VERSION 5.8 ;
BUSBITCHARS "[]" ;
DIVIDERCHAR "/" ;
UNITS
    DATABASE MICRONS 1000 ;
END UNITS

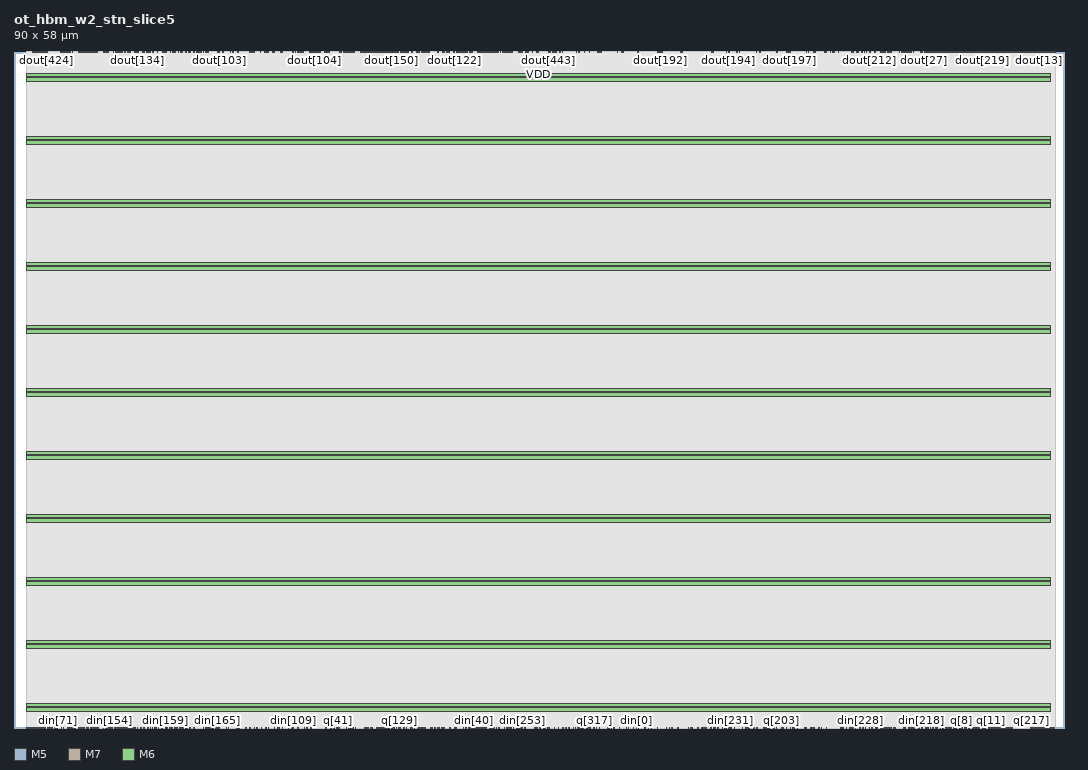
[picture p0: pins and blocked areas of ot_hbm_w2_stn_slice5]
MACRO ot_hbm_w2_stn_slice5
  FOREIGN ot_hbm_w2_stn_slice5 0 0 ;
  CLASS BLOCK ;
  SIZE 90 BY 58 ;
  PIN clk
    DIRECTION INPUT ;
    USE SIGNAL ;
    PORT
      LAYER M5 ;
        RECT  1.968 0 1.992 0.084 ;
    END
  END clk
  PIN din[0]
    DIRECTION INPUT ;
    USE SIGNAL ;
    PORT
      LAYER M5 ;
        RECT  53.328 0 53.352 0.084 ;
    END
  END din[0]
  PIN din[100]
    DIRECTION INPUT ;
    USE SIGNAL ;
    PORT
      LAYER M7 ;
        RECT  18.368 0 18.4 0.069 ;
    END
  END din[100]
  PIN din[101]
    DIRECTION INPUT ;
    USE SIGNAL ;
    PORT
      LAYER M7 ;
        RECT  18.176 0 18.208 0.069 ;
    END
  END din[101]
  PIN din[102]
    DIRECTION INPUT ;
    USE SIGNAL ;
    PORT
      LAYER M7 ;
        RECT  19.328 0 19.36 0.069 ;
    END
  END din[102]
  PIN din[103]
    DIRECTION INPUT ;
    USE SIGNAL ;
    PORT
      LAYER M5 ;
        RECT  17.04 0 17.064 0.084 ;
    END
  END din[103]
  PIN din[104]
    DIRECTION INPUT ;
    USE SIGNAL ;
    PORT
      LAYER M7 ;
        RECT  19.84 0 19.872 0.069 ;
    END
  END din[104]
  PIN din[105]
    DIRECTION INPUT ;
    USE SIGNAL ;
    PORT
      LAYER M7 ;
        RECT  17.6 0 17.632 0.069 ;
    END
  END din[105]
  PIN din[106]
    DIRECTION INPUT ;
    USE SIGNAL ;
    PORT
      LAYER M5 ;
        RECT  22.704 0 22.728 0.084 ;
    END
  END din[106]
  PIN din[107]
    DIRECTION INPUT ;
    USE SIGNAL ;
    PORT
      LAYER M7 ;
        RECT  21.568 0 21.6 0.069 ;
    END
  END din[107]
  PIN din[108]
    DIRECTION INPUT ;
    USE SIGNAL ;
    PORT
      LAYER M5 ;
        RECT  22.608 0 22.632 0.084 ;
    END
  END din[108]
  PIN din[109]
    DIRECTION INPUT ;
    USE SIGNAL ;
    PORT
      LAYER M5 ;
        RECT  23.952 0 23.976 0.084 ;
    END
  END din[109]
  PIN din[10]
    DIRECTION INPUT ;
    USE SIGNAL ;
    PORT
      LAYER M7 ;
        RECT  48.448 0 48.48 0.069 ;
    END
  END din[10]
  PIN din[110]
    DIRECTION INPUT ;
    USE SIGNAL ;
    PORT
      LAYER M5 ;
        RECT  23.76 0 23.784 0.084 ;
    END
  END din[110]
  PIN din[111]
    DIRECTION INPUT ;
    USE SIGNAL ;
    PORT
      LAYER M7 ;
        RECT  21.184 0 21.216 0.069 ;
    END
  END din[111]
  PIN din[112]
    DIRECTION INPUT ;
    USE SIGNAL ;
    PORT
      LAYER M5 ;
        RECT  27.744 0 27.768 0.084 ;
    END
  END din[112]
  PIN din[113]
    DIRECTION INPUT ;
    USE SIGNAL ;
    PORT
      LAYER M5 ;
        RECT  25.44 0 25.464 0.084 ;
    END
  END din[113]
  PIN din[114]
    DIRECTION INPUT ;
    USE SIGNAL ;
    PORT
      LAYER M5 ;
        RECT  17.328 0 17.352 0.084 ;
    END
  END din[114]
  PIN din[115]
    DIRECTION INPUT ;
    USE SIGNAL ;
    PORT
      LAYER M5 ;
        RECT  28.704 0 28.728 0.084 ;
    END
  END din[115]
  PIN din[116]
    DIRECTION INPUT ;
    USE SIGNAL ;
    PORT
      LAYER M7 ;
        RECT  20.608 0 20.64 0.069 ;
    END
  END din[116]
  PIN din[117]
    DIRECTION INPUT ;
    USE SIGNAL ;
    PORT
      LAYER M7 ;
        RECT  9.216 0 9.248 0.069 ;
    END
  END din[117]
  PIN din[118]
    DIRECTION INPUT ;
    USE SIGNAL ;
    PORT
      LAYER M5 ;
        RECT  26.736 0 26.76 0.084 ;
    END
  END din[118]
  PIN din[119]
    DIRECTION INPUT ;
    USE SIGNAL ;
    PORT
      LAYER M7 ;
        RECT  31.232 0 31.264 0.069 ;
    END
  END din[119]
  PIN din[11]
    DIRECTION INPUT ;
    USE SIGNAL ;
    PORT
      LAYER M7 ;
        RECT  58.112 0 58.144 0.069 ;
    END
  END din[11]
  PIN din[120]
    DIRECTION INPUT ;
    USE SIGNAL ;
    PORT
      LAYER M7 ;
        RECT  29.248 0 29.28 0.069 ;
    END
  END din[120]
  PIN din[121]
    DIRECTION INPUT ;
    USE SIGNAL ;
    PORT
      LAYER M7 ;
        RECT  32.576 0 32.608 0.069 ;
    END
  END din[121]
  PIN din[122]
    DIRECTION INPUT ;
    USE SIGNAL ;
    PORT
      LAYER M7 ;
        RECT  31.168 0 31.2 0.069 ;
    END
  END din[122]
  PIN din[123]
    DIRECTION INPUT ;
    USE SIGNAL ;
    PORT
      LAYER M7 ;
        RECT  33.408 0 33.44 0.069 ;
    END
  END din[123]
  PIN din[124]
    DIRECTION INPUT ;
    USE SIGNAL ;
    PORT
      LAYER M7 ;
        RECT  30.72 0 30.752 0.069 ;
    END
  END din[124]
  PIN din[125]
    DIRECTION INPUT ;
    USE SIGNAL ;
    PORT
      LAYER M7 ;
        RECT  33.6 0 33.632 0.069 ;
    END
  END din[125]
  PIN din[126]
    DIRECTION INPUT ;
    USE SIGNAL ;
    PORT
      LAYER M7 ;
        RECT  32.32 0 32.352 0.069 ;
    END
  END din[126]
  PIN din[127]
    DIRECTION INPUT ;
    USE SIGNAL ;
    PORT
      LAYER M7 ;
        RECT  31.936 0 31.968 0.069 ;
    END
  END din[127]
  PIN din[128]
    DIRECTION INPUT ;
    USE SIGNAL ;
    PORT
      LAYER M7 ;
        RECT  7.04 0 7.072 0.069 ;
    END
  END din[128]
  PIN din[129]
    DIRECTION INPUT ;
    USE SIGNAL ;
    PORT
      LAYER M5 ;
        RECT  3.504 0 3.528 0.084 ;
    END
  END din[129]
  PIN din[12]
    DIRECTION INPUT ;
    USE SIGNAL ;
    PORT
      LAYER M7 ;
        RECT  59.328 0 59.36 0.069 ;
    END
  END din[12]
  PIN din[130]
    DIRECTION INPUT ;
    USE SIGNAL ;
    PORT
      LAYER M7 ;
        RECT  6.592 0 6.624 0.069 ;
    END
  END din[130]
  PIN din[131]
    DIRECTION INPUT ;
    USE SIGNAL ;
    PORT
      LAYER M5 ;
        RECT  4.704 0 4.728 0.084 ;
    END
  END din[131]
  PIN din[132]
    DIRECTION INPUT ;
    USE SIGNAL ;
    PORT
      LAYER M5 ;
        RECT  5.616 0 5.64 0.084 ;
    END
  END din[132]
  PIN din[133]
    DIRECTION INPUT ;
    USE SIGNAL ;
    PORT
      LAYER M5 ;
        RECT  6.384 0 6.408 0.084 ;
    END
  END din[133]
  PIN din[134]
    DIRECTION INPUT ;
    USE SIGNAL ;
    PORT
      LAYER M7 ;
        RECT  6.528 0 6.56 0.069 ;
    END
  END din[134]
  PIN din[135]
    DIRECTION INPUT ;
    USE SIGNAL ;
    PORT
      LAYER M5 ;
        RECT  4.944 0 4.968 0.084 ;
    END
  END din[135]
  PIN din[136]
    DIRECTION INPUT ;
    USE SIGNAL ;
    PORT
      LAYER M5 ;
        RECT  4.032 0 4.056 0.084 ;
    END
  END din[136]
  PIN din[137]
    DIRECTION INPUT ;
    USE SIGNAL ;
    PORT
      LAYER M5 ;
        RECT  5.808 0 5.832 0.084 ;
    END
  END din[137]
  PIN din[138]
    DIRECTION INPUT ;
    USE SIGNAL ;
    PORT
      LAYER M5 ;
        RECT  3.264 0 3.288 0.084 ;
    END
  END din[138]
  PIN din[139]
    DIRECTION INPUT ;
    USE SIGNAL ;
    PORT
      LAYER M5 ;
        RECT  3.072 0 3.096 0.084 ;
    END
  END din[139]
  PIN din[13]
    DIRECTION INPUT ;
    USE SIGNAL ;
    PORT
      LAYER M7 ;
        RECT  58.56 0 58.592 0.069 ;
    END
  END din[13]
  PIN din[140]
    DIRECTION INPUT ;
    USE SIGNAL ;
    PORT
      LAYER M5 ;
        RECT  3.456 0 3.48 0.084 ;
    END
  END din[140]
  PIN din[141]
    DIRECTION INPUT ;
    USE SIGNAL ;
    PORT
      LAYER M5 ;
        RECT  2.832 0 2.856 0.084 ;
    END
  END din[141]
  PIN din[142]
    DIRECTION INPUT ;
    USE SIGNAL ;
    PORT
      LAYER M5 ;
        RECT  1.344 0 1.368 0.084 ;
    END
  END din[142]
  PIN din[143]
    DIRECTION INPUT ;
    USE SIGNAL ;
    PORT
      LAYER M5 ;
        RECT  1.104 0 1.128 0.084 ;
    END
  END din[143]
  PIN din[144]
    DIRECTION INPUT ;
    USE SIGNAL ;
    PORT
      LAYER M5 ;
        RECT  1.824 0 1.848 0.084 ;
    END
  END din[144]
  PIN din[145]
    DIRECTION INPUT ;
    USE SIGNAL ;
    PORT
      LAYER M5 ;
        RECT  2.064 0 2.088 0.084 ;
    END
  END din[145]
  PIN din[146]
    DIRECTION INPUT ;
    USE SIGNAL ;
    PORT
      LAYER M5 ;
        RECT  1.152 0 1.176 0.084 ;
    END
  END din[146]
  PIN din[147]
    DIRECTION INPUT ;
    USE SIGNAL ;
    PORT
      LAYER M5 ;
        RECT  1.584 0 1.608 0.084 ;
    END
  END din[147]
  PIN din[148]
    DIRECTION INPUT ;
    USE SIGNAL ;
    PORT
      LAYER M5 ;
        RECT  1.488 0 1.512 0.084 ;
    END
  END din[148]
  PIN din[149]
    DIRECTION INPUT ;
    USE SIGNAL ;
    PORT
      LAYER M5 ;
        RECT  1.296 0 1.32 0.084 ;
    END
  END din[149]
  PIN din[14]
    DIRECTION INPUT ;
    USE SIGNAL ;
    PORT
      LAYER M5 ;
        RECT  64.704 0 64.728 0.084 ;
    END
  END din[14]
  PIN din[150]
    DIRECTION INPUT ;
    USE SIGNAL ;
    PORT
      LAYER M5 ;
        RECT  1.44 0 1.464 0.084 ;
    END
  END din[150]
  PIN din[151]
    DIRECTION INPUT ;
    USE SIGNAL ;
    PORT
      LAYER M5 ;
        RECT  2.4 0 2.424 0.084 ;
    END
  END din[151]
  PIN din[152]
    DIRECTION INPUT ;
    USE SIGNAL ;
    PORT
      LAYER M5 ;
        RECT  2.304 0 2.328 0.084 ;
    END
  END din[152]
  PIN din[153]
    DIRECTION INPUT ;
    USE SIGNAL ;
    PORT
      LAYER M5 ;
        RECT  1.728 0 1.752 0.084 ;
    END
  END din[153]
  PIN din[154]
    DIRECTION INPUT ;
    USE SIGNAL ;
    PORT
      LAYER M7 ;
        RECT  8.128 0 8.16 0.069 ;
    END
  END din[154]
  PIN din[155]
    DIRECTION INPUT ;
    USE SIGNAL ;
    PORT
      LAYER M5 ;
        RECT  13.344 0 13.368 0.084 ;
    END
  END din[155]
  PIN din[156]
    DIRECTION INPUT ;
    USE SIGNAL ;
    PORT
      LAYER M5 ;
        RECT  13.776 0 13.8 0.084 ;
    END
  END din[156]
  PIN din[157]
    DIRECTION INPUT ;
    USE SIGNAL ;
    PORT
      LAYER M5 ;
        RECT  13.92 0 13.944 0.084 ;
    END
  END din[157]
  PIN din[158]
    DIRECTION INPUT ;
    USE SIGNAL ;
    PORT
      LAYER M7 ;
        RECT  8.32 0 8.352 0.069 ;
    END
  END din[158]
  PIN din[159]
    DIRECTION INPUT ;
    USE SIGNAL ;
    PORT
      LAYER M5 ;
        RECT  12.96 0 12.984 0.084 ;
    END
  END din[159]
  PIN din[15]
    DIRECTION INPUT ;
    USE SIGNAL ;
    PORT
      LAYER M5 ;
        RECT  64.368 0 64.392 0.084 ;
    END
  END din[15]
  PIN din[160]
    DIRECTION INPUT ;
    USE SIGNAL ;
    PORT
      LAYER M5 ;
        RECT  11.472 0 11.496 0.084 ;
    END
  END din[160]
  PIN din[161]
    DIRECTION INPUT ;
    USE SIGNAL ;
    PORT
      LAYER M7 ;
        RECT  9.088 0 9.12 0.069 ;
    END
  END din[161]
  PIN din[162]
    DIRECTION INPUT ;
    USE SIGNAL ;
    PORT
      LAYER M7 ;
        RECT  8.256 0 8.288 0.069 ;
    END
  END din[162]
  PIN din[163]
    DIRECTION INPUT ;
    USE SIGNAL ;
    PORT
      LAYER M5 ;
        RECT  12.384 0 12.408 0.084 ;
    END
  END din[163]
  PIN din[164]
    DIRECTION INPUT ;
    USE SIGNAL ;
    PORT
      LAYER M7 ;
        RECT  10.176 0 10.208 0.069 ;
    END
  END din[164]
  PIN din[165]
    DIRECTION INPUT ;
    USE SIGNAL ;
    PORT
      LAYER M5 ;
        RECT  17.472 0 17.496 0.084 ;
    END
  END din[165]
  PIN din[166]
    DIRECTION INPUT ;
    USE SIGNAL ;
    PORT
      LAYER M5 ;
        RECT  5.184 0 5.208 0.084 ;
    END
  END din[166]
  PIN din[167]
    DIRECTION INPUT ;
    USE SIGNAL ;
    PORT
      LAYER M5 ;
        RECT  17.376 0 17.4 0.084 ;
    END
  END din[167]
  PIN din[168]
    DIRECTION INPUT ;
    USE SIGNAL ;
    PORT
      LAYER M5 ;
        RECT  16.224 0 16.248 0.084 ;
    END
  END din[168]
  PIN din[169]
    DIRECTION INPUT ;
    USE SIGNAL ;
    PORT
      LAYER M5 ;
        RECT  16.944 0 16.968 0.084 ;
    END
  END din[169]
  PIN din[16]
    DIRECTION INPUT ;
    USE SIGNAL ;
    PORT
      LAYER M5 ;
        RECT  62.976 0 63 0.084 ;
    END
  END din[16]
  PIN din[170]
    DIRECTION INPUT ;
    USE SIGNAL ;
    PORT
      LAYER M5 ;
        RECT  16.848 0 16.872 0.084 ;
    END
  END din[170]
  PIN din[171]
    DIRECTION INPUT ;
    USE SIGNAL ;
    PORT
      LAYER M5 ;
        RECT  12.048 0 12.072 0.084 ;
    END
  END din[171]
  PIN din[172]
    DIRECTION INPUT ;
    USE SIGNAL ;
    PORT
      LAYER M5 ;
        RECT  16.896 0 16.92 0.084 ;
    END
  END din[172]
  PIN din[173]
    DIRECTION INPUT ;
    USE SIGNAL ;
    PORT
      LAYER M5 ;
        RECT  15.408 0 15.432 0.084 ;
    END
  END din[173]
  PIN din[174]
    DIRECTION INPUT ;
    USE SIGNAL ;
    PORT
      LAYER M5 ;
        RECT  15.024 0 15.048 0.084 ;
    END
  END din[174]
  PIN din[175]
    DIRECTION INPUT ;
    USE SIGNAL ;
    PORT
      LAYER M5 ;
        RECT  16.608 0 16.632 0.084 ;
    END
  END din[175]
  PIN din[176]
    DIRECTION INPUT ;
    USE SIGNAL ;
    PORT
      LAYER M5 ;
        RECT  16.416 0 16.44 0.084 ;
    END
  END din[176]
  PIN din[177]
    DIRECTION INPUT ;
    USE SIGNAL ;
    PORT
      LAYER M5 ;
        RECT  14.784 0 14.808 0.084 ;
    END
  END din[177]
  PIN din[178]
    DIRECTION INPUT ;
    USE SIGNAL ;
    PORT
      LAYER M5 ;
        RECT  13.536 0 13.56 0.084 ;
    END
  END din[178]
  PIN din[179]
    DIRECTION INPUT ;
    USE SIGNAL ;
    PORT
      LAYER M5 ;
        RECT  11.424 0 11.448 0.084 ;
    END
  END din[179]
  PIN din[17]
    DIRECTION INPUT ;
    USE SIGNAL ;
    PORT
      LAYER M7 ;
        RECT  57.984 0 58.016 0.069 ;
    END
  END din[17]
  PIN din[180]
    DIRECTION INPUT ;
    USE SIGNAL ;
    PORT
      LAYER M7 ;
        RECT  8.576 0 8.608 0.069 ;
    END
  END din[180]
  PIN din[181]
    DIRECTION INPUT ;
    USE SIGNAL ;
    PORT
      LAYER M5 ;
        RECT  14.16 0 14.184 0.084 ;
    END
  END din[181]
  PIN din[182]
    DIRECTION INPUT ;
    USE SIGNAL ;
    PORT
      LAYER M5 ;
        RECT  12.672 0 12.696 0.084 ;
    END
  END din[182]
  PIN din[183]
    DIRECTION INPUT ;
    USE SIGNAL ;
    PORT
      LAYER M7 ;
        RECT  11.136 0 11.168 0.069 ;
    END
  END din[183]
  PIN din[184]
    DIRECTION INPUT ;
    USE SIGNAL ;
    PORT
      LAYER M7 ;
        RECT  10.112 0 10.144 0.069 ;
    END
  END din[184]
  PIN din[185]
    DIRECTION INPUT ;
    USE SIGNAL ;
    PORT
      LAYER M7 ;
        RECT  9.92 0 9.952 0.069 ;
    END
  END din[185]
  PIN din[186]
    DIRECTION INPUT ;
    USE SIGNAL ;
    PORT
      LAYER M7 ;
        RECT  10.816 0 10.848 0.069 ;
    END
  END din[186]
  PIN din[187]
    DIRECTION INPUT ;
    USE SIGNAL ;
    PORT
      LAYER M7 ;
        RECT  8.192 0 8.224 0.069 ;
    END
  END din[187]
  PIN din[188]
    DIRECTION INPUT ;
    USE SIGNAL ;
    PORT
      LAYER M7 ;
        RECT  9.024 0 9.056 0.069 ;
    END
  END din[188]
  PIN din[189]
    DIRECTION INPUT ;
    USE SIGNAL ;
    PORT
      LAYER M7 ;
        RECT  9.536 0 9.568 0.069 ;
    END
  END din[189]
  PIN din[18]
    DIRECTION INPUT ;
    USE SIGNAL ;
    PORT
      LAYER M5 ;
        RECT  66.192 0 66.216 0.084 ;
    END
  END din[18]
  PIN din[190]
    DIRECTION INPUT ;
    USE SIGNAL ;
    PORT
      LAYER M7 ;
        RECT  6.656 0 6.688 0.069 ;
    END
  END din[190]
  PIN din[191]
    DIRECTION INPUT ;
    USE SIGNAL ;
    PORT
      LAYER M7 ;
        RECT  8.768 0 8.8 0.069 ;
    END
  END din[191]
  PIN din[192]
    DIRECTION INPUT ;
    USE SIGNAL ;
    PORT
      LAYER M5 ;
        RECT  53.52 0 53.544 0.084 ;
    END
  END din[192]
  PIN din[193]
    DIRECTION INPUT ;
    USE SIGNAL ;
    PORT
      LAYER M7 ;
        RECT  58.944 0 58.976 0.069 ;
    END
  END din[193]
  PIN din[194]
    DIRECTION INPUT ;
    USE SIGNAL ;
    PORT
      LAYER M5 ;
        RECT  60.96 0 60.984 0.084 ;
    END
  END din[194]
  PIN din[195]
    DIRECTION INPUT ;
    USE SIGNAL ;
    PORT
      LAYER M7 ;
        RECT  60.288 0 60.32 0.069 ;
    END
  END din[195]
  PIN din[196]
    DIRECTION INPUT ;
    USE SIGNAL ;
    PORT
      LAYER M7 ;
        RECT  48.32 0 48.352 0.069 ;
    END
  END din[196]
  PIN din[197]
    DIRECTION INPUT ;
    USE SIGNAL ;
    PORT
      LAYER M7 ;
        RECT  49.408 0 49.44 0.069 ;
    END
  END din[197]
  PIN din[198]
    DIRECTION INPUT ;
    USE SIGNAL ;
    PORT
      LAYER M5 ;
        RECT  51.216 0 51.24 0.084 ;
    END
  END din[198]
  PIN din[199]
    DIRECTION INPUT ;
    USE SIGNAL ;
    PORT
      LAYER M7 ;
        RECT  57.792 0 57.824 0.069 ;
    END
  END din[199]
  PIN din[19]
    DIRECTION INPUT ;
    USE SIGNAL ;
    PORT
      LAYER M5 ;
        RECT  66.768 0 66.792 0.084 ;
    END
  END din[19]
  PIN din[1]
    DIRECTION INPUT ;
    USE SIGNAL ;
    PORT
      LAYER M7 ;
        RECT  33.024 0 33.056 0.069 ;
    END
  END din[1]
  PIN din[200]
    DIRECTION INPUT ;
    USE SIGNAL ;
    PORT
      LAYER M7 ;
        RECT  48.64 0 48.672 0.069 ;
    END
  END din[200]
  PIN din[201]
    DIRECTION INPUT ;
    USE SIGNAL ;
    PORT
      LAYER M5 ;
        RECT  49.92 0 49.944 0.084 ;
    END
  END din[201]
  PIN din[202]
    DIRECTION INPUT ;
    USE SIGNAL ;
    PORT
      LAYER M5 ;
        RECT  50.832 0 50.856 0.084 ;
    END
  END din[202]
  PIN din[203]
    DIRECTION INPUT ;
    USE SIGNAL ;
    PORT
      LAYER M5 ;
        RECT  62.832 0 62.856 0.084 ;
    END
  END din[203]
  PIN din[204]
    DIRECTION INPUT ;
    USE SIGNAL ;
    PORT
      LAYER M5 ;
        RECT  61.44 0 61.464 0.084 ;
    END
  END din[204]
  PIN din[205]
    DIRECTION INPUT ;
    USE SIGNAL ;
    PORT
      LAYER M5 ;
        RECT  61.728 0 61.752 0.084 ;
    END
  END din[205]
  PIN din[206]
    DIRECTION INPUT ;
    USE SIGNAL ;
    PORT
      LAYER M7 ;
        RECT  60.352 0 60.384 0.069 ;
    END
  END din[206]
  PIN din[207]
    DIRECTION INPUT ;
    USE SIGNAL ;
    PORT
      LAYER M7 ;
        RECT  68.544 0 68.576 0.069 ;
    END
  END din[207]
  PIN din[208]
    DIRECTION INPUT ;
    USE SIGNAL ;
    PORT
      LAYER M5 ;
        RECT  65.952 0 65.976 0.084 ;
    END
  END din[208]
  PIN din[209]
    DIRECTION INPUT ;
    USE SIGNAL ;
    PORT
      LAYER M5 ;
        RECT  64.608 0 64.632 0.084 ;
    END
  END din[209]
  PIN din[20]
    DIRECTION INPUT ;
    USE SIGNAL ;
    PORT
      LAYER M7 ;
        RECT  60.736 0 60.768 0.069 ;
    END
  END din[20]
  PIN din[210]
    DIRECTION INPUT ;
    USE SIGNAL ;
    PORT
      LAYER M5 ;
        RECT  65.328 0 65.352 0.084 ;
    END
  END din[210]
  PIN din[211]
    DIRECTION INPUT ;
    USE SIGNAL ;
    PORT
      LAYER M7 ;
        RECT  71.616 0 71.648 0.069 ;
    END
  END din[211]
  PIN din[212]
    DIRECTION INPUT ;
    USE SIGNAL ;
    PORT
      LAYER M7 ;
        RECT  48.768 0 48.8 0.069 ;
    END
  END din[212]
  PIN din[213]
    DIRECTION INPUT ;
    USE SIGNAL ;
    PORT
      LAYER M7 ;
        RECT  71.68 0 71.712 0.069 ;
    END
  END din[213]
  PIN din[214]
    DIRECTION INPUT ;
    USE SIGNAL ;
    PORT
      LAYER M5 ;
        RECT  74.544 0 74.568 0.084 ;
    END
  END din[214]
  PIN din[215]
    DIRECTION INPUT ;
    USE SIGNAL ;
    PORT
      LAYER M5 ;
        RECT  74.88 0 74.904 0.084 ;
    END
  END din[215]
  PIN din[216]
    DIRECTION INPUT ;
    USE SIGNAL ;
    PORT
      LAYER M5 ;
        RECT  75.072 0 75.096 0.084 ;
    END
  END din[216]
  PIN din[217]
    DIRECTION INPUT ;
    USE SIGNAL ;
    PORT
      LAYER M7 ;
        RECT  45.888 0 45.92 0.069 ;
    END
  END din[217]
  PIN din[218]
    DIRECTION INPUT ;
    USE SIGNAL ;
    PORT
      LAYER M5 ;
        RECT  77.808 0 77.832 0.084 ;
    END
  END din[218]
  PIN din[219]
    DIRECTION INPUT ;
    USE SIGNAL ;
    PORT
      LAYER M5 ;
        RECT  76.368 0 76.392 0.084 ;
    END
  END din[219]
  PIN din[21]
    DIRECTION INPUT ;
    USE SIGNAL ;
    PORT
      LAYER M5 ;
        RECT  33.6 0 33.624 0.084 ;
    END
  END din[21]
  PIN din[220]
    DIRECTION INPUT ;
    USE SIGNAL ;
    PORT
      LAYER M5 ;
        RECT  77.76 0 77.784 0.084 ;
    END
  END din[220]
  PIN din[221]
    DIRECTION INPUT ;
    USE SIGNAL ;
    PORT
      LAYER M5 ;
        RECT  76.8 0 76.824 0.084 ;
    END
  END din[221]
  PIN din[222]
    DIRECTION INPUT ;
    USE SIGNAL ;
    PORT
      LAYER M5 ;
        RECT  76.944 0 76.968 0.084 ;
    END
  END din[222]
  PIN din[223]
    DIRECTION INPUT ;
    USE SIGNAL ;
    PORT
      LAYER M5 ;
        RECT  73.824 0 73.848 0.084 ;
    END
  END din[223]
  PIN din[224]
    DIRECTION INPUT ;
    USE SIGNAL ;
    PORT
      LAYER M5 ;
        RECT  75.12 0 75.144 0.084 ;
    END
  END din[224]
  PIN din[225]
    DIRECTION INPUT ;
    USE SIGNAL ;
    PORT
      LAYER M5 ;
        RECT  74.592 0 74.616 0.084 ;
    END
  END din[225]
  PIN din[226]
    DIRECTION INPUT ;
    USE SIGNAL ;
    PORT
      LAYER M5 ;
        RECT  73.872 0 73.896 0.084 ;
    END
  END din[226]
  PIN din[227]
    DIRECTION INPUT ;
    USE SIGNAL ;
    PORT
      LAYER M5 ;
        RECT  73.92 0 73.944 0.084 ;
    END
  END din[227]
  PIN din[228]
    DIRECTION INPUT ;
    USE SIGNAL ;
    PORT
      LAYER M5 ;
        RECT  72.576 0 72.6 0.084 ;
    END
  END din[228]
  PIN din[229]
    DIRECTION INPUT ;
    USE SIGNAL ;
    PORT
      LAYER M7 ;
        RECT  59.968 0 60 0.069 ;
    END
  END din[229]
  PIN din[22]
    DIRECTION INPUT ;
    USE SIGNAL ;
    PORT
      LAYER M5 ;
        RECT  51.888 0 51.912 0.084 ;
    END
  END din[22]
  PIN din[230]
    DIRECTION INPUT ;
    USE SIGNAL ;
    PORT
      LAYER M7 ;
        RECT  71.872 0 71.904 0.069 ;
    END
  END din[230]
  PIN din[231]
    DIRECTION INPUT ;
    USE SIGNAL ;
    PORT
      LAYER M5 ;
        RECT  61.392 0 61.416 0.084 ;
    END
  END din[231]
  PIN din[232]
    DIRECTION INPUT ;
    USE SIGNAL ;
    PORT
      LAYER M7 ;
        RECT  68.288 0 68.32 0.069 ;
    END
  END din[232]
  PIN din[233]
    DIRECTION INPUT ;
    USE SIGNAL ;
    PORT
      LAYER M7 ;
        RECT  70.976 0 71.008 0.069 ;
    END
  END din[233]
  PIN din[234]
    DIRECTION INPUT ;
    USE SIGNAL ;
    PORT
      LAYER M7 ;
        RECT  68.352 0 68.384 0.069 ;
    END
  END din[234]
  PIN din[235]
    DIRECTION INPUT ;
    USE SIGNAL ;
    PORT
      LAYER M7 ;
        RECT  70.848 0 70.88 0.069 ;
    END
  END din[235]
  PIN din[236]
    DIRECTION INPUT ;
    USE SIGNAL ;
    PORT
      LAYER M7 ;
        RECT  67.776 0 67.808 0.069 ;
    END
  END din[236]
  PIN din[237]
    DIRECTION INPUT ;
    USE SIGNAL ;
    PORT
      LAYER M5 ;
        RECT  61.248 0 61.272 0.084 ;
    END
  END din[237]
  PIN din[238]
    DIRECTION INPUT ;
    USE SIGNAL ;
    PORT
      LAYER M5 ;
        RECT  64.224 0 64.248 0.084 ;
    END
  END din[238]
  PIN din[239]
    DIRECTION INPUT ;
    USE SIGNAL ;
    PORT
      LAYER M5 ;
        RECT  61.344 0 61.368 0.084 ;
    END
  END din[239]
  PIN din[23]
    DIRECTION INPUT ;
    USE SIGNAL ;
    PORT
      LAYER M5 ;
        RECT  61.056 0 61.08 0.084 ;
    END
  END din[23]
  PIN din[240]
    DIRECTION INPUT ;
    USE SIGNAL ;
    PORT
      LAYER M5 ;
        RECT  63.696 0 63.72 0.084 ;
    END
  END din[240]
  PIN din[241]
    DIRECTION INPUT ;
    USE SIGNAL ;
    PORT
      LAYER M5 ;
        RECT  55.92 0 55.944 0.084 ;
    END
  END din[241]
  PIN din[242]
    DIRECTION INPUT ;
    USE SIGNAL ;
    PORT
      LAYER M7 ;
        RECT  56.384 0 56.416 0.069 ;
    END
  END din[242]
  PIN din[243]
    DIRECTION INPUT ;
    USE SIGNAL ;
    PORT
      LAYER M5 ;
        RECT  55.152 0 55.176 0.084 ;
    END
  END din[243]
  PIN din[244]
    DIRECTION INPUT ;
    USE SIGNAL ;
    PORT
      LAYER M5 ;
        RECT  53.088 0 53.112 0.084 ;
    END
  END din[244]
  PIN din[245]
    DIRECTION INPUT ;
    USE SIGNAL ;
    PORT
      LAYER M7 ;
        RECT  47.552 0 47.584 0.069 ;
    END
  END din[245]
  PIN din[246]
    DIRECTION INPUT ;
    USE SIGNAL ;
    PORT
      LAYER M7 ;
        RECT  48.384 0 48.416 0.069 ;
    END
  END din[246]
  PIN din[247]
    DIRECTION INPUT ;
    USE SIGNAL ;
    PORT
      LAYER M7 ;
        RECT  48.512 0 48.544 0.069 ;
    END
  END din[247]
  PIN din[248]
    DIRECTION INPUT ;
    USE SIGNAL ;
    PORT
      LAYER M7 ;
        RECT  47.04 0 47.072 0.069 ;
    END
  END din[248]
  PIN din[249]
    DIRECTION INPUT ;
    USE SIGNAL ;
    PORT
      LAYER M7 ;
        RECT  45.376 0 45.408 0.069 ;
    END
  END din[249]
  PIN din[24]
    DIRECTION INPUT ;
    USE SIGNAL ;
    PORT
      LAYER M5 ;
        RECT  61.776 0 61.8 0.084 ;
    END
  END din[24]
  PIN din[250]
    DIRECTION INPUT ;
    USE SIGNAL ;
    PORT
      LAYER M7 ;
        RECT  44.8 0 44.832 0.069 ;
    END
  END din[250]
  PIN din[251]
    DIRECTION INPUT ;
    USE SIGNAL ;
    PORT
      LAYER M5 ;
        RECT  42.576 0 42.6 0.084 ;
    END
  END din[251]
  PIN din[252]
    DIRECTION INPUT ;
    USE SIGNAL ;
    PORT
      LAYER M5 ;
        RECT  42.624 0 42.648 0.084 ;
    END
  END din[252]
  PIN din[253]
    DIRECTION INPUT ;
    USE SIGNAL ;
    PORT
      LAYER M5 ;
        RECT  43.584 0 43.608 0.084 ;
    END
  END din[253]
  PIN din[254]
    DIRECTION INPUT ;
    USE SIGNAL ;
    PORT
      LAYER M7 ;
        RECT  45.12 0 45.152 0.069 ;
    END
  END din[254]
  PIN din[255]
    DIRECTION INPUT ;
    USE SIGNAL ;
    PORT
      LAYER M5 ;
        RECT  43.44 0 43.464 0.084 ;
    END
  END din[255]
  PIN din[256]
    DIRECTION INPUT ;
    USE SIGNAL ;
    PORT
      LAYER M5 ;
        RECT  51.408 0 51.432 0.084 ;
    END
  END din[256]
  PIN din[257]
    DIRECTION INPUT ;
    USE SIGNAL ;
    PORT
      LAYER M5 ;
        RECT  54.624 0 54.648 0.084 ;
    END
  END din[257]
  PIN din[258]
    DIRECTION INPUT ;
    USE SIGNAL ;
    PORT
      LAYER M7 ;
        RECT  56.896 0 56.928 0.069 ;
    END
  END din[258]
  PIN din[259]
    DIRECTION INPUT ;
    USE SIGNAL ;
    PORT
      LAYER M5 ;
        RECT  54.048 0 54.072 0.084 ;
    END
  END din[259]
  PIN din[25]
    DIRECTION INPUT ;
    USE SIGNAL ;
    PORT
      LAYER M5 ;
        RECT  41.184 0 41.208 0.084 ;
    END
  END din[25]
  PIN din[260]
    DIRECTION INPUT ;
    USE SIGNAL ;
    PORT
      LAYER M7 ;
        RECT  69.632 0 69.664 0.069 ;
    END
  END din[260]
  PIN din[261]
    DIRECTION INPUT ;
    USE SIGNAL ;
    PORT
      LAYER M5 ;
        RECT  60.864 0 60.888 0.084 ;
    END
  END din[261]
  PIN din[262]
    DIRECTION INPUT ;
    USE SIGNAL ;
    PORT
      LAYER M7 ;
        RECT  59.264 0 59.296 0.069 ;
    END
  END din[262]
  PIN din[263]
    DIRECTION INPUT ;
    USE SIGNAL ;
    PORT
      LAYER M7 ;
        RECT  59.136 0 59.168 0.069 ;
    END
  END din[263]
  PIN din[264]
    DIRECTION INPUT ;
    USE SIGNAL ;
    PORT
      LAYER M7 ;
        RECT  67.84 0 67.872 0.069 ;
    END
  END din[264]
  PIN din[265]
    DIRECTION INPUT ;
    USE SIGNAL ;
    PORT
      LAYER M5 ;
        RECT  62.448 0 62.472 0.084 ;
    END
  END din[265]
  PIN din[266]
    DIRECTION INPUT ;
    USE SIGNAL ;
    PORT
      LAYER M7 ;
        RECT  59.712 0 59.744 0.069 ;
    END
  END din[266]
  PIN din[267]
    DIRECTION INPUT ;
    USE SIGNAL ;
    PORT
      LAYER M5 ;
        RECT  66.576 0 66.6 0.084 ;
    END
  END din[267]
  PIN din[268]
    DIRECTION INPUT ;
    USE SIGNAL ;
    PORT
      LAYER M5 ;
        RECT  63.408 0 63.432 0.084 ;
    END
  END din[268]
  PIN din[269]
    DIRECTION INPUT ;
    USE SIGNAL ;
    PORT
      LAYER M5 ;
        RECT  66.912 0 66.936 0.084 ;
    END
  END din[269]
  PIN din[26]
    DIRECTION INPUT ;
    USE SIGNAL ;
    PORT
      LAYER M5 ;
        RECT  38.928 0 38.952 0.084 ;
    END
  END din[26]
  PIN din[270]
    DIRECTION INPUT ;
    USE SIGNAL ;
    PORT
      LAYER M7 ;
        RECT  67.904 0 67.936 0.069 ;
    END
  END din[270]
  PIN din[271]
    DIRECTION INPUT ;
    USE SIGNAL ;
    PORT
      LAYER M7 ;
        RECT  68.608 0 68.64 0.069 ;
    END
  END din[271]
  PIN din[272]
    DIRECTION INPUT ;
    USE SIGNAL ;
    PORT
      LAYER M7 ;
        RECT  71.744 0 71.776 0.069 ;
    END
  END din[272]
  PIN din[273]
    DIRECTION INPUT ;
    USE SIGNAL ;
    PORT
      LAYER M7 ;
        RECT  71.04 0 71.072 0.069 ;
    END
  END din[273]
  PIN din[274]
    DIRECTION INPUT ;
    USE SIGNAL ;
    PORT
      LAYER M5 ;
        RECT  73.344 0 73.368 0.084 ;
    END
  END din[274]
  PIN din[275]
    DIRECTION INPUT ;
    USE SIGNAL ;
    PORT
      LAYER M5 ;
        RECT  74.64 0 74.664 0.084 ;
    END
  END din[275]
  PIN din[276]
    DIRECTION INPUT ;
    USE SIGNAL ;
    PORT
      LAYER M5 ;
        RECT  75.504 0 75.528 0.084 ;
    END
  END din[276]
  PIN din[277]
    DIRECTION INPUT ;
    USE SIGNAL ;
    PORT
      LAYER M5 ;
        RECT  72.432 0 72.456 0.084 ;
    END
  END din[277]
  PIN din[278]
    DIRECTION INPUT ;
    USE SIGNAL ;
    PORT
      LAYER M5 ;
        RECT  74.736 0 74.76 0.084 ;
    END
  END din[278]
  PIN din[279]
    DIRECTION INPUT ;
    USE SIGNAL ;
    PORT
      LAYER M5 ;
        RECT  72.96 0 72.984 0.084 ;
    END
  END din[279]
  PIN din[27]
    DIRECTION INPUT ;
    USE SIGNAL ;
    PORT
      LAYER M5 ;
        RECT  35.28 0 35.304 0.084 ;
    END
  END din[27]
  PIN din[28]
    DIRECTION INPUT ;
    USE SIGNAL ;
    PORT
      LAYER M5 ;
        RECT  38.976 0 39 0.084 ;
    END
  END din[28]
  PIN din[29]
    DIRECTION INPUT ;
    USE SIGNAL ;
    PORT
      LAYER M5 ;
        RECT  43.776 0 43.8 0.084 ;
    END
  END din[29]
  PIN din[2]
    DIRECTION INPUT ;
    USE SIGNAL ;
    PORT
      LAYER M5 ;
        RECT  52.464 0 52.488 0.084 ;
    END
  END din[2]
  PIN din[30]
    DIRECTION INPUT ;
    USE SIGNAL ;
    PORT
      LAYER M5 ;
        RECT  41.04 0 41.064 0.084 ;
    END
  END din[30]
  PIN din[31]
    DIRECTION INPUT ;
    USE SIGNAL ;
    PORT
      LAYER M5 ;
        RECT  35.232 0 35.256 0.084 ;
    END
  END din[31]
  PIN din[32]
    DIRECTION INPUT ;
    USE SIGNAL ;
    PORT
      LAYER M5 ;
        RECT  43.104 0 43.128 0.084 ;
    END
  END din[32]
  PIN din[33]
    DIRECTION INPUT ;
    USE SIGNAL ;
    PORT
      LAYER M5 ;
        RECT  42.336 0 42.36 0.084 ;
    END
  END din[33]
  PIN din[34]
    DIRECTION INPUT ;
    USE SIGNAL ;
    PORT
      LAYER M5 ;
        RECT  42.816 0 42.84 0.084 ;
    END
  END din[34]
  PIN din[35]
    DIRECTION INPUT ;
    USE SIGNAL ;
    PORT
      LAYER M5 ;
        RECT  35.04 0 35.064 0.084 ;
    END
  END din[35]
  PIN din[36]
    DIRECTION INPUT ;
    USE SIGNAL ;
    PORT
      LAYER M5 ;
        RECT  42.288 0 42.312 0.084 ;
    END
  END din[36]
  PIN din[37]
    DIRECTION INPUT ;
    USE SIGNAL ;
    PORT
      LAYER M5 ;
        RECT  40.176 0 40.2 0.084 ;
    END
  END din[37]
  PIN din[38]
    DIRECTION INPUT ;
    USE SIGNAL ;
    PORT
      LAYER M5 ;
        RECT  40.08 0 40.104 0.084 ;
    END
  END din[38]
  PIN din[39]
    DIRECTION INPUT ;
    USE SIGNAL ;
    PORT
      LAYER M5 ;
        RECT  40.416 0 40.44 0.084 ;
    END
  END din[39]
  PIN din[3]
    DIRECTION INPUT ;
    USE SIGNAL ;
    PORT
      LAYER M7 ;
        RECT  49.088 0 49.12 0.069 ;
    END
  END din[3]
  PIN din[40]
    DIRECTION INPUT ;
    USE SIGNAL ;
    PORT
      LAYER M5 ;
        RECT  39.456 0 39.48 0.084 ;
    END
  END din[40]
  PIN din[41]
    DIRECTION INPUT ;
    USE SIGNAL ;
    PORT
      LAYER M5 ;
        RECT  38.736 0 38.76 0.084 ;
    END
  END din[41]
  PIN din[42]
    DIRECTION INPUT ;
    USE SIGNAL ;
    PORT
      LAYER M5 ;
        RECT  38.688 0 38.712 0.084 ;
    END
  END din[42]
  PIN din[43]
    DIRECTION INPUT ;
    USE SIGNAL ;
    PORT
      LAYER M5 ;
        RECT  37.776 0 37.8 0.084 ;
    END
  END din[43]
  PIN din[44]
    DIRECTION INPUT ;
    USE SIGNAL ;
    PORT
      LAYER M5 ;
        RECT  37.92 0 37.944 0.084 ;
    END
  END din[44]
  PIN din[45]
    DIRECTION INPUT ;
    USE SIGNAL ;
    PORT
      LAYER M5 ;
        RECT  36.384 0 36.408 0.084 ;
    END
  END din[45]
  PIN din[46]
    DIRECTION INPUT ;
    USE SIGNAL ;
    PORT
      LAYER M5 ;
        RECT  36.672 0 36.696 0.084 ;
    END
  END din[46]
  PIN din[47]
    DIRECTION INPUT ;
    USE SIGNAL ;
    PORT
      LAYER M5 ;
        RECT  35.184 0 35.208 0.084 ;
    END
  END din[47]
  PIN din[48]
    DIRECTION INPUT ;
    USE SIGNAL ;
    PORT
      LAYER M5 ;
        RECT  36.864 0 36.888 0.084 ;
    END
  END din[48]
  PIN din[49]
    DIRECTION INPUT ;
    USE SIGNAL ;
    PORT
      LAYER M7 ;
        RECT  32.448 0 32.48 0.069 ;
    END
  END din[49]
  PIN din[4]
    DIRECTION INPUT ;
    USE SIGNAL ;
    PORT
      LAYER M5 ;
        RECT  51.36 0 51.384 0.084 ;
    END
  END din[4]
  PIN din[50]
    DIRECTION INPUT ;
    USE SIGNAL ;
    PORT
      LAYER M7 ;
        RECT  32.768 0 32.8 0.069 ;
    END
  END din[50]
  PIN din[51]
    DIRECTION INPUT ;
    USE SIGNAL ;
    PORT
      LAYER M7 ;
        RECT  31.872 0 31.904 0.069 ;
    END
  END din[51]
  PIN din[52]
    DIRECTION INPUT ;
    USE SIGNAL ;
    PORT
      LAYER M5 ;
        RECT  34.608 0 34.632 0.084 ;
    END
  END din[52]
  PIN din[53]
    DIRECTION INPUT ;
    USE SIGNAL ;
    PORT
      LAYER M5 ;
        RECT  35.664 0 35.688 0.084 ;
    END
  END din[53]
  PIN din[54]
    DIRECTION INPUT ;
    USE SIGNAL ;
    PORT
      LAYER M5 ;
        RECT  34.56 0 34.584 0.084 ;
    END
  END din[54]
  PIN din[55]
    DIRECTION INPUT ;
    USE SIGNAL ;
    PORT
      LAYER M5 ;
        RECT  34.8 0 34.824 0.084 ;
    END
  END din[55]
  PIN din[56]
    DIRECTION INPUT ;
    USE SIGNAL ;
    PORT
      LAYER M5 ;
        RECT  36 0 36.024 0.084 ;
    END
  END din[56]
  PIN din[57]
    DIRECTION INPUT ;
    USE SIGNAL ;
    PORT
      LAYER M7 ;
        RECT  32.128 0 32.16 0.069 ;
    END
  END din[57]
  PIN din[58]
    DIRECTION INPUT ;
    USE SIGNAL ;
    PORT
      LAYER M7 ;
        RECT  31.488 0 31.52 0.069 ;
    END
  END din[58]
  PIN din[59]
    DIRECTION INPUT ;
    USE SIGNAL ;
    PORT
      LAYER M7 ;
        RECT  32.192 0 32.224 0.069 ;
    END
  END din[59]
  PIN din[5]
    DIRECTION INPUT ;
    USE SIGNAL ;
    PORT
      LAYER M5 ;
        RECT  50.16 0 50.184 0.084 ;
    END
  END din[5]
  PIN din[60]
    DIRECTION INPUT ;
    USE SIGNAL ;
    PORT
      LAYER M7 ;
        RECT  31.552 0 31.584 0.069 ;
    END
  END din[60]
  PIN din[61]
    DIRECTION INPUT ;
    USE SIGNAL ;
    PORT
      LAYER M7 ;
        RECT  31.68 0 31.712 0.069 ;
    END
  END din[61]
  PIN din[62]
    DIRECTION INPUT ;
    USE SIGNAL ;
    PORT
      LAYER M7 ;
        RECT  32.96 0 32.992 0.069 ;
    END
  END din[62]
  PIN din[63]
    DIRECTION INPUT ;
    USE SIGNAL ;
    PORT
      LAYER M7 ;
        RECT  31.744 0 31.776 0.069 ;
    END
  END din[63]
  PIN din[64]
    DIRECTION INPUT ;
    USE SIGNAL ;
    PORT
      LAYER M5 ;
        RECT  16.992 0 17.016 0.084 ;
    END
  END din[64]
  PIN din[65]
    DIRECTION INPUT ;
    USE SIGNAL ;
    PORT
      LAYER M7 ;
        RECT  7.936 0 7.968 0.069 ;
    END
  END din[65]
  PIN din[66]
    DIRECTION INPUT ;
    USE SIGNAL ;
    PORT
      LAYER M7 ;
        RECT  8.64 0 8.672 0.069 ;
    END
  END din[66]
  PIN din[67]
    DIRECTION INPUT ;
    USE SIGNAL ;
    PORT
      LAYER M7 ;
        RECT  9.792 0 9.824 0.069 ;
    END
  END din[67]
  PIN din[68]
    DIRECTION INPUT ;
    USE SIGNAL ;
    PORT
      LAYER M7 ;
        RECT  6.72 0 6.752 0.069 ;
    END
  END din[68]
  PIN din[69]
    DIRECTION INPUT ;
    USE SIGNAL ;
    PORT
      LAYER M5 ;
        RECT  5.952 0 5.976 0.084 ;
    END
  END din[69]
  PIN din[6]
    DIRECTION INPUT ;
    USE SIGNAL ;
    PORT
      LAYER M5 ;
        RECT  40.32 0 40.344 0.084 ;
    END
  END din[6]
  PIN din[70]
    DIRECTION INPUT ;
    USE SIGNAL ;
    PORT
      LAYER M5 ;
        RECT  6.192 0 6.216 0.084 ;
    END
  END din[70]
  PIN din[71]
    DIRECTION INPUT ;
    USE SIGNAL ;
    PORT
      LAYER M5 ;
        RECT  3.744 0 3.768 0.084 ;
    END
  END din[71]
  PIN din[72]
    DIRECTION INPUT ;
    USE SIGNAL ;
    PORT
      LAYER M5 ;
        RECT  2.544 0 2.568 0.084 ;
    END
  END din[72]
  PIN din[73]
    DIRECTION INPUT ;
    USE SIGNAL ;
    PORT
      LAYER M5 ;
        RECT  1.248 0 1.272 0.084 ;
    END
  END din[73]
  PIN din[74]
    DIRECTION INPUT ;
    USE SIGNAL ;
    PORT
      LAYER M5 ;
        RECT  3.168 0 3.192 0.084 ;
    END
  END din[74]
  PIN din[75]
    DIRECTION INPUT ;
    USE SIGNAL ;
    PORT
      LAYER M5 ;
        RECT  1.2 0 1.224 0.084 ;
    END
  END din[75]
  PIN din[76]
    DIRECTION INPUT ;
    USE SIGNAL ;
    PORT
      LAYER M5 ;
        RECT  1.392 0 1.416 0.084 ;
    END
  END din[76]
  PIN din[77]
    DIRECTION INPUT ;
    USE SIGNAL ;
    PORT
      LAYER M5 ;
        RECT  4.56 0 4.584 0.084 ;
    END
  END din[77]
  PIN din[78]
    DIRECTION INPUT ;
    USE SIGNAL ;
    PORT
      LAYER M5 ;
        RECT  1.536 0 1.56 0.084 ;
    END
  END din[78]
  PIN din[79]
    DIRECTION INPUT ;
    USE SIGNAL ;
    PORT
      LAYER M5 ;
        RECT  2.016 0 2.04 0.084 ;
    END
  END din[79]
  PIN din[7]
    DIRECTION INPUT ;
    USE SIGNAL ;
    PORT
      LAYER M5 ;
        RECT  52.656 0 52.68 0.084 ;
    END
  END din[7]
  PIN din[80]
    DIRECTION INPUT ;
    USE SIGNAL ;
    PORT
      LAYER M5 ;
        RECT  2.256 0 2.28 0.084 ;
    END
  END din[80]
  PIN din[81]
    DIRECTION INPUT ;
    USE SIGNAL ;
    PORT
      LAYER M5 ;
        RECT  6.24 0 6.264 0.084 ;
    END
  END din[81]
  PIN din[82]
    DIRECTION INPUT ;
    USE SIGNAL ;
    PORT
      LAYER M5 ;
        RECT  1.776 0 1.8 0.084 ;
    END
  END din[82]
  PIN din[83]
    DIRECTION INPUT ;
    USE SIGNAL ;
    PORT
      LAYER M5 ;
        RECT  4.224 0 4.248 0.084 ;
    END
  END din[83]
  PIN din[84]
    DIRECTION INPUT ;
    USE SIGNAL ;
    PORT
      LAYER M5 ;
        RECT  2.496 0 2.52 0.084 ;
    END
  END din[84]
  PIN din[85]
    DIRECTION INPUT ;
    USE SIGNAL ;
    PORT
      LAYER M5 ;
        RECT  5.664 0 5.688 0.084 ;
    END
  END din[85]
  PIN din[86]
    DIRECTION INPUT ;
    USE SIGNAL ;
    PORT
      LAYER M7 ;
        RECT  8.448 0 8.48 0.069 ;
    END
  END din[86]
  PIN din[87]
    DIRECTION INPUT ;
    USE SIGNAL ;
    PORT
      LAYER M5 ;
        RECT  3.12 0 3.144 0.084 ;
    END
  END din[87]
  PIN din[88]
    DIRECTION INPUT ;
    USE SIGNAL ;
    PORT
      LAYER M7 ;
        RECT  8.384 0 8.416 0.069 ;
    END
  END din[88]
  PIN din[89]
    DIRECTION INPUT ;
    USE SIGNAL ;
    PORT
      LAYER M7 ;
        RECT  6.784 0 6.816 0.069 ;
    END
  END din[89]
  PIN din[8]
    DIRECTION INPUT ;
    USE SIGNAL ;
    PORT
      LAYER M5 ;
        RECT  42.048 0 42.072 0.084 ;
    END
  END din[8]
  PIN din[90]
    DIRECTION INPUT ;
    USE SIGNAL ;
    PORT
      LAYER M7 ;
        RECT  8.704 0 8.736 0.069 ;
    END
  END din[90]
  PIN din[91]
    DIRECTION INPUT ;
    USE SIGNAL ;
    PORT
      LAYER M5 ;
        RECT  4.8 0 4.824 0.084 ;
    END
  END din[91]
  PIN din[92]
    DIRECTION INPUT ;
    USE SIGNAL ;
    PORT
      LAYER M7 ;
        RECT  6.976 0 7.008 0.069 ;
    END
  END din[92]
  PIN din[93]
    DIRECTION INPUT ;
    USE SIGNAL ;
    PORT
      LAYER M7 ;
        RECT  9.28 0 9.312 0.069 ;
    END
  END din[93]
  PIN din[94]
    DIRECTION INPUT ;
    USE SIGNAL ;
    PORT
      LAYER M5 ;
        RECT  11.712 0 11.736 0.084 ;
    END
  END din[94]
  PIN din[95]
    DIRECTION INPUT ;
    USE SIGNAL ;
    PORT
      LAYER M5 ;
        RECT  12.72 0 12.744 0.084 ;
    END
  END din[95]
  PIN din[96]
    DIRECTION INPUT ;
    USE SIGNAL ;
    PORT
      LAYER M7 ;
        RECT  10.368 0 10.4 0.069 ;
    END
  END din[96]
  PIN din[97]
    DIRECTION INPUT ;
    USE SIGNAL ;
    PORT
      LAYER M5 ;
        RECT  16.512 0 16.536 0.084 ;
    END
  END din[97]
  PIN din[98]
    DIRECTION INPUT ;
    USE SIGNAL ;
    PORT
      LAYER M5 ;
        RECT  14.88 0 14.904 0.084 ;
    END
  END din[98]
  PIN din[99]
    DIRECTION INPUT ;
    USE SIGNAL ;
    PORT
      LAYER M5 ;
        RECT  13.968 0 13.992 0.084 ;
    END
  END din[99]
  PIN din[9]
    DIRECTION INPUT ;
    USE SIGNAL ;
    PORT
      LAYER M5 ;
        RECT  37.392 0 37.416 0.084 ;
    END
  END din[9]
  PIN dout[0]
    DIRECTION OUTPUT ;
    USE SIGNAL ;
    PORT
      LAYER M7 ;
        RECT  84.608 57.931 84.64 58 ;
    END
  END dout[0]
  PIN dout[100]
    DIRECTION OUTPUT ;
    USE SIGNAL ;
    PORT
      LAYER M7 ;
        RECT  6.784 57.931 6.816 58 ;
    END
  END dout[100]
  PIN dout[101]
    DIRECTION OUTPUT ;
    USE SIGNAL ;
    PORT
      LAYER M7 ;
        RECT  20.416 57.931 20.448 58 ;
    END
  END dout[101]
  PIN dout[102]
    DIRECTION OUTPUT ;
    USE SIGNAL ;
    PORT
      LAYER M7 ;
        RECT  21.12 57.931 21.152 58 ;
    END
  END dout[102]
  PIN dout[103]
    DIRECTION OUTPUT ;
    USE SIGNAL ;
    PORT
      LAYER M5 ;
        RECT  17.568 57.916 17.592 58 ;
    END
  END dout[103]
  PIN dout[104]
    DIRECTION OUTPUT ;
    USE SIGNAL ;
    PORT
      LAYER M5 ;
        RECT  25.728 57.916 25.752 58 ;
    END
  END dout[104]
  PIN dout[105]
    DIRECTION OUTPUT ;
    USE SIGNAL ;
    PORT
      LAYER M5 ;
        RECT  26.784 57.916 26.808 58 ;
    END
  END dout[105]
  PIN dout[106]
    DIRECTION OUTPUT ;
    USE SIGNAL ;
    PORT
      LAYER M7 ;
        RECT  41.152 57.931 41.184 58 ;
    END
  END dout[106]
  PIN dout[107]
    DIRECTION OUTPUT ;
    USE SIGNAL ;
    PORT
      LAYER M7 ;
        RECT  30.016 57.931 30.048 58 ;
    END
  END dout[107]
  PIN dout[108]
    DIRECTION OUTPUT ;
    USE SIGNAL ;
    PORT
      LAYER M7 ;
        RECT  22.144 57.931 22.176 58 ;
    END
  END dout[108]
  PIN dout[109]
    DIRECTION OUTPUT ;
    USE SIGNAL ;
    PORT
      LAYER M5 ;
        RECT  26.208 57.916 26.232 58 ;
    END
  END dout[109]
  PIN dout[10]
    DIRECTION OUTPUT ;
    USE SIGNAL ;
    PORT
      LAYER M7 ;
        RECT  78.272 57.931 78.304 58 ;
    END
  END dout[10]
  PIN dout[110]
    DIRECTION OUTPUT ;
    USE SIGNAL ;
    PORT
      LAYER M7 ;
        RECT  41.408 57.931 41.44 58 ;
    END
  END dout[110]
  PIN dout[111]
    DIRECTION OUTPUT ;
    USE SIGNAL ;
    PORT
      LAYER M5 ;
        RECT  26.832 57.916 26.856 58 ;
    END
  END dout[111]
  PIN dout[112]
    DIRECTION OUTPUT ;
    USE SIGNAL ;
    PORT
      LAYER M7 ;
        RECT  43.392 57.931 43.424 58 ;
    END
  END dout[112]
  PIN dout[113]
    DIRECTION OUTPUT ;
    USE SIGNAL ;
    PORT
      LAYER M7 ;
        RECT  21.504 57.931 21.536 58 ;
    END
  END dout[113]
  PIN dout[114]
    DIRECTION OUTPUT ;
    USE SIGNAL ;
    PORT
      LAYER M5 ;
        RECT  25.44 57.916 25.464 58 ;
    END
  END dout[114]
  PIN dout[115]
    DIRECTION OUTPUT ;
    USE SIGNAL ;
    PORT
      LAYER M7 ;
        RECT  31.232 57.931 31.264 58 ;
    END
  END dout[115]
  PIN dout[116]
    DIRECTION OUTPUT ;
    USE SIGNAL ;
    PORT
      LAYER M5 ;
        RECT  12.912 57.916 12.936 58 ;
    END
  END dout[116]
  PIN dout[117]
    DIRECTION OUTPUT ;
    USE SIGNAL ;
    PORT
      LAYER M7 ;
        RECT  41.664 57.931 41.696 58 ;
    END
  END dout[117]
  PIN dout[118]
    DIRECTION OUTPUT ;
    USE SIGNAL ;
    PORT
      LAYER M5 ;
        RECT  28.464 57.916 28.488 58 ;
    END
  END dout[118]
  PIN dout[119]
    DIRECTION OUTPUT ;
    USE SIGNAL ;
    PORT
      LAYER M7 ;
        RECT  44.928 57.931 44.96 58 ;
    END
  END dout[119]
  PIN dout[11]
    DIRECTION OUTPUT ;
    USE SIGNAL ;
    PORT
      LAYER M5 ;
        RECT  80.496 57.916 80.52 58 ;
    END
  END dout[11]
  PIN dout[120]
    DIRECTION OUTPUT ;
    USE SIGNAL ;
    PORT
      LAYER M5 ;
        RECT  34.944 57.916 34.968 58 ;
    END
  END dout[120]
  PIN dout[121]
    DIRECTION OUTPUT ;
    USE SIGNAL ;
    PORT
      LAYER M7 ;
        RECT  40 57.931 40.032 58 ;
    END
  END dout[121]
  PIN dout[122]
    DIRECTION OUTPUT ;
    USE SIGNAL ;
    PORT
      LAYER M5 ;
        RECT  37.776 57.916 37.8 58 ;
    END
  END dout[122]
  PIN dout[123]
    DIRECTION OUTPUT ;
    USE SIGNAL ;
    PORT
      LAYER M7 ;
        RECT  43.84 57.931 43.872 58 ;
    END
  END dout[123]
  PIN dout[124]
    DIRECTION OUTPUT ;
    USE SIGNAL ;
    PORT
      LAYER M5 ;
        RECT  46.992 57.916 47.016 58 ;
    END
  END dout[124]
  PIN dout[125]
    DIRECTION OUTPUT ;
    USE SIGNAL ;
    PORT
      LAYER M7 ;
        RECT  41.28 57.931 41.312 58 ;
    END
  END dout[125]
  PIN dout[126]
    DIRECTION OUTPUT ;
    USE SIGNAL ;
    PORT
      LAYER M7 ;
        RECT  41.856 57.931 41.888 58 ;
    END
  END dout[126]
  PIN dout[127]
    DIRECTION OUTPUT ;
    USE SIGNAL ;
    PORT
      LAYER M7 ;
        RECT  33.728 57.931 33.76 58 ;
    END
  END dout[127]
  PIN dout[128]
    DIRECTION OUTPUT ;
    USE SIGNAL ;
    PORT
      LAYER M5 ;
        RECT  37.248 57.916 37.272 58 ;
    END
  END dout[128]
  PIN dout[129]
    DIRECTION OUTPUT ;
    USE SIGNAL ;
    PORT
      LAYER M5 ;
        RECT  35.568 57.916 35.592 58 ;
    END
  END dout[129]
  PIN dout[12]
    DIRECTION OUTPUT ;
    USE SIGNAL ;
    PORT
      LAYER M7 ;
        RECT  78.656 57.931 78.688 58 ;
    END
  END dout[12]
  PIN dout[130]
    DIRECTION OUTPUT ;
    USE SIGNAL ;
    PORT
      LAYER M5 ;
        RECT  11.856 57.916 11.88 58 ;
    END
  END dout[130]
  PIN dout[131]
    DIRECTION OUTPUT ;
    USE SIGNAL ;
    PORT
      LAYER M7 ;
        RECT  40.064 57.931 40.096 58 ;
    END
  END dout[131]
  PIN dout[132]
    DIRECTION OUTPUT ;
    USE SIGNAL ;
    PORT
      LAYER M5 ;
        RECT  9.168 57.916 9.192 58 ;
    END
  END dout[132]
  PIN dout[133]
    DIRECTION OUTPUT ;
    USE SIGNAL ;
    PORT
      LAYER M7 ;
        RECT  32.896 57.931 32.928 58 ;
    END
  END dout[133]
  PIN dout[134]
    DIRECTION OUTPUT ;
    USE SIGNAL ;
    PORT
      LAYER M5 ;
        RECT  10.56 57.916 10.584 58 ;
    END
  END dout[134]
  PIN dout[135]
    DIRECTION OUTPUT ;
    USE SIGNAL ;
    PORT
      LAYER M5 ;
        RECT  13.824 57.916 13.848 58 ;
    END
  END dout[135]
  PIN dout[136]
    DIRECTION OUTPUT ;
    USE SIGNAL ;
    PORT
      LAYER M5 ;
        RECT  8.832 57.916 8.856 58 ;
    END
  END dout[136]
  PIN dout[137]
    DIRECTION OUTPUT ;
    USE SIGNAL ;
    PORT
      LAYER M5 ;
        RECT  27.984 57.916 28.008 58 ;
    END
  END dout[137]
  PIN dout[138]
    DIRECTION OUTPUT ;
    USE SIGNAL ;
    PORT
      LAYER M7 ;
        RECT  5.568 57.931 5.6 58 ;
    END
  END dout[138]
  PIN dout[139]
    DIRECTION OUTPUT ;
    USE SIGNAL ;
    PORT
      LAYER M5 ;
        RECT  11.088 57.916 11.112 58 ;
    END
  END dout[139]
  PIN dout[13]
    DIRECTION OUTPUT ;
    USE SIGNAL ;
    PORT
      LAYER M5 ;
        RECT  89.184 57.916 89.208 58 ;
    END
  END dout[13]
  PIN dout[140]
    DIRECTION OUTPUT ;
    USE SIGNAL ;
    PORT
      LAYER M5 ;
        RECT  1.584 57.916 1.608 58 ;
    END
  END dout[140]
  PIN dout[141]
    DIRECTION OUTPUT ;
    USE SIGNAL ;
    PORT
      LAYER M7 ;
        RECT  40.192 57.931 40.224 58 ;
    END
  END dout[141]
  PIN dout[142]
    DIRECTION OUTPUT ;
    USE SIGNAL ;
    PORT
      LAYER M7 ;
        RECT  4.224 57.931 4.256 58 ;
    END
  END dout[142]
  PIN dout[143]
    DIRECTION OUTPUT ;
    USE SIGNAL ;
    PORT
      LAYER M7 ;
        RECT  6.272 57.931 6.304 58 ;
    END
  END dout[143]
  PIN dout[144]
    DIRECTION OUTPUT ;
    USE SIGNAL ;
    PORT
      LAYER M5 ;
        RECT  2.256 57.916 2.28 58 ;
    END
  END dout[144]
  PIN dout[145]
    DIRECTION OUTPUT ;
    USE SIGNAL ;
    PORT
      LAYER M5 ;
        RECT  34.512 57.916 34.536 58 ;
    END
  END dout[145]
  PIN dout[146]
    DIRECTION OUTPUT ;
    USE SIGNAL ;
    PORT
      LAYER M7 ;
        RECT  6.656 57.931 6.688 58 ;
    END
  END dout[146]
  PIN dout[147]
    DIRECTION OUTPUT ;
    USE SIGNAL ;
    PORT
      LAYER M7 ;
        RECT  5.632 57.931 5.664 58 ;
    END
  END dout[147]
  PIN dout[148]
    DIRECTION OUTPUT ;
    USE SIGNAL ;
    PORT
      LAYER M5 ;
        RECT  7.632 57.916 7.656 58 ;
    END
  END dout[148]
  PIN dout[149]
    DIRECTION OUTPUT ;
    USE SIGNAL ;
    PORT
      LAYER M7 ;
        RECT  4.736 57.931 4.768 58 ;
    END
  END dout[149]
  PIN dout[14]
    DIRECTION OUTPUT ;
    USE SIGNAL ;
    PORT
      LAYER M7 ;
        RECT  81.152 57.931 81.184 58 ;
    END
  END dout[14]
  PIN dout[150]
    DIRECTION OUTPUT ;
    USE SIGNAL ;
    PORT
      LAYER M7 ;
        RECT  32.32 57.931 32.352 58 ;
    END
  END dout[150]
  PIN dout[151]
    DIRECTION OUTPUT ;
    USE SIGNAL ;
    PORT
      LAYER M5 ;
        RECT  40.08 57.916 40.104 58 ;
    END
  END dout[151]
  PIN dout[152]
    DIRECTION OUTPUT ;
    USE SIGNAL ;
    PORT
      LAYER M7 ;
        RECT  29.76 57.931 29.792 58 ;
    END
  END dout[152]
  PIN dout[153]
    DIRECTION OUTPUT ;
    USE SIGNAL ;
    PORT
      LAYER M7 ;
        RECT  30.208 57.931 30.24 58 ;
    END
  END dout[153]
  PIN dout[154]
    DIRECTION OUTPUT ;
    USE SIGNAL ;
    PORT
      LAYER M5 ;
        RECT  28.8 57.916 28.824 58 ;
    END
  END dout[154]
  PIN dout[155]
    DIRECTION OUTPUT ;
    USE SIGNAL ;
    PORT
      LAYER M7 ;
        RECT  30.592 57.931 30.624 58 ;
    END
  END dout[155]
  PIN dout[156]
    DIRECTION OUTPUT ;
    USE SIGNAL ;
    PORT
      LAYER M7 ;
        RECT  32.128 57.931 32.16 58 ;
    END
  END dout[156]
  PIN dout[157]
    DIRECTION OUTPUT ;
    USE SIGNAL ;
    PORT
      LAYER M5 ;
        RECT  35.088 57.916 35.112 58 ;
    END
  END dout[157]
  PIN dout[158]
    DIRECTION OUTPUT ;
    USE SIGNAL ;
    PORT
      LAYER M5 ;
        RECT  24.672 57.916 24.696 58 ;
    END
  END dout[158]
  PIN dout[159]
    DIRECTION OUTPUT ;
    USE SIGNAL ;
    PORT
      LAYER M5 ;
        RECT  25.872 57.916 25.896 58 ;
    END
  END dout[159]
  PIN dout[15]
    DIRECTION OUTPUT ;
    USE SIGNAL ;
    PORT
      LAYER M5 ;
        RECT  84.624 57.916 84.648 58 ;
    END
  END dout[15]
  PIN dout[160]
    DIRECTION OUTPUT ;
    USE SIGNAL ;
    PORT
      LAYER M7 ;
        RECT  41.024 57.931 41.056 58 ;
    END
  END dout[160]
  PIN dout[161]
    DIRECTION OUTPUT ;
    USE SIGNAL ;
    PORT
      LAYER M5 ;
        RECT  35.28 57.916 35.304 58 ;
    END
  END dout[161]
  PIN dout[162]
    DIRECTION OUTPUT ;
    USE SIGNAL ;
    PORT
      LAYER M7 ;
        RECT  31.36 57.931 31.392 58 ;
    END
  END dout[162]
  PIN dout[163]
    DIRECTION OUTPUT ;
    USE SIGNAL ;
    PORT
      LAYER M5 ;
        RECT  45.888 57.916 45.912 58 ;
    END
  END dout[163]
  PIN dout[164]
    DIRECTION OUTPUT ;
    USE SIGNAL ;
    PORT
      LAYER M7 ;
        RECT  32.704 57.931 32.736 58 ;
    END
  END dout[164]
  PIN dout[165]
    DIRECTION OUTPUT ;
    USE SIGNAL ;
    PORT
      LAYER M5 ;
        RECT  28.368 57.916 28.392 58 ;
    END
  END dout[165]
  PIN dout[166]
    DIRECTION OUTPUT ;
    USE SIGNAL ;
    PORT
      LAYER M5 ;
        RECT  26.976 57.916 27 58 ;
    END
  END dout[166]
  PIN dout[167]
    DIRECTION OUTPUT ;
    USE SIGNAL ;
    PORT
      LAYER M5 ;
        RECT  37.104 57.916 37.128 58 ;
    END
  END dout[167]
  PIN dout[168]
    DIRECTION OUTPUT ;
    USE SIGNAL ;
    PORT
      LAYER M5 ;
        RECT  36.288 57.916 36.312 58 ;
    END
  END dout[168]
  PIN dout[169]
    DIRECTION OUTPUT ;
    USE SIGNAL ;
    PORT
      LAYER M5 ;
        RECT  2.496 57.916 2.52 58 ;
    END
  END dout[169]
  PIN dout[16]
    DIRECTION OUTPUT ;
    USE SIGNAL ;
    PORT
      LAYER M7 ;
        RECT  81.728 57.931 81.76 58 ;
    END
  END dout[16]
  PIN dout[170]
    DIRECTION OUTPUT ;
    USE SIGNAL ;
    PORT
      LAYER M5 ;
        RECT  14.784 57.916 14.808 58 ;
    END
  END dout[170]
  PIN dout[171]
    DIRECTION OUTPUT ;
    USE SIGNAL ;
    PORT
      LAYER M7 ;
        RECT  42.688 57.931 42.72 58 ;
    END
  END dout[171]
  PIN dout[172]
    DIRECTION OUTPUT ;
    USE SIGNAL ;
    PORT
      LAYER M5 ;
        RECT  39.072 57.916 39.096 58 ;
    END
  END dout[172]
  PIN dout[173]
    DIRECTION OUTPUT ;
    USE SIGNAL ;
    PORT
      LAYER M5 ;
        RECT  1.824 57.916 1.848 58 ;
    END
  END dout[173]
  PIN dout[174]
    DIRECTION OUTPUT ;
    USE SIGNAL ;
    PORT
      LAYER M5 ;
        RECT  40.128 57.916 40.152 58 ;
    END
  END dout[174]
  PIN dout[175]
    DIRECTION OUTPUT ;
    USE SIGNAL ;
    PORT
      LAYER M5 ;
        RECT  38.832 57.916 38.856 58 ;
    END
  END dout[175]
  PIN dout[176]
    DIRECTION OUTPUT ;
    USE SIGNAL ;
    PORT
      LAYER M5 ;
        RECT  38.4 57.916 38.424 58 ;
    END
  END dout[176]
  PIN dout[177]
    DIRECTION OUTPUT ;
    USE SIGNAL ;
    PORT
      LAYER M7 ;
        RECT  33.664 57.931 33.696 58 ;
    END
  END dout[177]
  PIN dout[178]
    DIRECTION OUTPUT ;
    USE SIGNAL ;
    PORT
      LAYER M7 ;
        RECT  40.384 57.931 40.416 58 ;
    END
  END dout[178]
  PIN dout[179]
    DIRECTION OUTPUT ;
    USE SIGNAL ;
    PORT
      LAYER M5 ;
        RECT  2.208 57.916 2.232 58 ;
    END
  END dout[179]
  PIN dout[17]
    DIRECTION OUTPUT ;
    USE SIGNAL ;
    PORT
      LAYER M5 ;
        RECT  82.224 57.916 82.248 58 ;
    END
  END dout[17]
  PIN dout[180]
    DIRECTION OUTPUT ;
    USE SIGNAL ;
    PORT
      LAYER M5 ;
        RECT  38.064 57.916 38.088 58 ;
    END
  END dout[180]
  PIN dout[181]
    DIRECTION OUTPUT ;
    USE SIGNAL ;
    PORT
      LAYER M5 ;
        RECT  38.688 57.916 38.712 58 ;
    END
  END dout[181]
  PIN dout[182]
    DIRECTION OUTPUT ;
    USE SIGNAL ;
    PORT
      LAYER M5 ;
        RECT  37.92 57.916 37.944 58 ;
    END
  END dout[182]
  PIN dout[183]
    DIRECTION OUTPUT ;
    USE SIGNAL ;
    PORT
      LAYER M5 ;
        RECT  39.84 57.916 39.864 58 ;
    END
  END dout[183]
  PIN dout[184]
    DIRECTION OUTPUT ;
    USE SIGNAL ;
    PORT
      LAYER M5 ;
        RECT  40.416 57.916 40.44 58 ;
    END
  END dout[184]
  PIN dout[185]
    DIRECTION OUTPUT ;
    USE SIGNAL ;
    PORT
      LAYER M7 ;
        RECT  30.336 57.931 30.368 58 ;
    END
  END dout[185]
  PIN dout[186]
    DIRECTION OUTPUT ;
    USE SIGNAL ;
    PORT
      LAYER M5 ;
        RECT  14.4 57.916 14.424 58 ;
    END
  END dout[186]
  PIN dout[187]
    DIRECTION OUTPUT ;
    USE SIGNAL ;
    PORT
      LAYER M5 ;
        RECT  36.768 57.916 36.792 58 ;
    END
  END dout[187]
  PIN dout[188]
    DIRECTION OUTPUT ;
    USE SIGNAL ;
    PORT
      LAYER M7 ;
        RECT  18.56 57.931 18.592 58 ;
    END
  END dout[188]
  PIN dout[189]
    DIRECTION OUTPUT ;
    USE SIGNAL ;
    PORT
      LAYER M5 ;
        RECT  24.144 57.916 24.168 58 ;
    END
  END dout[189]
  PIN dout[18]
    DIRECTION OUTPUT ;
    USE SIGNAL ;
    PORT
      LAYER M7 ;
        RECT  79.104 57.931 79.136 58 ;
    END
  END dout[18]
  PIN dout[190]
    DIRECTION OUTPUT ;
    USE SIGNAL ;
    PORT
      LAYER M7 ;
        RECT  33.088 57.931 33.12 58 ;
    END
  END dout[190]
  PIN dout[191]
    DIRECTION OUTPUT ;
    USE SIGNAL ;
    PORT
      LAYER M7 ;
        RECT  33.472 57.931 33.504 58 ;
    END
  END dout[191]
  PIN dout[192]
    DIRECTION OUTPUT ;
    USE SIGNAL ;
    PORT
      LAYER M5 ;
        RECT  55.392 57.916 55.416 58 ;
    END
  END dout[192]
  PIN dout[193]
    DIRECTION OUTPUT ;
    USE SIGNAL ;
    PORT
      LAYER M5 ;
        RECT  78.192 57.916 78.216 58 ;
    END
  END dout[193]
  PIN dout[194]
    DIRECTION OUTPUT ;
    USE SIGNAL ;
    PORT
      LAYER M5 ;
        RECT  61.2 57.916 61.224 58 ;
    END
  END dout[194]
  PIN dout[195]
    DIRECTION OUTPUT ;
    USE SIGNAL ;
    PORT
      LAYER M5 ;
        RECT  82.272 57.916 82.296 58 ;
    END
  END dout[195]
  PIN dout[196]
    DIRECTION OUTPUT ;
    USE SIGNAL ;
    PORT
      LAYER M5 ;
        RECT  48.192 57.916 48.216 58 ;
    END
  END dout[196]
  PIN dout[197]
    DIRECTION OUTPUT ;
    USE SIGNAL ;
    PORT
      LAYER M5 ;
        RECT  66.432 57.916 66.456 58 ;
    END
  END dout[197]
  PIN dout[198]
    DIRECTION OUTPUT ;
    USE SIGNAL ;
    PORT
      LAYER M5 ;
        RECT  55.152 57.916 55.176 58 ;
    END
  END dout[198]
  PIN dout[199]
    DIRECTION OUTPUT ;
    USE SIGNAL ;
    PORT
      LAYER M5 ;
        RECT  63.648 57.916 63.672 58 ;
    END
  END dout[199]
  PIN dout[19]
    DIRECTION OUTPUT ;
    USE SIGNAL ;
    PORT
      LAYER M5 ;
        RECT  83.616 57.916 83.64 58 ;
    END
  END dout[19]
  PIN dout[1]
    DIRECTION OUTPUT ;
    USE SIGNAL ;
    PORT
      LAYER M5 ;
        RECT  86.688 57.916 86.712 58 ;
    END
  END dout[1]
  PIN dout[200]
    DIRECTION OUTPUT ;
    USE SIGNAL ;
    PORT
      LAYER M7 ;
        RECT  59.904 57.931 59.936 58 ;
    END
  END dout[200]
  PIN dout[201]
    DIRECTION OUTPUT ;
    USE SIGNAL ;
    PORT
      LAYER M7 ;
        RECT  57.216 57.931 57.248 58 ;
    END
  END dout[201]
  PIN dout[202]
    DIRECTION OUTPUT ;
    USE SIGNAL ;
    PORT
      LAYER M5 ;
        RECT  53.424 57.916 53.448 58 ;
    END
  END dout[202]
  PIN dout[203]
    DIRECTION OUTPUT ;
    USE SIGNAL ;
    PORT
      LAYER M7 ;
        RECT  68.096 57.931 68.128 58 ;
    END
  END dout[203]
  PIN dout[204]
    DIRECTION OUTPUT ;
    USE SIGNAL ;
    PORT
      LAYER M5 ;
        RECT  51.744 57.916 51.768 58 ;
    END
  END dout[204]
  PIN dout[205]
    DIRECTION OUTPUT ;
    USE SIGNAL ;
    PORT
      LAYER M7 ;
        RECT  70.656 57.931 70.688 58 ;
    END
  END dout[205]
  PIN dout[206]
    DIRECTION OUTPUT ;
    USE SIGNAL ;
    PORT
      LAYER M7 ;
        RECT  69.504 57.931 69.536 58 ;
    END
  END dout[206]
  PIN dout[207]
    DIRECTION OUTPUT ;
    USE SIGNAL ;
    PORT
      LAYER M5 ;
        RECT  76.944 57.916 76.968 58 ;
    END
  END dout[207]
  PIN dout[208]
    DIRECTION OUTPUT ;
    USE SIGNAL ;
    PORT
      LAYER M5 ;
        RECT  72.864 57.916 72.888 58 ;
    END
  END dout[208]
  PIN dout[209]
    DIRECTION OUTPUT ;
    USE SIGNAL ;
    PORT
      LAYER M5 ;
        RECT  75.12 57.916 75.144 58 ;
    END
  END dout[209]
  PIN dout[20]
    DIRECTION OUTPUT ;
    USE SIGNAL ;
    PORT
      LAYER M5 ;
        RECT  84.528 57.916 84.552 58 ;
    END
  END dout[20]
  PIN dout[210]
    DIRECTION OUTPUT ;
    USE SIGNAL ;
    PORT
      LAYER M5 ;
        RECT  76.608 57.916 76.632 58 ;
    END
  END dout[210]
  PIN dout[211]
    DIRECTION OUTPUT ;
    USE SIGNAL ;
    PORT
      LAYER M5 ;
        RECT  76.08 57.916 76.104 58 ;
    END
  END dout[211]
  PIN dout[212]
    DIRECTION OUTPUT ;
    USE SIGNAL ;
    PORT
      LAYER M5 ;
        RECT  73.296 57.916 73.32 58 ;
    END
  END dout[212]
  PIN dout[213]
    DIRECTION OUTPUT ;
    USE SIGNAL ;
    PORT
      LAYER M5 ;
        RECT  80.544 57.916 80.568 58 ;
    END
  END dout[213]
  PIN dout[214]
    DIRECTION OUTPUT ;
    USE SIGNAL ;
    PORT
      LAYER M7 ;
        RECT  81.792 57.931 81.824 58 ;
    END
  END dout[214]
  PIN dout[215]
    DIRECTION OUTPUT ;
    USE SIGNAL ;
    PORT
      LAYER M5 ;
        RECT  86.976 57.916 87 58 ;
    END
  END dout[215]
  PIN dout[216]
    DIRECTION OUTPUT ;
    USE SIGNAL ;
    PORT
      LAYER M7 ;
        RECT  83.392 57.931 83.424 58 ;
    END
  END dout[216]
  PIN dout[217]
    DIRECTION OUTPUT ;
    USE SIGNAL ;
    PORT
      LAYER M5 ;
        RECT  87.312 57.916 87.336 58 ;
    END
  END dout[217]
  PIN dout[218]
    DIRECTION OUTPUT ;
    USE SIGNAL ;
    PORT
      LAYER M5 ;
        RECT  87.744 57.916 87.768 58 ;
    END
  END dout[218]
  PIN dout[219]
    DIRECTION OUTPUT ;
    USE SIGNAL ;
    PORT
      LAYER M5 ;
        RECT  83.04 57.916 83.064 58 ;
    END
  END dout[219]
  PIN dout[21]
    DIRECTION OUTPUT ;
    USE SIGNAL ;
    PORT
      LAYER M5 ;
        RECT  82.992 57.916 83.016 58 ;
    END
  END dout[21]
  PIN dout[220]
    DIRECTION OUTPUT ;
    USE SIGNAL ;
    PORT
      LAYER M5 ;
        RECT  85.728 57.916 85.752 58 ;
    END
  END dout[220]
  PIN dout[221]
    DIRECTION OUTPUT ;
    USE SIGNAL ;
    PORT
      LAYER M5 ;
        RECT  86.448 57.916 86.472 58 ;
    END
  END dout[221]
  PIN dout[222]
    DIRECTION OUTPUT ;
    USE SIGNAL ;
    PORT
      LAYER M5 ;
        RECT  81.168 57.916 81.192 58 ;
    END
  END dout[222]
  PIN dout[223]
    DIRECTION OUTPUT ;
    USE SIGNAL ;
    PORT
      LAYER M5 ;
        RECT  82.608 57.916 82.632 58 ;
    END
  END dout[223]
  PIN dout[224]
    DIRECTION OUTPUT ;
    USE SIGNAL ;
    PORT
      LAYER M5 ;
        RECT  86.16 57.916 86.184 58 ;
    END
  END dout[224]
  PIN dout[225]
    DIRECTION OUTPUT ;
    USE SIGNAL ;
    PORT
      LAYER M5 ;
        RECT  84.432 57.916 84.456 58 ;
    END
  END dout[225]
  PIN dout[226]
    DIRECTION OUTPUT ;
    USE SIGNAL ;
    PORT
      LAYER M5 ;
        RECT  84.72 57.916 84.744 58 ;
    END
  END dout[226]
  PIN dout[227]
    DIRECTION OUTPUT ;
    USE SIGNAL ;
    PORT
      LAYER M5 ;
        RECT  88.512 57.916 88.536 58 ;
    END
  END dout[227]
  PIN dout[228]
    DIRECTION OUTPUT ;
    USE SIGNAL ;
    PORT
      LAYER M5 ;
        RECT  84.96 57.916 84.984 58 ;
    END
  END dout[228]
  PIN dout[229]
    DIRECTION OUTPUT ;
    USE SIGNAL ;
    PORT
      LAYER M5 ;
        RECT  83.472 57.916 83.496 58 ;
    END
  END dout[229]
  PIN dout[22]
    DIRECTION OUTPUT ;
    USE SIGNAL ;
    PORT
      LAYER M5 ;
        RECT  78.672 57.916 78.696 58 ;
    END
  END dout[22]
  PIN dout[230]
    DIRECTION OUTPUT ;
    USE SIGNAL ;
    PORT
      LAYER M5 ;
        RECT  83.712 57.916 83.736 58 ;
    END
  END dout[230]
  PIN dout[231]
    DIRECTION OUTPUT ;
    USE SIGNAL ;
    PORT
      LAYER M5 ;
        RECT  88.224 57.916 88.248 58 ;
    END
  END dout[231]
  PIN dout[232]
    DIRECTION OUTPUT ;
    USE SIGNAL ;
    PORT
      LAYER M5 ;
        RECT  81.12 57.916 81.144 58 ;
    END
  END dout[232]
  PIN dout[233]
    DIRECTION OUTPUT ;
    USE SIGNAL ;
    PORT
      LAYER M5 ;
        RECT  82.704 57.916 82.728 58 ;
    END
  END dout[233]
  PIN dout[234]
    DIRECTION OUTPUT ;
    USE SIGNAL ;
    PORT
      LAYER M7 ;
        RECT  83.968 57.931 84 58 ;
    END
  END dout[234]
  PIN dout[235]
    DIRECTION OUTPUT ;
    USE SIGNAL ;
    PORT
      LAYER M5 ;
        RECT  88.608 57.916 88.632 58 ;
    END
  END dout[235]
  PIN dout[236]
    DIRECTION OUTPUT ;
    USE SIGNAL ;
    PORT
      LAYER M5 ;
        RECT  81.888 57.916 81.912 58 ;
    END
  END dout[236]
  PIN dout[237]
    DIRECTION OUTPUT ;
    USE SIGNAL ;
    PORT
      LAYER M5 ;
        RECT  83.28 57.916 83.304 58 ;
    END
  END dout[237]
  PIN dout[238]
    DIRECTION OUTPUT ;
    USE SIGNAL ;
    PORT
      LAYER M5 ;
        RECT  85.968 57.916 85.992 58 ;
    END
  END dout[238]
  PIN dout[239]
    DIRECTION OUTPUT ;
    USE SIGNAL ;
    PORT
      LAYER M5 ;
        RECT  83.424 57.916 83.448 58 ;
    END
  END dout[239]
  PIN dout[23]
    DIRECTION OUTPUT ;
    USE SIGNAL ;
    PORT
      LAYER M7 ;
        RECT  80.96 57.931 80.992 58 ;
    END
  END dout[23]
  PIN dout[240]
    DIRECTION OUTPUT ;
    USE SIGNAL ;
    PORT
      LAYER M7 ;
        RECT  84.096 57.931 84.128 58 ;
    END
  END dout[240]
  PIN dout[241]
    DIRECTION OUTPUT ;
    USE SIGNAL ;
    PORT
      LAYER M7 ;
        RECT  83.84 57.931 83.872 58 ;
    END
  END dout[241]
  PIN dout[242]
    DIRECTION OUTPUT ;
    USE SIGNAL ;
    PORT
      LAYER M5 ;
        RECT  86.304 57.916 86.328 58 ;
    END
  END dout[242]
  PIN dout[243]
    DIRECTION OUTPUT ;
    USE SIGNAL ;
    PORT
      LAYER M5 ;
        RECT  66.336 57.916 66.36 58 ;
    END
  END dout[243]
  PIN dout[244]
    DIRECTION OUTPUT ;
    USE SIGNAL ;
    PORT
      LAYER M7 ;
        RECT  81.856 57.931 81.888 58 ;
    END
  END dout[244]
  PIN dout[245]
    DIRECTION OUTPUT ;
    USE SIGNAL ;
    PORT
      LAYER M5 ;
        RECT  50.304 57.916 50.328 58 ;
    END
  END dout[245]
  PIN dout[246]
    DIRECTION OUTPUT ;
    USE SIGNAL ;
    PORT
      LAYER M5 ;
        RECT  62.16 57.916 62.184 58 ;
    END
  END dout[246]
  PIN dout[247]
    DIRECTION OUTPUT ;
    USE SIGNAL ;
    PORT
      LAYER M5 ;
        RECT  50.112 57.916 50.136 58 ;
    END
  END dout[247]
  PIN dout[248]
    DIRECTION OUTPUT ;
    USE SIGNAL ;
    PORT
      LAYER M7 ;
        RECT  68.672 57.931 68.704 58 ;
    END
  END dout[248]
  PIN dout[249]
    DIRECTION OUTPUT ;
    USE SIGNAL ;
    PORT
      LAYER M7 ;
        RECT  42.368 57.931 42.4 58 ;
    END
  END dout[249]
  PIN dout[24]
    DIRECTION OUTPUT ;
    USE SIGNAL ;
    PORT
      LAYER M7 ;
        RECT  83.712 57.931 83.744 58 ;
    END
  END dout[24]
  PIN dout[250]
    DIRECTION OUTPUT ;
    USE SIGNAL ;
    PORT
      LAYER M5 ;
        RECT  46.464 57.916 46.488 58 ;
    END
  END dout[250]
  PIN dout[251]
    DIRECTION OUTPUT ;
    USE SIGNAL ;
    PORT
      LAYER M7 ;
        RECT  42.24 57.931 42.272 58 ;
    END
  END dout[251]
  PIN dout[252]
    DIRECTION OUTPUT ;
    USE SIGNAL ;
    PORT
      LAYER M7 ;
        RECT  43.968 57.931 44 58 ;
    END
  END dout[252]
  PIN dout[253]
    DIRECTION OUTPUT ;
    USE SIGNAL ;
    PORT
      LAYER M5 ;
        RECT  86.496 57.916 86.52 58 ;
    END
  END dout[253]
  PIN dout[254]
    DIRECTION OUTPUT ;
    USE SIGNAL ;
    PORT
      LAYER M5 ;
        RECT  48.864 57.916 48.888 58 ;
    END
  END dout[254]
  PIN dout[255]
    DIRECTION OUTPUT ;
    USE SIGNAL ;
    PORT
      LAYER M5 ;
        RECT  45.984 57.916 46.008 58 ;
    END
  END dout[255]
  PIN dout[256]
    DIRECTION OUTPUT ;
    USE SIGNAL ;
    PORT
      LAYER M5 ;
        RECT  87.888 57.916 87.912 58 ;
    END
  END dout[256]
  PIN dout[257]
    DIRECTION OUTPUT ;
    USE SIGNAL ;
    PORT
      LAYER M7 ;
        RECT  83.904 57.931 83.936 58 ;
    END
  END dout[257]
  PIN dout[258]
    DIRECTION OUTPUT ;
    USE SIGNAL ;
    PORT
      LAYER M5 ;
        RECT  87.12 57.916 87.144 58 ;
    END
  END dout[258]
  PIN dout[259]
    DIRECTION OUTPUT ;
    USE SIGNAL ;
    PORT
      LAYER M7 ;
        RECT  82.496 57.931 82.528 58 ;
    END
  END dout[259]
  PIN dout[25]
    DIRECTION OUTPUT ;
    USE SIGNAL ;
    PORT
      LAYER M5 ;
        RECT  82.512 57.916 82.536 58 ;
    END
  END dout[25]
  PIN dout[260]
    DIRECTION OUTPUT ;
    USE SIGNAL ;
    PORT
      LAYER M5 ;
        RECT  84.768 57.916 84.792 58 ;
    END
  END dout[260]
  PIN dout[261]
    DIRECTION OUTPUT ;
    USE SIGNAL ;
    PORT
      LAYER M5 ;
        RECT  88.08 57.916 88.104 58 ;
    END
  END dout[261]
  PIN dout[262]
    DIRECTION OUTPUT ;
    USE SIGNAL ;
    PORT
      LAYER M5 ;
        RECT  82.752 57.916 82.776 58 ;
    END
  END dout[262]
  PIN dout[263]
    DIRECTION OUTPUT ;
    USE SIGNAL ;
    PORT
      LAYER M7 ;
        RECT  81.216 57.931 81.248 58 ;
    END
  END dout[263]
  PIN dout[264]
    DIRECTION OUTPUT ;
    USE SIGNAL ;
    PORT
      LAYER M5 ;
        RECT  86.88 57.916 86.904 58 ;
    END
  END dout[264]
  PIN dout[265]
    DIRECTION OUTPUT ;
    USE SIGNAL ;
    PORT
      LAYER M7 ;
        RECT  78.4 57.931 78.432 58 ;
    END
  END dout[265]
  PIN dout[266]
    DIRECTION OUTPUT ;
    USE SIGNAL ;
    PORT
      LAYER M7 ;
        RECT  84.288 57.931 84.32 58 ;
    END
  END dout[266]
  PIN dout[267]
    DIRECTION OUTPUT ;
    USE SIGNAL ;
    PORT
      LAYER M5 ;
        RECT  88.176 57.916 88.2 58 ;
    END
  END dout[267]
  PIN dout[268]
    DIRECTION OUTPUT ;
    USE SIGNAL ;
    PORT
      LAYER M5 ;
        RECT  82.32 57.916 82.344 58 ;
    END
  END dout[268]
  PIN dout[269]
    DIRECTION OUTPUT ;
    USE SIGNAL ;
    PORT
      LAYER M5 ;
        RECT  86.544 57.916 86.568 58 ;
    END
  END dout[269]
  PIN dout[26]
    DIRECTION OUTPUT ;
    USE SIGNAL ;
    PORT
      LAYER M5 ;
        RECT  78.48 57.916 78.504 58 ;
    END
  END dout[26]
  PIN dout[270]
    DIRECTION OUTPUT ;
    USE SIGNAL ;
    PORT
      LAYER M5 ;
        RECT  88.416 57.916 88.44 58 ;
    END
  END dout[270]
  PIN dout[271]
    DIRECTION OUTPUT ;
    USE SIGNAL ;
    PORT
      LAYER M5 ;
        RECT  85.392 57.916 85.416 58 ;
    END
  END dout[271]
  PIN dout[272]
    DIRECTION OUTPUT ;
    USE SIGNAL ;
    PORT
      LAYER M5 ;
        RECT  81.072 57.916 81.096 58 ;
    END
  END dout[272]
  PIN dout[273]
    DIRECTION OUTPUT ;
    USE SIGNAL ;
    PORT
      LAYER M5 ;
        RECT  87.504 57.916 87.528 58 ;
    END
  END dout[273]
  PIN dout[274]
    DIRECTION OUTPUT ;
    USE SIGNAL ;
    PORT
      LAYER M5 ;
        RECT  83.856 57.916 83.88 58 ;
    END
  END dout[274]
  PIN dout[275]
    DIRECTION OUTPUT ;
    USE SIGNAL ;
    PORT
      LAYER M5 ;
        RECT  88.656 57.916 88.68 58 ;
    END
  END dout[275]
  PIN dout[276]
    DIRECTION OUTPUT ;
    USE SIGNAL ;
    PORT
      LAYER M5 ;
        RECT  80.688 57.916 80.712 58 ;
    END
  END dout[276]
  PIN dout[277]
    DIRECTION OUTPUT ;
    USE SIGNAL ;
    PORT
      LAYER M5 ;
        RECT  85.008 57.916 85.032 58 ;
    END
  END dout[277]
  PIN dout[278]
    DIRECTION OUTPUT ;
    USE SIGNAL ;
    PORT
      LAYER M5 ;
        RECT  87.936 57.916 87.96 58 ;
    END
  END dout[278]
  PIN dout[279]
    DIRECTION OUTPUT ;
    USE SIGNAL ;
    PORT
      LAYER M5 ;
        RECT  85.056 57.916 85.08 58 ;
    END
  END dout[279]
  PIN dout[27]
    DIRECTION OUTPUT ;
    USE SIGNAL ;
    PORT
      LAYER M5 ;
        RECT  78 57.916 78.024 58 ;
    END
  END dout[27]
  PIN dout[280]
    DIRECTION OUTPUT ;
    USE SIGNAL ;
    PORT
      LAYER M7 ;
        RECT  83.52 57.931 83.552 58 ;
    END
  END dout[280]
  PIN dout[281]
    DIRECTION OUTPUT ;
    USE SIGNAL ;
    PORT
      LAYER M5 ;
        RECT  81.024 57.916 81.048 58 ;
    END
  END dout[281]
  PIN dout[282]
    DIRECTION OUTPUT ;
    USE SIGNAL ;
    PORT
      LAYER M7 ;
        RECT  84.48 57.931 84.512 58 ;
    END
  END dout[282]
  PIN dout[283]
    DIRECTION OUTPUT ;
    USE SIGNAL ;
    PORT
      LAYER M5 ;
        RECT  81.648 57.916 81.672 58 ;
    END
  END dout[283]
  PIN dout[284]
    DIRECTION OUTPUT ;
    USE SIGNAL ;
    PORT
      LAYER M7 ;
        RECT  80.128 57.931 80.16 58 ;
    END
  END dout[284]
  PIN dout[285]
    DIRECTION OUTPUT ;
    USE SIGNAL ;
    PORT
      LAYER M5 ;
        RECT  85.296 57.916 85.32 58 ;
    END
  END dout[285]
  PIN dout[286]
    DIRECTION OUTPUT ;
    USE SIGNAL ;
    PORT
      LAYER M5 ;
        RECT  84.48 57.916 84.504 58 ;
    END
  END dout[286]
  PIN dout[287]
    DIRECTION OUTPUT ;
    USE SIGNAL ;
    PORT
      LAYER M7 ;
        RECT  79.552 57.931 79.584 58 ;
    END
  END dout[287]
  PIN dout[288]
    DIRECTION OUTPUT ;
    USE SIGNAL ;
    PORT
      LAYER M7 ;
        RECT  84.352 57.931 84.384 58 ;
    END
  END dout[288]
  PIN dout[289]
    DIRECTION OUTPUT ;
    USE SIGNAL ;
    PORT
      LAYER M7 ;
        RECT  79.488 57.931 79.52 58 ;
    END
  END dout[289]
  PIN dout[28]
    DIRECTION OUTPUT ;
    USE SIGNAL ;
    PORT
      LAYER M5 ;
        RECT  76.272 57.916 76.296 58 ;
    END
  END dout[28]
  PIN dout[290]
    DIRECTION OUTPUT ;
    USE SIGNAL ;
    PORT
      LAYER M7 ;
        RECT  81.536 57.931 81.568 58 ;
    END
  END dout[290]
  PIN dout[291]
    DIRECTION OUTPUT ;
    USE SIGNAL ;
    PORT
      LAYER M5 ;
        RECT  82.944 57.916 82.968 58 ;
    END
  END dout[291]
  PIN dout[292]
    DIRECTION OUTPUT ;
    USE SIGNAL ;
    PORT
      LAYER M7 ;
        RECT  79.808 57.931 79.84 58 ;
    END
  END dout[292]
  PIN dout[293]
    DIRECTION OUTPUT ;
    USE SIGNAL ;
    PORT
      LAYER M5 ;
        RECT  88.128 57.916 88.152 58 ;
    END
  END dout[293]
  PIN dout[294]
    DIRECTION OUTPUT ;
    USE SIGNAL ;
    PORT
      LAYER M7 ;
        RECT  81.088 57.931 81.12 58 ;
    END
  END dout[294]
  PIN dout[295]
    DIRECTION OUTPUT ;
    USE SIGNAL ;
    PORT
      LAYER M5 ;
        RECT  86.016 57.916 86.04 58 ;
    END
  END dout[295]
  PIN dout[296]
    DIRECTION OUTPUT ;
    USE SIGNAL ;
    PORT
      LAYER M7 ;
        RECT  81.6 57.931 81.632 58 ;
    END
  END dout[296]
  PIN dout[297]
    DIRECTION OUTPUT ;
    USE SIGNAL ;
    PORT
      LAYER M5 ;
        RECT  83.904 57.916 83.928 58 ;
    END
  END dout[297]
  PIN dout[298]
    DIRECTION OUTPUT ;
    USE SIGNAL ;
    PORT
      LAYER M7 ;
        RECT  78.72 57.931 78.752 58 ;
    END
  END dout[298]
  PIN dout[299]
    DIRECTION OUTPUT ;
    USE SIGNAL ;
    PORT
      LAYER M5 ;
        RECT  82.848 57.916 82.872 58 ;
    END
  END dout[299]
  PIN dout[29]
    DIRECTION OUTPUT ;
    USE SIGNAL ;
    PORT
      LAYER M5 ;
        RECT  78.336 57.916 78.36 58 ;
    END
  END dout[29]
  PIN dout[2]
    DIRECTION OUTPUT ;
    USE SIGNAL ;
    PORT
      LAYER M7 ;
        RECT  84.544 57.931 84.576 58 ;
    END
  END dout[2]
  PIN dout[300]
    DIRECTION OUTPUT ;
    USE SIGNAL ;
    PORT
      LAYER M5 ;
        RECT  84.576 57.916 84.6 58 ;
    END
  END dout[300]
  PIN dout[301]
    DIRECTION OUTPUT ;
    USE SIGNAL ;
    PORT
      LAYER M5 ;
        RECT  82.416 57.916 82.44 58 ;
    END
  END dout[301]
  PIN dout[302]
    DIRECTION OUTPUT ;
    USE SIGNAL ;
    PORT
      LAYER M5 ;
        RECT  78.384 57.916 78.408 58 ;
    END
  END dout[302]
  PIN dout[303]
    DIRECTION OUTPUT ;
    USE SIGNAL ;
    PORT
      LAYER M7 ;
        RECT  80.512 57.931 80.544 58 ;
    END
  END dout[303]
  PIN dout[304]
    DIRECTION OUTPUT ;
    USE SIGNAL ;
    PORT
      LAYER M7 ;
        RECT  83.456 57.931 83.488 58 ;
    END
  END dout[304]
  PIN dout[305]
    DIRECTION OUTPUT ;
    USE SIGNAL ;
    PORT
      LAYER M5 ;
        RECT  80.976 57.916 81 58 ;
    END
  END dout[305]
  PIN dout[306]
    DIRECTION OUTPUT ;
    USE SIGNAL ;
    PORT
      LAYER M5 ;
        RECT  78.624 57.916 78.648 58 ;
    END
  END dout[306]
  PIN dout[307]
    DIRECTION OUTPUT ;
    USE SIGNAL ;
    PORT
      LAYER M5 ;
        RECT  78.096 57.916 78.12 58 ;
    END
  END dout[307]
  PIN dout[308]
    DIRECTION OUTPUT ;
    USE SIGNAL ;
    PORT
      LAYER M5 ;
        RECT  76.128 57.916 76.152 58 ;
    END
  END dout[308]
  PIN dout[309]
    DIRECTION OUTPUT ;
    USE SIGNAL ;
    PORT
      LAYER M5 ;
        RECT  78.144 57.916 78.168 58 ;
    END
  END dout[309]
  PIN dout[30]
    DIRECTION OUTPUT ;
    USE SIGNAL ;
    PORT
      LAYER M7 ;
        RECT  79.616 57.931 79.648 58 ;
    END
  END dout[30]
  PIN dout[310]
    DIRECTION OUTPUT ;
    USE SIGNAL ;
    PORT
      LAYER M7 ;
        RECT  79.872 57.931 79.904 58 ;
    END
  END dout[310]
  PIN dout[311]
    DIRECTION OUTPUT ;
    USE SIGNAL ;
    PORT
      LAYER M5 ;
        RECT  77.76 57.916 77.784 58 ;
    END
  END dout[311]
  PIN dout[312]
    DIRECTION OUTPUT ;
    USE SIGNAL ;
    PORT
      LAYER M5 ;
        RECT  74.304 57.916 74.328 58 ;
    END
  END dout[312]
  PIN dout[313]
    DIRECTION OUTPUT ;
    USE SIGNAL ;
    PORT
      LAYER M5 ;
        RECT  81.6 57.916 81.624 58 ;
    END
  END dout[313]
  PIN dout[314]
    DIRECTION OUTPUT ;
    USE SIGNAL ;
    PORT
      LAYER M7 ;
        RECT  80.064 57.931 80.096 58 ;
    END
  END dout[314]
  PIN dout[315]
    DIRECTION OUTPUT ;
    USE SIGNAL ;
    PORT
      LAYER M5 ;
        RECT  29.04 57.916 29.064 58 ;
    END
  END dout[315]
  PIN dout[316]
    DIRECTION OUTPUT ;
    USE SIGNAL ;
    PORT
      LAYER M7 ;
        RECT  70.208 57.931 70.24 58 ;
    END
  END dout[316]
  PIN dout[317]
    DIRECTION OUTPUT ;
    USE SIGNAL ;
    PORT
      LAYER M7 ;
        RECT  72.32 57.931 72.352 58 ;
    END
  END dout[317]
  PIN dout[318]
    DIRECTION OUTPUT ;
    USE SIGNAL ;
    PORT
      LAYER M7 ;
        RECT  83.136 57.931 83.168 58 ;
    END
  END dout[318]
  PIN dout[319]
    DIRECTION OUTPUT ;
    USE SIGNAL ;
    PORT
      LAYER M5 ;
        RECT  76.56 57.916 76.584 58 ;
    END
  END dout[319]
  PIN dout[31]
    DIRECTION OUTPUT ;
    USE SIGNAL ;
    PORT
      LAYER M5 ;
        RECT  77.808 57.916 77.832 58 ;
    END
  END dout[31]
  PIN dout[320]
    DIRECTION OUTPUT ;
    USE SIGNAL ;
    PORT
      LAYER M5 ;
        RECT  76.032 57.916 76.056 58 ;
    END
  END dout[320]
  PIN dout[321]
    DIRECTION OUTPUT ;
    USE SIGNAL ;
    PORT
      LAYER M5 ;
        RECT  28.656 57.916 28.68 58 ;
    END
  END dout[321]
  PIN dout[322]
    DIRECTION OUTPUT ;
    USE SIGNAL ;
    PORT
      LAYER M7 ;
        RECT  31.04 57.931 31.072 58 ;
    END
  END dout[322]
  PIN dout[323]
    DIRECTION OUTPUT ;
    USE SIGNAL ;
    PORT
      LAYER M5 ;
        RECT  73.776 57.916 73.8 58 ;
    END
  END dout[323]
  PIN dout[324]
    DIRECTION OUTPUT ;
    USE SIGNAL ;
    PORT
      LAYER M7 ;
        RECT  71.872 57.931 71.904 58 ;
    END
  END dout[324]
  PIN dout[325]
    DIRECTION OUTPUT ;
    USE SIGNAL ;
    PORT
      LAYER M7 ;
        RECT  30.72 57.931 30.752 58 ;
    END
  END dout[325]
  PIN dout[326]
    DIRECTION OUTPUT ;
    USE SIGNAL ;
    PORT
      LAYER M5 ;
        RECT  74.64 57.916 74.664 58 ;
    END
  END dout[326]
  PIN dout[327]
    DIRECTION OUTPUT ;
    USE SIGNAL ;
    PORT
      LAYER M5 ;
        RECT  27.936 57.916 27.96 58 ;
    END
  END dout[327]
  PIN dout[328]
    DIRECTION OUTPUT ;
    USE SIGNAL ;
    PORT
      LAYER M5 ;
        RECT  72.384 57.916 72.408 58 ;
    END
  END dout[328]
  PIN dout[329]
    DIRECTION OUTPUT ;
    USE SIGNAL ;
    PORT
      LAYER M5 ;
        RECT  81.792 57.916 81.816 58 ;
    END
  END dout[329]
  PIN dout[32]
    DIRECTION OUTPUT ;
    USE SIGNAL ;
    PORT
      LAYER M5 ;
        RECT  74.352 57.916 74.376 58 ;
    END
  END dout[32]
  PIN dout[330]
    DIRECTION OUTPUT ;
    USE SIGNAL ;
    PORT
      LAYER M7 ;
        RECT  81.344 57.931 81.376 58 ;
    END
  END dout[330]
  PIN dout[331]
    DIRECTION OUTPUT ;
    USE SIGNAL ;
    PORT
      LAYER M7 ;
        RECT  31.488 57.931 31.52 58 ;
    END
  END dout[331]
  PIN dout[332]
    DIRECTION OUTPUT ;
    USE SIGNAL ;
    PORT
      LAYER M5 ;
        RECT  83.808 57.916 83.832 58 ;
    END
  END dout[332]
  PIN dout[333]
    DIRECTION OUTPUT ;
    USE SIGNAL ;
    PORT
      LAYER M7 ;
        RECT  84.032 57.931 84.064 58 ;
    END
  END dout[333]
  PIN dout[334]
    DIRECTION OUTPUT ;
    USE SIGNAL ;
    PORT
      LAYER M5 ;
        RECT  25.344 57.916 25.368 58 ;
    END
  END dout[334]
  PIN dout[335]
    DIRECTION OUTPUT ;
    USE SIGNAL ;
    PORT
      LAYER M7 ;
        RECT  79.04 57.931 79.072 58 ;
    END
  END dout[335]
  PIN dout[336]
    DIRECTION OUTPUT ;
    USE SIGNAL ;
    PORT
      LAYER M7 ;
        RECT  80.32 57.931 80.352 58 ;
    END
  END dout[336]
  PIN dout[337]
    DIRECTION OUTPUT ;
    USE SIGNAL ;
    PORT
      LAYER M7 ;
        RECT  32.64 57.931 32.672 58 ;
    END
  END dout[337]
  PIN dout[338]
    DIRECTION OUTPUT ;
    USE SIGNAL ;
    PORT
      LAYER M7 ;
        RECT  82.24 57.931 82.272 58 ;
    END
  END dout[338]
  PIN dout[339]
    DIRECTION OUTPUT ;
    USE SIGNAL ;
    PORT
      LAYER M5 ;
        RECT  74.496 57.916 74.52 58 ;
    END
  END dout[339]
  PIN dout[33]
    DIRECTION OUTPUT ;
    USE SIGNAL ;
    PORT
      LAYER M5 ;
        RECT  82.176 57.916 82.2 58 ;
    END
  END dout[33]
  PIN dout[340]
    DIRECTION OUTPUT ;
    USE SIGNAL ;
    PORT
      LAYER M7 ;
        RECT  80.384 57.931 80.416 58 ;
    END
  END dout[340]
  PIN dout[341]
    DIRECTION OUTPUT ;
    USE SIGNAL ;
    PORT
      LAYER M7 ;
        RECT  78.912 57.931 78.944 58 ;
    END
  END dout[341]
  PIN dout[342]
    DIRECTION OUTPUT ;
    USE SIGNAL ;
    PORT
      LAYER M5 ;
        RECT  77.088 57.916 77.112 58 ;
    END
  END dout[342]
  PIN dout[343]
    DIRECTION OUTPUT ;
    USE SIGNAL ;
    PORT
      LAYER M5 ;
        RECT  76.512 57.916 76.536 58 ;
    END
  END dout[343]
  PIN dout[344]
    DIRECTION OUTPUT ;
    USE SIGNAL ;
    PORT
      LAYER M5 ;
        RECT  16.416 57.916 16.44 58 ;
    END
  END dout[344]
  PIN dout[345]
    DIRECTION OUTPUT ;
    USE SIGNAL ;
    PORT
      LAYER M5 ;
        RECT  15.936 57.916 15.96 58 ;
    END
  END dout[345]
  PIN dout[346]
    DIRECTION OUTPUT ;
    USE SIGNAL ;
    PORT
      LAYER M5 ;
        RECT  35.04 57.916 35.064 58 ;
    END
  END dout[346]
  PIN dout[347]
    DIRECTION OUTPUT ;
    USE SIGNAL ;
    PORT
      LAYER M5 ;
        RECT  35.52 57.916 35.544 58 ;
    END
  END dout[347]
  PIN dout[348]
    DIRECTION OUTPUT ;
    USE SIGNAL ;
    PORT
      LAYER M5 ;
        RECT  13.392 57.916 13.416 58 ;
    END
  END dout[348]
  PIN dout[349]
    DIRECTION OUTPUT ;
    USE SIGNAL ;
    PORT
      LAYER M5 ;
        RECT  12.288 57.916 12.312 58 ;
    END
  END dout[349]
  PIN dout[34]
    DIRECTION OUTPUT ;
    USE SIGNAL ;
    PORT
      LAYER M7 ;
        RECT  79.296 57.931 79.328 58 ;
    END
  END dout[34]
  PIN dout[350]
    DIRECTION OUTPUT ;
    USE SIGNAL ;
    PORT
      LAYER M5 ;
        RECT  16.656 57.916 16.68 58 ;
    END
  END dout[350]
  PIN dout[351]
    DIRECTION OUTPUT ;
    USE SIGNAL ;
    PORT
      LAYER M5 ;
        RECT  9.744 57.916 9.768 58 ;
    END
  END dout[351]
  PIN dout[352]
    DIRECTION OUTPUT ;
    USE SIGNAL ;
    PORT
      LAYER M5 ;
        RECT  7.776 57.916 7.8 58 ;
    END
  END dout[352]
  PIN dout[353]
    DIRECTION OUTPUT ;
    USE SIGNAL ;
    PORT
      LAYER M7 ;
        RECT  7.104 57.931 7.136 58 ;
    END
  END dout[353]
  PIN dout[354]
    DIRECTION OUTPUT ;
    USE SIGNAL ;
    PORT
      LAYER M5 ;
        RECT  12.72 57.916 12.744 58 ;
    END
  END dout[354]
  PIN dout[355]
    DIRECTION OUTPUT ;
    USE SIGNAL ;
    PORT
      LAYER M7 ;
        RECT  3.968 57.931 4 58 ;
    END
  END dout[355]
  PIN dout[356]
    DIRECTION OUTPUT ;
    USE SIGNAL ;
    PORT
      LAYER M7 ;
        RECT  6.016 57.931 6.048 58 ;
    END
  END dout[356]
  PIN dout[357]
    DIRECTION OUTPUT ;
    USE SIGNAL ;
    PORT
      LAYER M5 ;
        RECT  9.504 57.916 9.528 58 ;
    END
  END dout[357]
  PIN dout[358]
    DIRECTION OUTPUT ;
    USE SIGNAL ;
    PORT
      LAYER M5 ;
        RECT  2.016 57.916 2.04 58 ;
    END
  END dout[358]
  PIN dout[359]
    DIRECTION OUTPUT ;
    USE SIGNAL ;
    PORT
      LAYER M5 ;
        RECT  2.784 57.916 2.808 58 ;
    END
  END dout[359]
  PIN dout[35]
    DIRECTION OUTPUT ;
    USE SIGNAL ;
    PORT
      LAYER M5 ;
        RECT  28.512 57.916 28.536 58 ;
    END
  END dout[35]
  PIN dout[360]
    DIRECTION OUTPUT ;
    USE SIGNAL ;
    PORT
      LAYER M7 ;
        RECT  4.8 57.931 4.832 58 ;
    END
  END dout[360]
  PIN dout[361]
    DIRECTION OUTPUT ;
    USE SIGNAL ;
    PORT
      LAYER M5 ;
        RECT  1.776 57.916 1.8 58 ;
    END
  END dout[361]
  PIN dout[362]
    DIRECTION OUTPUT ;
    USE SIGNAL ;
    PORT
      LAYER M7 ;
        RECT  5.952 57.931 5.984 58 ;
    END
  END dout[362]
  PIN dout[363]
    DIRECTION OUTPUT ;
    USE SIGNAL ;
    PORT
      LAYER M7 ;
        RECT  4.672 57.931 4.704 58 ;
    END
  END dout[363]
  PIN dout[364]
    DIRECTION OUTPUT ;
    USE SIGNAL ;
    PORT
      LAYER M5 ;
        RECT  8.544 57.916 8.568 58 ;
    END
  END dout[364]
  PIN dout[365]
    DIRECTION OUTPUT ;
    USE SIGNAL ;
    PORT
      LAYER M5 ;
        RECT  10.368 57.916 10.392 58 ;
    END
  END dout[365]
  PIN dout[366]
    DIRECTION OUTPUT ;
    USE SIGNAL ;
    PORT
      LAYER M5 ;
        RECT  7.68 57.916 7.704 58 ;
    END
  END dout[366]
  PIN dout[367]
    DIRECTION OUTPUT ;
    USE SIGNAL ;
    PORT
      LAYER M5 ;
        RECT  2.352 57.916 2.376 58 ;
    END
  END dout[367]
  PIN dout[368]
    DIRECTION OUTPUT ;
    USE SIGNAL ;
    PORT
      LAYER M5 ;
        RECT  8.976 57.916 9 58 ;
    END
  END dout[368]
  PIN dout[369]
    DIRECTION OUTPUT ;
    USE SIGNAL ;
    PORT
      LAYER M5 ;
        RECT  11.136 57.916 11.16 58 ;
    END
  END dout[369]
  PIN dout[36]
    DIRECTION OUTPUT ;
    USE SIGNAL ;
    PORT
      LAYER M7 ;
        RECT  70.272 57.931 70.304 58 ;
    END
  END dout[36]
  PIN dout[370]
    DIRECTION OUTPUT ;
    USE SIGNAL ;
    PORT
      LAYER M5 ;
        RECT  16.224 57.916 16.248 58 ;
    END
  END dout[370]
  PIN dout[371]
    DIRECTION OUTPUT ;
    USE SIGNAL ;
    PORT
      LAYER M7 ;
        RECT  30.784 57.931 30.816 58 ;
    END
  END dout[371]
  PIN dout[372]
    DIRECTION OUTPUT ;
    USE SIGNAL ;
    PORT
      LAYER M5 ;
        RECT  14.304 57.916 14.328 58 ;
    END
  END dout[372]
  PIN dout[373]
    DIRECTION OUTPUT ;
    USE SIGNAL ;
    PORT
      LAYER M5 ;
        RECT  16.032 57.916 16.056 58 ;
    END
  END dout[373]
  PIN dout[374]
    DIRECTION OUTPUT ;
    USE SIGNAL ;
    PORT
      LAYER M5 ;
        RECT  17.616 57.916 17.64 58 ;
    END
  END dout[374]
  PIN dout[375]
    DIRECTION OUTPUT ;
    USE SIGNAL ;
    PORT
      LAYER M5 ;
        RECT  22.992 57.916 23.016 58 ;
    END
  END dout[375]
  PIN dout[376]
    DIRECTION OUTPUT ;
    USE SIGNAL ;
    PORT
      LAYER M5 ;
        RECT  39.744 57.916 39.768 58 ;
    END
  END dout[376]
  PIN dout[377]
    DIRECTION OUTPUT ;
    USE SIGNAL ;
    PORT
      LAYER M5 ;
        RECT  24.336 57.916 24.36 58 ;
    END
  END dout[377]
  PIN dout[378]
    DIRECTION OUTPUT ;
    USE SIGNAL ;
    PORT
      LAYER M7 ;
        RECT  20.16 57.931 20.192 58 ;
    END
  END dout[378]
  PIN dout[379]
    DIRECTION OUTPUT ;
    USE SIGNAL ;
    PORT
      LAYER M7 ;
        RECT  31.744 57.931 31.776 58 ;
    END
  END dout[379]
  PIN dout[37]
    DIRECTION OUTPUT ;
    USE SIGNAL ;
    PORT
      LAYER M5 ;
        RECT  72.336 57.916 72.36 58 ;
    END
  END dout[37]
  PIN dout[380]
    DIRECTION OUTPUT ;
    USE SIGNAL ;
    PORT
      LAYER M7 ;
        RECT  7.04 57.931 7.072 58 ;
    END
  END dout[380]
  PIN dout[381]
    DIRECTION OUTPUT ;
    USE SIGNAL ;
    PORT
      LAYER M7 ;
        RECT  20.48 57.931 20.512 58 ;
    END
  END dout[381]
  PIN dout[382]
    DIRECTION OUTPUT ;
    USE SIGNAL ;
    PORT
      LAYER M7 ;
        RECT  21.76 57.931 21.792 58 ;
    END
  END dout[382]
  PIN dout[383]
    DIRECTION OUTPUT ;
    USE SIGNAL ;
    PORT
      LAYER M7 ;
        RECT  19.2 57.931 19.232 58 ;
    END
  END dout[383]
  PIN dout[384]
    DIRECTION OUTPUT ;
    USE SIGNAL ;
    PORT
      LAYER M5 ;
        RECT  25.68 57.916 25.704 58 ;
    END
  END dout[384]
  PIN dout[385]
    DIRECTION OUTPUT ;
    USE SIGNAL ;
    PORT
      LAYER M5 ;
        RECT  25.92 57.916 25.944 58 ;
    END
  END dout[385]
  PIN dout[386]
    DIRECTION OUTPUT ;
    USE SIGNAL ;
    PORT
      LAYER M7 ;
        RECT  40.704 57.931 40.736 58 ;
    END
  END dout[386]
  PIN dout[387]
    DIRECTION OUTPUT ;
    USE SIGNAL ;
    PORT
      LAYER M7 ;
        RECT  29.952 57.931 29.984 58 ;
    END
  END dout[387]
  PIN dout[388]
    DIRECTION OUTPUT ;
    USE SIGNAL ;
    PORT
      LAYER M7 ;
        RECT  22.208 57.931 22.24 58 ;
    END
  END dout[388]
  PIN dout[389]
    DIRECTION OUTPUT ;
    USE SIGNAL ;
    PORT
      LAYER M5 ;
        RECT  26.112 57.916 26.136 58 ;
    END
  END dout[389]
  PIN dout[38]
    DIRECTION OUTPUT ;
    USE SIGNAL ;
    PORT
      LAYER M7 ;
        RECT  83.648 57.931 83.68 58 ;
    END
  END dout[38]
  PIN dout[390]
    DIRECTION OUTPUT ;
    USE SIGNAL ;
    PORT
      LAYER M7 ;
        RECT  40.896 57.931 40.928 58 ;
    END
  END dout[390]
  PIN dout[391]
    DIRECTION OUTPUT ;
    USE SIGNAL ;
    PORT
      LAYER M5 ;
        RECT  26.88 57.916 26.904 58 ;
    END
  END dout[391]
  PIN dout[392]
    DIRECTION OUTPUT ;
    USE SIGNAL ;
    PORT
      LAYER M7 ;
        RECT  43.264 57.931 43.296 58 ;
    END
  END dout[392]
  PIN dout[393]
    DIRECTION OUTPUT ;
    USE SIGNAL ;
    PORT
      LAYER M7 ;
        RECT  21.632 57.931 21.664 58 ;
    END
  END dout[393]
  PIN dout[394]
    DIRECTION OUTPUT ;
    USE SIGNAL ;
    PORT
      LAYER M5 ;
        RECT  25.488 57.916 25.512 58 ;
    END
  END dout[394]
  PIN dout[395]
    DIRECTION OUTPUT ;
    USE SIGNAL ;
    PORT
      LAYER M7 ;
        RECT  31.616 57.931 31.648 58 ;
    END
  END dout[395]
  PIN dout[396]
    DIRECTION OUTPUT ;
    USE SIGNAL ;
    PORT
      LAYER M5 ;
        RECT  12.864 57.916 12.888 58 ;
    END
  END dout[396]
  PIN dout[397]
    DIRECTION OUTPUT ;
    USE SIGNAL ;
    PORT
      LAYER M7 ;
        RECT  42.048 57.931 42.08 58 ;
    END
  END dout[397]
  PIN dout[398]
    DIRECTION OUTPUT ;
    USE SIGNAL ;
    PORT
      LAYER M5 ;
        RECT  28.272 57.916 28.296 58 ;
    END
  END dout[398]
  PIN dout[399]
    DIRECTION OUTPUT ;
    USE SIGNAL ;
    PORT
      LAYER M7 ;
        RECT  44.096 57.931 44.128 58 ;
    END
  END dout[399]
  PIN dout[39]
    DIRECTION OUTPUT ;
    USE SIGNAL ;
    PORT
      LAYER M5 ;
        RECT  76.704 57.916 76.728 58 ;
    END
  END dout[39]
  PIN dout[3]
    DIRECTION OUTPUT ;
    USE SIGNAL ;
    PORT
      LAYER M5 ;
        RECT  87.792 57.916 87.816 58 ;
    END
  END dout[3]
  PIN dout[400]
    DIRECTION OUTPUT ;
    USE SIGNAL ;
    PORT
      LAYER M5 ;
        RECT  35.376 57.916 35.4 58 ;
    END
  END dout[400]
  PIN dout[401]
    DIRECTION OUTPUT ;
    USE SIGNAL ;
    PORT
      LAYER M7 ;
        RECT  40.128 57.931 40.16 58 ;
    END
  END dout[401]
  PIN dout[402]
    DIRECTION OUTPUT ;
    USE SIGNAL ;
    PORT
      LAYER M5 ;
        RECT  37.728 57.916 37.752 58 ;
    END
  END dout[402]
  PIN dout[403]
    DIRECTION OUTPUT ;
    USE SIGNAL ;
    PORT
      LAYER M7 ;
        RECT  43.328 57.931 43.36 58 ;
    END
  END dout[403]
  PIN dout[404]
    DIRECTION OUTPUT ;
    USE SIGNAL ;
    PORT
      LAYER M5 ;
        RECT  46.848 57.916 46.872 58 ;
    END
  END dout[404]
  PIN dout[405]
    DIRECTION OUTPUT ;
    USE SIGNAL ;
    PORT
      LAYER M7 ;
        RECT  41.344 57.931 41.376 58 ;
    END
  END dout[405]
  PIN dout[406]
    DIRECTION OUTPUT ;
    USE SIGNAL ;
    PORT
      LAYER M7 ;
        RECT  41.92 57.931 41.952 58 ;
    END
  END dout[406]
  PIN dout[407]
    DIRECTION OUTPUT ;
    USE SIGNAL ;
    PORT
      LAYER M7 ;
        RECT  33.6 57.931 33.632 58 ;
    END
  END dout[407]
  PIN dout[408]
    DIRECTION OUTPUT ;
    USE SIGNAL ;
    PORT
      LAYER M5 ;
        RECT  37.344 57.916 37.368 58 ;
    END
  END dout[408]
  PIN dout[409]
    DIRECTION OUTPUT ;
    USE SIGNAL ;
    PORT
      LAYER M5 ;
        RECT  34.128 57.916 34.152 58 ;
    END
  END dout[409]
  PIN dout[40]
    DIRECTION OUTPUT ;
    USE SIGNAL ;
    PORT
      LAYER M5 ;
        RECT  75.888 57.916 75.912 58 ;
    END
  END dout[40]
  PIN dout[410]
    DIRECTION OUTPUT ;
    USE SIGNAL ;
    PORT
      LAYER M5 ;
        RECT  11.952 57.916 11.976 58 ;
    END
  END dout[410]
  PIN dout[411]
    DIRECTION OUTPUT ;
    USE SIGNAL ;
    PORT
      LAYER M5 ;
        RECT  39.888 57.916 39.912 58 ;
    END
  END dout[411]
  PIN dout[412]
    DIRECTION OUTPUT ;
    USE SIGNAL ;
    PORT
      LAYER M5 ;
        RECT  9.216 57.916 9.24 58 ;
    END
  END dout[412]
  PIN dout[413]
    DIRECTION OUTPUT ;
    USE SIGNAL ;
    PORT
      LAYER M7 ;
        RECT  32.384 57.931 32.416 58 ;
    END
  END dout[413]
  PIN dout[414]
    DIRECTION OUTPUT ;
    USE SIGNAL ;
    PORT
      LAYER M5 ;
        RECT  10.32 57.916 10.344 58 ;
    END
  END dout[414]
  PIN dout[415]
    DIRECTION OUTPUT ;
    USE SIGNAL ;
    PORT
      LAYER M5 ;
        RECT  13.632 57.916 13.656 58 ;
    END
  END dout[415]
  PIN dout[416]
    DIRECTION OUTPUT ;
    USE SIGNAL ;
    PORT
      LAYER M5 ;
        RECT  8.784 57.916 8.808 58 ;
    END
  END dout[416]
  PIN dout[417]
    DIRECTION OUTPUT ;
    USE SIGNAL ;
    PORT
      LAYER M5 ;
        RECT  28.032 57.916 28.056 58 ;
    END
  END dout[417]
  PIN dout[418]
    DIRECTION OUTPUT ;
    USE SIGNAL ;
    PORT
      LAYER M7 ;
        RECT  6.592 57.931 6.624 58 ;
    END
  END dout[418]
  PIN dout[419]
    DIRECTION OUTPUT ;
    USE SIGNAL ;
    PORT
      LAYER M5 ;
        RECT  11.04 57.916 11.064 58 ;
    END
  END dout[419]
  PIN dout[41]
    DIRECTION OUTPUT ;
    USE SIGNAL ;
    PORT
      LAYER M5 ;
        RECT  29.136 57.916 29.16 58 ;
    END
  END dout[41]
  PIN dout[420]
    DIRECTION OUTPUT ;
    USE SIGNAL ;
    PORT
      LAYER M5 ;
        RECT  2.064 57.916 2.088 58 ;
    END
  END dout[420]
  PIN dout[421]
    DIRECTION OUTPUT ;
    USE SIGNAL ;
    PORT
      LAYER M7 ;
        RECT  40.512 57.931 40.544 58 ;
    END
  END dout[421]
  PIN dout[422]
    DIRECTION OUTPUT ;
    USE SIGNAL ;
    PORT
      LAYER M7 ;
        RECT  4.288 57.931 4.32 58 ;
    END
  END dout[422]
  PIN dout[423]
    DIRECTION OUTPUT ;
    USE SIGNAL ;
    PORT
      LAYER M7 ;
        RECT  6.464 57.931 6.496 58 ;
    END
  END dout[423]
  PIN dout[424]
    DIRECTION OUTPUT ;
    USE SIGNAL ;
    PORT
      LAYER M5 ;
        RECT  2.736 57.916 2.76 58 ;
    END
  END dout[424]
  PIN dout[425]
    DIRECTION OUTPUT ;
    USE SIGNAL ;
    PORT
      LAYER M5 ;
        RECT  34.656 57.916 34.68 58 ;
    END
  END dout[425]
  PIN dout[426]
    DIRECTION OUTPUT ;
    USE SIGNAL ;
    PORT
      LAYER M7 ;
        RECT  6.336 57.931 6.368 58 ;
    END
  END dout[426]
  PIN dout[427]
    DIRECTION OUTPUT ;
    USE SIGNAL ;
    PORT
      LAYER M7 ;
        RECT  5.696 57.931 5.728 58 ;
    END
  END dout[427]
  PIN dout[428]
    DIRECTION OUTPUT ;
    USE SIGNAL ;
    PORT
      LAYER M5 ;
        RECT  7.968 57.916 7.992 58 ;
    END
  END dout[428]
  PIN dout[429]
    DIRECTION OUTPUT ;
    USE SIGNAL ;
    PORT
      LAYER M7 ;
        RECT  4.352 57.931 4.384 58 ;
    END
  END dout[429]
  PIN dout[42]
    DIRECTION OUTPUT ;
    USE SIGNAL ;
    PORT
      LAYER M7 ;
        RECT  30.848 57.931 30.88 58 ;
    END
  END dout[42]
  PIN dout[430]
    DIRECTION OUTPUT ;
    USE SIGNAL ;
    PORT
      LAYER M7 ;
        RECT  32.512 57.931 32.544 58 ;
    END
  END dout[430]
  PIN dout[431]
    DIRECTION OUTPUT ;
    USE SIGNAL ;
    PORT
      LAYER M5 ;
        RECT  40.224 57.916 40.248 58 ;
    END
  END dout[431]
  PIN dout[432]
    DIRECTION OUTPUT ;
    USE SIGNAL ;
    PORT
      LAYER M7 ;
        RECT  30.4 57.931 30.432 58 ;
    END
  END dout[432]
  PIN dout[433]
    DIRECTION OUTPUT ;
    USE SIGNAL ;
    PORT
      LAYER M7 ;
        RECT  30.272 57.931 30.304 58 ;
    END
  END dout[433]
  PIN dout[434]
    DIRECTION OUTPUT ;
    USE SIGNAL ;
    PORT
      LAYER M5 ;
        RECT  28.752 57.916 28.776 58 ;
    END
  END dout[434]
  PIN dout[435]
    DIRECTION OUTPUT ;
    USE SIGNAL ;
    PORT
      LAYER M7 ;
        RECT  29.696 57.931 29.728 58 ;
    END
  END dout[435]
  PIN dout[436]
    DIRECTION OUTPUT ;
    USE SIGNAL ;
    PORT
      LAYER M7 ;
        RECT  31.296 57.931 31.328 58 ;
    END
  END dout[436]
  PIN dout[437]
    DIRECTION OUTPUT ;
    USE SIGNAL ;
    PORT
      LAYER M5 ;
        RECT  35.136 57.916 35.16 58 ;
    END
  END dout[437]
  PIN dout[438]
    DIRECTION OUTPUT ;
    USE SIGNAL ;
    PORT
      LAYER M5 ;
        RECT  24.432 57.916 24.456 58 ;
    END
  END dout[438]
  PIN dout[439]
    DIRECTION OUTPUT ;
    USE SIGNAL ;
    PORT
      LAYER M5 ;
        RECT  25.968 57.916 25.992 58 ;
    END
  END dout[439]
  PIN dout[43]
    DIRECTION OUTPUT ;
    USE SIGNAL ;
    PORT
      LAYER M5 ;
        RECT  73.728 57.916 73.752 58 ;
    END
  END dout[43]
  PIN dout[440]
    DIRECTION OUTPUT ;
    USE SIGNAL ;
    PORT
      LAYER M5 ;
        RECT  40.32 57.916 40.344 58 ;
    END
  END dout[440]
  PIN dout[441]
    DIRECTION OUTPUT ;
    USE SIGNAL ;
    PORT
      LAYER M5 ;
        RECT  35.424 57.916 35.448 58 ;
    END
  END dout[441]
  PIN dout[442]
    DIRECTION OUTPUT ;
    USE SIGNAL ;
    PORT
      LAYER M7 ;
        RECT  31.808 57.931 31.84 58 ;
    END
  END dout[442]
  PIN dout[443]
    DIRECTION OUTPUT ;
    USE SIGNAL ;
    PORT
      LAYER M5 ;
        RECT  45.84 57.916 45.864 58 ;
    END
  END dout[443]
  PIN dout[444]
    DIRECTION OUTPUT ;
    USE SIGNAL ;
    PORT
      LAYER M7 ;
        RECT  32.832 57.931 32.864 58 ;
    END
  END dout[444]
  PIN dout[445]
    DIRECTION OUTPUT ;
    USE SIGNAL ;
    PORT
      LAYER M5 ;
        RECT  28.896 57.916 28.92 58 ;
    END
  END dout[445]
  PIN dout[446]
    DIRECTION OUTPUT ;
    USE SIGNAL ;
    PORT
      LAYER M5 ;
        RECT  26.688 57.916 26.712 58 ;
    END
  END dout[446]
  PIN dout[447]
    DIRECTION OUTPUT ;
    USE SIGNAL ;
    PORT
      LAYER M5 ;
        RECT  37.056 57.916 37.08 58 ;
    END
  END dout[447]
  PIN dout[448]
    DIRECTION OUTPUT ;
    USE SIGNAL ;
    PORT
      LAYER M5 ;
        RECT  36.384 57.916 36.408 58 ;
    END
  END dout[448]
  PIN dout[449]
    DIRECTION OUTPUT ;
    USE SIGNAL ;
    PORT
      LAYER M5 ;
        RECT  2.112 57.916 2.136 58 ;
    END
  END dout[449]
  PIN dout[44]
    DIRECTION OUTPUT ;
    USE SIGNAL ;
    PORT
      LAYER M7 ;
        RECT  71.808 57.931 71.84 58 ;
    END
  END dout[44]
  PIN dout[450]
    DIRECTION OUTPUT ;
    USE SIGNAL ;
    PORT
      LAYER M5 ;
        RECT  15.12 57.916 15.144 58 ;
    END
  END dout[450]
  PIN dout[451]
    DIRECTION OUTPUT ;
    USE SIGNAL ;
    PORT
      LAYER M7 ;
        RECT  42.56 57.931 42.592 58 ;
    END
  END dout[451]
  PIN dout[452]
    DIRECTION OUTPUT ;
    USE SIGNAL ;
    PORT
      LAYER M5 ;
        RECT  39.216 57.916 39.24 58 ;
    END
  END dout[452]
  PIN dout[453]
    DIRECTION OUTPUT ;
    USE SIGNAL ;
    PORT
      LAYER M5 ;
        RECT  1.728 57.916 1.752 58 ;
    END
  END dout[453]
  PIN dout[454]
    DIRECTION OUTPUT ;
    USE SIGNAL ;
    PORT
      LAYER M7 ;
        RECT  40.32 57.931 40.352 58 ;
    END
  END dout[454]
  PIN dout[455]
    DIRECTION OUTPUT ;
    USE SIGNAL ;
    PORT
      LAYER M5 ;
        RECT  38.88 57.916 38.904 58 ;
    END
  END dout[455]
  PIN dout[456]
    DIRECTION OUTPUT ;
    USE SIGNAL ;
    PORT
      LAYER M5 ;
        RECT  38.304 57.916 38.328 58 ;
    END
  END dout[456]
  PIN dout[457]
    DIRECTION OUTPUT ;
    USE SIGNAL ;
    PORT
      LAYER M7 ;
        RECT  33.28 57.931 33.312 58 ;
    END
  END dout[457]
  PIN dout[458]
    DIRECTION OUTPUT ;
    USE SIGNAL ;
    PORT
      LAYER M7 ;
        RECT  40.448 57.931 40.48 58 ;
    END
  END dout[458]
  PIN dout[459]
    DIRECTION OUTPUT ;
    USE SIGNAL ;
    PORT
      LAYER M5 ;
        RECT  2.544 57.916 2.568 58 ;
    END
  END dout[459]
  PIN dout[45]
    DIRECTION OUTPUT ;
    USE SIGNAL ;
    PORT
      LAYER M7 ;
        RECT  30.976 57.931 31.008 58 ;
    END
  END dout[45]
  PIN dout[460]
    DIRECTION OUTPUT ;
    USE SIGNAL ;
    PORT
      LAYER M5 ;
        RECT  38.496 57.916 38.52 58 ;
    END
  END dout[460]
  PIN dout[461]
    DIRECTION OUTPUT ;
    USE SIGNAL ;
    PORT
      LAYER M5 ;
        RECT  38.448 57.916 38.472 58 ;
    END
  END dout[461]
  PIN dout[462]
    DIRECTION OUTPUT ;
    USE SIGNAL ;
    PORT
      LAYER M5 ;
        RECT  38.016 57.916 38.04 58 ;
    END
  END dout[462]
  PIN dout[463]
    DIRECTION OUTPUT ;
    USE SIGNAL ;
    PORT
      LAYER M5 ;
        RECT  39.696 57.916 39.72 58 ;
    END
  END dout[463]
  PIN dout[464]
    DIRECTION OUTPUT ;
    USE SIGNAL ;
    PORT
      LAYER M5 ;
        RECT  39.984 57.916 40.008 58 ;
    END
  END dout[464]
  PIN dout[465]
    DIRECTION OUTPUT ;
    USE SIGNAL ;
    PORT
      LAYER M7 ;
        RECT  30.464 57.931 30.496 58 ;
    END
  END dout[465]
  PIN dout[466]
    DIRECTION OUTPUT ;
    USE SIGNAL ;
    PORT
      LAYER M5 ;
        RECT  14.976 57.916 15 58 ;
    END
  END dout[466]
  PIN dout[467]
    DIRECTION OUTPUT ;
    USE SIGNAL ;
    PORT
      LAYER M5 ;
        RECT  36.816 57.916 36.84 58 ;
    END
  END dout[467]
  PIN dout[468]
    DIRECTION OUTPUT ;
    USE SIGNAL ;
    PORT
      LAYER M7 ;
        RECT  18.688 57.931 18.72 58 ;
    END
  END dout[468]
  PIN dout[469]
    DIRECTION OUTPUT ;
    USE SIGNAL ;
    PORT
      LAYER M5 ;
        RECT  23.904 57.916 23.928 58 ;
    END
  END dout[469]
  PIN dout[46]
    DIRECTION OUTPUT ;
    USE SIGNAL ;
    PORT
      LAYER M5 ;
        RECT  74.688 57.916 74.712 58 ;
    END
  END dout[46]
  PIN dout[470]
    DIRECTION OUTPUT ;
    USE SIGNAL ;
    PORT
      LAYER M7 ;
        RECT  33.216 57.931 33.248 58 ;
    END
  END dout[470]
  PIN dout[471]
    DIRECTION OUTPUT ;
    USE SIGNAL ;
    PORT
      LAYER M7 ;
        RECT  33.792 57.931 33.824 58 ;
    END
  END dout[471]
  PIN dout[472]
    DIRECTION OUTPUT ;
    USE SIGNAL ;
    PORT
      LAYER M5 ;
        RECT  55.344 57.916 55.368 58 ;
    END
  END dout[472]
  PIN dout[473]
    DIRECTION OUTPUT ;
    USE SIGNAL ;
    PORT
      LAYER M5 ;
        RECT  78.72 57.916 78.744 58 ;
    END
  END dout[473]
  PIN dout[474]
    DIRECTION OUTPUT ;
    USE SIGNAL ;
    PORT
      LAYER M7 ;
        RECT  61.056 57.931 61.088 58 ;
    END
  END dout[474]
  PIN dout[475]
    DIRECTION OUTPUT ;
    USE SIGNAL ;
    PORT
      LAYER M5 ;
        RECT  84.288 57.916 84.312 58 ;
    END
  END dout[475]
  PIN dout[476]
    DIRECTION OUTPUT ;
    USE SIGNAL ;
    PORT
      LAYER M5 ;
        RECT  48.432 57.916 48.456 58 ;
    END
  END dout[476]
  PIN dout[477]
    DIRECTION OUTPUT ;
    USE SIGNAL ;
    PORT
      LAYER M5 ;
        RECT  66.528 57.916 66.552 58 ;
    END
  END dout[477]
  PIN dout[478]
    DIRECTION OUTPUT ;
    USE SIGNAL ;
    PORT
      LAYER M5 ;
        RECT  55.2 57.916 55.224 58 ;
    END
  END dout[478]
  PIN dout[479]
    DIRECTION OUTPUT ;
    USE SIGNAL ;
    PORT
      LAYER M5 ;
        RECT  63.936 57.916 63.96 58 ;
    END
  END dout[479]
  PIN dout[47]
    DIRECTION OUTPUT ;
    USE SIGNAL ;
    PORT
      LAYER M5 ;
        RECT  28.416 57.916 28.44 58 ;
    END
  END dout[47]
  PIN dout[480]
    DIRECTION OUTPUT ;
    USE SIGNAL ;
    PORT
      LAYER M7 ;
        RECT  59.776 57.931 59.808 58 ;
    END
  END dout[480]
  PIN dout[481]
    DIRECTION OUTPUT ;
    USE SIGNAL ;
    PORT
      LAYER M7 ;
        RECT  57.152 57.931 57.184 58 ;
    END
  END dout[481]
  PIN dout[482]
    DIRECTION OUTPUT ;
    USE SIGNAL ;
    PORT
      LAYER M5 ;
        RECT  53.472 57.916 53.496 58 ;
    END
  END dout[482]
  PIN dout[483]
    DIRECTION OUTPUT ;
    USE SIGNAL ;
    PORT
      LAYER M5 ;
        RECT  66.576 57.916 66.6 58 ;
    END
  END dout[483]
  PIN dout[484]
    DIRECTION OUTPUT ;
    USE SIGNAL ;
    PORT
      LAYER M5 ;
        RECT  52.176 57.916 52.2 58 ;
    END
  END dout[484]
  PIN dout[485]
    DIRECTION OUTPUT ;
    USE SIGNAL ;
    PORT
      LAYER M7 ;
        RECT  69.952 57.931 69.984 58 ;
    END
  END dout[485]
  PIN dout[486]
    DIRECTION OUTPUT ;
    USE SIGNAL ;
    PORT
      LAYER M7 ;
        RECT  69.568 57.931 69.6 58 ;
    END
  END dout[486]
  PIN dout[487]
    DIRECTION OUTPUT ;
    USE SIGNAL ;
    PORT
      LAYER M5 ;
        RECT  76.848 57.916 76.872 58 ;
    END
  END dout[487]
  PIN dout[488]
    DIRECTION OUTPUT ;
    USE SIGNAL ;
    PORT
      LAYER M5 ;
        RECT  73.056 57.916 73.08 58 ;
    END
  END dout[488]
  PIN dout[489]
    DIRECTION OUTPUT ;
    USE SIGNAL ;
    PORT
      LAYER M5 ;
        RECT  75.072 57.916 75.096 58 ;
    END
  END dout[489]
  PIN dout[48]
    DIRECTION OUTPUT ;
    USE SIGNAL ;
    PORT
      LAYER M7 ;
        RECT  72.256 57.931 72.288 58 ;
    END
  END dout[48]
  PIN dout[490]
    DIRECTION OUTPUT ;
    USE SIGNAL ;
    PORT
      LAYER M5 ;
        RECT  75.168 57.916 75.192 58 ;
    END
  END dout[490]
  PIN dout[491]
    DIRECTION OUTPUT ;
    USE SIGNAL ;
    PORT
      LAYER M5 ;
        RECT  76.224 57.916 76.248 58 ;
    END
  END dout[491]
  PIN dout[492]
    DIRECTION OUTPUT ;
    USE SIGNAL ;
    PORT
      LAYER M5 ;
        RECT  73.392 57.916 73.416 58 ;
    END
  END dout[492]
  PIN dout[493]
    DIRECTION OUTPUT ;
    USE SIGNAL ;
    PORT
      LAYER M5 ;
        RECT  85.2 57.916 85.224 58 ;
    END
  END dout[493]
  PIN dout[494]
    DIRECTION OUTPUT ;
    USE SIGNAL ;
    PORT
      LAYER M7 ;
        RECT  81.408 57.931 81.44 58 ;
    END
  END dout[494]
  PIN dout[495]
    DIRECTION OUTPUT ;
    USE SIGNAL ;
    PORT
      LAYER M5 ;
        RECT  85.872 57.916 85.896 58 ;
    END
  END dout[495]
  PIN dout[496]
    DIRECTION OUTPUT ;
    USE SIGNAL ;
    PORT
      LAYER M7 ;
        RECT  83.776 57.931 83.808 58 ;
    END
  END dout[496]
  PIN dout[497]
    DIRECTION OUTPUT ;
    USE SIGNAL ;
    PORT
      LAYER M5 ;
        RECT  84 57.916 84.024 58 ;
    END
  END dout[497]
  PIN dout[498]
    DIRECTION OUTPUT ;
    USE SIGNAL ;
    PORT
      LAYER M5 ;
        RECT  86.832 57.916 86.856 58 ;
    END
  END dout[498]
  PIN dout[499]
    DIRECTION OUTPUT ;
    USE SIGNAL ;
    PORT
      LAYER M5 ;
        RECT  84.336 57.916 84.36 58 ;
    END
  END dout[499]
  PIN dout[49]
    DIRECTION OUTPUT ;
    USE SIGNAL ;
    PORT
      LAYER M5 ;
        RECT  86.784 57.916 86.808 58 ;
    END
  END dout[49]
  PIN dout[4]
    DIRECTION OUTPUT ;
    USE SIGNAL ;
    PORT
      LAYER M7 ;
        RECT  80.192 57.931 80.224 58 ;
    END
  END dout[4]
  PIN dout[500]
    DIRECTION OUTPUT ;
    USE SIGNAL ;
    PORT
      LAYER M5 ;
        RECT  88.896 57.916 88.92 58 ;
    END
  END dout[500]
  PIN dout[501]
    DIRECTION OUTPUT ;
    USE SIGNAL ;
    PORT
      LAYER M5 ;
        RECT  87.696 57.916 87.72 58 ;
    END
  END dout[501]
  PIN dout[502]
    DIRECTION OUTPUT ;
    USE SIGNAL ;
    PORT
      LAYER M5 ;
        RECT  87.84 57.916 87.864 58 ;
    END
  END dout[502]
  PIN dout[503]
    DIRECTION OUTPUT ;
    USE SIGNAL ;
    PORT
      LAYER M5 ;
        RECT  82.368 57.916 82.392 58 ;
    END
  END dout[503]
  PIN dout[504]
    DIRECTION OUTPUT ;
    USE SIGNAL ;
    PORT
      LAYER M5 ;
        RECT  87.408 57.916 87.432 58 ;
    END
  END dout[504]
  PIN dout[505]
    DIRECTION OUTPUT ;
    USE SIGNAL ;
    PORT
      LAYER M5 ;
        RECT  81.84 57.916 81.864 58 ;
    END
  END dout[505]
  PIN dout[506]
    DIRECTION OUTPUT ;
    USE SIGNAL ;
    PORT
      LAYER M5 ;
        RECT  80.928 57.916 80.952 58 ;
    END
  END dout[506]
  PIN dout[507]
    DIRECTION OUTPUT ;
    USE SIGNAL ;
    PORT
      LAYER M5 ;
        RECT  88.992 57.916 89.016 58 ;
    END
  END dout[507]
  PIN dout[508]
    DIRECTION OUTPUT ;
    USE SIGNAL ;
    PORT
      LAYER M5 ;
        RECT  82.8 57.916 82.824 58 ;
    END
  END dout[508]
  PIN dout[509]
    DIRECTION OUTPUT ;
    USE SIGNAL ;
    PORT
      LAYER M5 ;
        RECT  81.552 57.916 81.576 58 ;
    END
  END dout[509]
  PIN dout[50]
    DIRECTION OUTPUT ;
    USE SIGNAL ;
    PORT
      LAYER M7 ;
        RECT  79.68 57.931 79.712 58 ;
    END
  END dout[50]
  PIN dout[510]
    DIRECTION OUTPUT ;
    USE SIGNAL ;
    PORT
      LAYER M5 ;
        RECT  82.128 57.916 82.152 58 ;
    END
  END dout[510]
  PIN dout[511]
    DIRECTION OUTPUT ;
    USE SIGNAL ;
    PORT
      LAYER M5 ;
        RECT  87.552 57.916 87.576 58 ;
    END
  END dout[511]
  PIN dout[512]
    DIRECTION OUTPUT ;
    USE SIGNAL ;
    PORT
      LAYER M5 ;
        RECT  81.696 57.916 81.72 58 ;
    END
  END dout[512]
  PIN dout[513]
    DIRECTION OUTPUT ;
    USE SIGNAL ;
    PORT
      LAYER M5 ;
        RECT  81.504 57.916 81.528 58 ;
    END
  END dout[513]
  PIN dout[514]
    DIRECTION OUTPUT ;
    USE SIGNAL ;
    PORT
      LAYER M7 ;
        RECT  82.624 57.931 82.656 58 ;
    END
  END dout[514]
  PIN dout[515]
    DIRECTION OUTPUT ;
    USE SIGNAL ;
    PORT
      LAYER M5 ;
        RECT  86.4 57.916 86.424 58 ;
    END
  END dout[515]
  PIN dout[516]
    DIRECTION OUTPUT ;
    USE SIGNAL ;
    PORT
      LAYER M5 ;
        RECT  87.648 57.916 87.672 58 ;
    END
  END dout[516]
  PIN dout[517]
    DIRECTION OUTPUT ;
    USE SIGNAL ;
    PORT
      LAYER M5 ;
        RECT  82.464 57.916 82.488 58 ;
    END
  END dout[517]
  PIN dout[518]
    DIRECTION OUTPUT ;
    USE SIGNAL ;
    PORT
      LAYER M5 ;
        RECT  86.208 57.916 86.232 58 ;
    END
  END dout[518]
  PIN dout[519]
    DIRECTION OUTPUT ;
    USE SIGNAL ;
    PORT
      LAYER M5 ;
        RECT  83.232 57.916 83.256 58 ;
    END
  END dout[519]
  PIN dout[51]
    DIRECTION OUTPUT ;
    USE SIGNAL ;
    PORT
      LAYER M7 ;
        RECT  31.872 57.931 31.904 58 ;
    END
  END dout[51]
  PIN dout[520]
    DIRECTION OUTPUT ;
    USE SIGNAL ;
    PORT
      LAYER M7 ;
        RECT  84.224 57.931 84.256 58 ;
    END
  END dout[520]
  PIN dout[521]
    DIRECTION OUTPUT ;
    USE SIGNAL ;
    PORT
      LAYER M7 ;
        RECT  82.944 57.931 82.976 58 ;
    END
  END dout[521]
  PIN dout[522]
    DIRECTION OUTPUT ;
    USE SIGNAL ;
    PORT
      LAYER M5 ;
        RECT  80.88 57.916 80.904 58 ;
    END
  END dout[522]
  PIN dout[523]
    DIRECTION OUTPUT ;
    USE SIGNAL ;
    PORT
      LAYER M5 ;
        RECT  66.192 57.916 66.216 58 ;
    END
  END dout[523]
  PIN dout[524]
    DIRECTION OUTPUT ;
    USE SIGNAL ;
    PORT
      LAYER M7 ;
        RECT  82.048 57.931 82.08 58 ;
    END
  END dout[524]
  PIN dout[525]
    DIRECTION OUTPUT ;
    USE SIGNAL ;
    PORT
      LAYER M5 ;
        RECT  50.208 57.916 50.232 58 ;
    END
  END dout[525]
  PIN dout[526]
    DIRECTION OUTPUT ;
    USE SIGNAL ;
    PORT
      LAYER M5 ;
        RECT  62.016 57.916 62.04 58 ;
    END
  END dout[526]
  PIN dout[527]
    DIRECTION OUTPUT ;
    USE SIGNAL ;
    PORT
      LAYER M5 ;
        RECT  50.016 57.916 50.04 58 ;
    END
  END dout[527]
  PIN dout[528]
    DIRECTION OUTPUT ;
    USE SIGNAL ;
    PORT
      LAYER M7 ;
        RECT  68.544 57.931 68.576 58 ;
    END
  END dout[528]
  PIN dout[529]
    DIRECTION OUTPUT ;
    USE SIGNAL ;
    PORT
      LAYER M7 ;
        RECT  42.432 57.931 42.464 58 ;
    END
  END dout[529]
  PIN dout[52]
    DIRECTION OUTPUT ;
    USE SIGNAL ;
    PORT
      LAYER M5 ;
        RECT  83.328 57.916 83.352 58 ;
    END
  END dout[52]
  PIN dout[530]
    DIRECTION OUTPUT ;
    USE SIGNAL ;
    PORT
      LAYER M5 ;
        RECT  46.416 57.916 46.44 58 ;
    END
  END dout[530]
  PIN dout[531]
    DIRECTION OUTPUT ;
    USE SIGNAL ;
    PORT
      LAYER M7 ;
        RECT  42.176 57.931 42.208 58 ;
    END
  END dout[531]
  PIN dout[532]
    DIRECTION OUTPUT ;
    USE SIGNAL ;
    PORT
      LAYER M7 ;
        RECT  44.416 57.931 44.448 58 ;
    END
  END dout[532]
  PIN dout[533]
    DIRECTION OUTPUT ;
    USE SIGNAL ;
    PORT
      LAYER M5 ;
        RECT  87.6 57.916 87.624 58 ;
    END
  END dout[533]
  PIN dout[534]
    DIRECTION OUTPUT ;
    USE SIGNAL ;
    PORT
      LAYER M5 ;
        RECT  48.912 57.916 48.936 58 ;
    END
  END dout[534]
  PIN dout[535]
    DIRECTION OUTPUT ;
    USE SIGNAL ;
    PORT
      LAYER M5 ;
        RECT  46.176 57.916 46.2 58 ;
    END
  END dout[535]
  PIN dout[536]
    DIRECTION OUTPUT ;
    USE SIGNAL ;
    PORT
      LAYER M5 ;
        RECT  87.024 57.916 87.048 58 ;
    END
  END dout[536]
  PIN dout[537]
    DIRECTION OUTPUT ;
    USE SIGNAL ;
    PORT
      LAYER M7 ;
        RECT  83.264 57.931 83.296 58 ;
    END
  END dout[537]
  PIN dout[538]
    DIRECTION OUTPUT ;
    USE SIGNAL ;
    PORT
      LAYER M5 ;
        RECT  87.264 57.916 87.288 58 ;
    END
  END dout[538]
  PIN dout[539]
    DIRECTION OUTPUT ;
    USE SIGNAL ;
    PORT
      LAYER M7 ;
        RECT  82.56 57.931 82.592 58 ;
    END
  END dout[539]
  PIN dout[53]
    DIRECTION OUTPUT ;
    USE SIGNAL ;
    PORT
      LAYER M7 ;
        RECT  82.688 57.931 82.72 58 ;
    END
  END dout[53]
  PIN dout[540]
    DIRECTION OUTPUT ;
    USE SIGNAL ;
    PORT
      LAYER M5 ;
        RECT  89.088 57.916 89.112 58 ;
    END
  END dout[540]
  PIN dout[541]
    DIRECTION OUTPUT ;
    USE SIGNAL ;
    PORT
      LAYER M5 ;
        RECT  88.032 57.916 88.056 58 ;
    END
  END dout[541]
  PIN dout[542]
    DIRECTION OUTPUT ;
    USE SIGNAL ;
    PORT
      LAYER M5 ;
        RECT  85.104 57.916 85.128 58 ;
    END
  END dout[542]
  PIN dout[543]
    DIRECTION OUTPUT ;
    USE SIGNAL ;
    PORT
      LAYER M7 ;
        RECT  81.024 57.931 81.056 58 ;
    END
  END dout[543]
  PIN dout[544]
    DIRECTION OUTPUT ;
    USE SIGNAL ;
    PORT
      LAYER M5 ;
        RECT  80.832 57.916 80.856 58 ;
    END
  END dout[544]
  PIN dout[545]
    DIRECTION OUTPUT ;
    USE SIGNAL ;
    PORT
      LAYER M7 ;
        RECT  80.704 57.931 80.736 58 ;
    END
  END dout[545]
  PIN dout[546]
    DIRECTION OUTPUT ;
    USE SIGNAL ;
    PORT
      LAYER M7 ;
        RECT  83.328 57.931 83.36 58 ;
    END
  END dout[546]
  PIN dout[547]
    DIRECTION OUTPUT ;
    USE SIGNAL ;
    PORT
      LAYER M5 ;
        RECT  81.456 57.916 81.48 58 ;
    END
  END dout[547]
  PIN dout[548]
    DIRECTION OUTPUT ;
    USE SIGNAL ;
    PORT
      LAYER M5 ;
        RECT  85.248 57.916 85.272 58 ;
    END
  END dout[548]
  PIN dout[549]
    DIRECTION OUTPUT ;
    USE SIGNAL ;
    PORT
      LAYER M5 ;
        RECT  85.776 57.916 85.8 58 ;
    END
  END dout[549]
  PIN dout[54]
    DIRECTION OUTPUT ;
    USE SIGNAL ;
    PORT
      LAYER M5 ;
        RECT  25.584 57.916 25.608 58 ;
    END
  END dout[54]
  PIN dout[550]
    DIRECTION OUTPUT ;
    USE SIGNAL ;
    PORT
      LAYER M5 ;
        RECT  80.64 57.916 80.664 58 ;
    END
  END dout[550]
  PIN dout[551]
    DIRECTION OUTPUT ;
    USE SIGNAL ;
    PORT
      LAYER M5 ;
        RECT  86.928 57.916 86.952 58 ;
    END
  END dout[551]
  PIN dout[552]
    DIRECTION OUTPUT ;
    USE SIGNAL ;
    PORT
      LAYER M5 ;
        RECT  89.136 57.916 89.16 58 ;
    END
  END dout[552]
  PIN dout[553]
    DIRECTION OUTPUT ;
    USE SIGNAL ;
    PORT
      LAYER M5 ;
        RECT  88.848 57.916 88.872 58 ;
    END
  END dout[553]
  PIN dout[554]
    DIRECTION OUTPUT ;
    USE SIGNAL ;
    PORT
      LAYER M5 ;
        RECT  83.136 57.916 83.16 58 ;
    END
  END dout[554]
  PIN dout[555]
    DIRECTION OUTPUT ;
    USE SIGNAL ;
    PORT
      LAYER M5 ;
        RECT  88.752 57.916 88.776 58 ;
    END
  END dout[555]
  PIN dout[556]
    DIRECTION OUTPUT ;
    USE SIGNAL ;
    PORT
      LAYER M5 ;
        RECT  82.656 57.916 82.68 58 ;
    END
  END dout[556]
  PIN dout[557]
    DIRECTION OUTPUT ;
    USE SIGNAL ;
    PORT
      LAYER M5 ;
        RECT  83.088 57.916 83.112 58 ;
    END
  END dout[557]
  PIN dout[558]
    DIRECTION OUTPUT ;
    USE SIGNAL ;
    PORT
      LAYER M5 ;
        RECT  81.744 57.916 81.768 58 ;
    END
  END dout[558]
  PIN dout[559]
    DIRECTION OUTPUT ;
    USE SIGNAL ;
    PORT
      LAYER M5 ;
        RECT  84.864 57.916 84.888 58 ;
    END
  END dout[559]
  PIN dout[55]
    DIRECTION OUTPUT ;
    USE SIGNAL ;
    PORT
      LAYER M7 ;
        RECT  79.232 57.931 79.264 58 ;
    END
  END dout[55]
  PIN dout[560]
    DIRECTION OUTPUT ;
    USE SIGNAL ;
    PORT
      LAYER M7 ;
        RECT  83.072 57.931 83.104 58 ;
    END
  END dout[560]
  PIN dout[561]
    DIRECTION OUTPUT ;
    USE SIGNAL ;
    PORT
      LAYER M5 ;
        RECT  85.344 57.916 85.368 58 ;
    END
  END dout[561]
  PIN dout[562]
    DIRECTION OUTPUT ;
    USE SIGNAL ;
    PORT
      LAYER M7 ;
        RECT  82.304 57.931 82.336 58 ;
    END
  END dout[562]
  PIN dout[563]
    DIRECTION OUTPUT ;
    USE SIGNAL ;
    PORT
      LAYER M5 ;
        RECT  84.816 57.916 84.84 58 ;
    END
  END dout[563]
  PIN dout[564]
    DIRECTION OUTPUT ;
    USE SIGNAL ;
    PORT
      LAYER M7 ;
        RECT  80.256 57.931 80.288 58 ;
    END
  END dout[564]
  PIN dout[565]
    DIRECTION OUTPUT ;
    USE SIGNAL ;
    PORT
      LAYER M5 ;
        RECT  85.92 57.916 85.944 58 ;
    END
  END dout[565]
  PIN dout[566]
    DIRECTION OUTPUT ;
    USE SIGNAL ;
    PORT
      LAYER M5 ;
        RECT  84.24 57.916 84.264 58 ;
    END
  END dout[566]
  PIN dout[567]
    DIRECTION OUTPUT ;
    USE SIGNAL ;
    PORT
      LAYER M7 ;
        RECT  78.464 57.931 78.496 58 ;
    END
  END dout[567]
  PIN dout[568]
    DIRECTION OUTPUT ;
    USE SIGNAL ;
    PORT
      LAYER M7 ;
        RECT  84.416 57.931 84.448 58 ;
    END
  END dout[568]
  PIN dout[569]
    DIRECTION OUTPUT ;
    USE SIGNAL ;
    PORT
      LAYER M7 ;
        RECT  79.168 57.931 79.2 58 ;
    END
  END dout[569]
  PIN dout[56]
    DIRECTION OUTPUT ;
    USE SIGNAL ;
    PORT
      LAYER M7 ;
        RECT  78.528 57.931 78.56 58 ;
    END
  END dout[56]
  PIN dout[570]
    DIRECTION OUTPUT ;
    USE SIGNAL ;
    PORT
      LAYER M7 ;
        RECT  81.28 57.931 81.312 58 ;
    END
  END dout[570]
  PIN dout[571]
    DIRECTION OUTPUT ;
    USE SIGNAL ;
    PORT
      LAYER M5 ;
        RECT  84.096 57.916 84.12 58 ;
    END
  END dout[571]
  PIN dout[572]
    DIRECTION OUTPUT ;
    USE SIGNAL ;
    PORT
      LAYER M7 ;
        RECT  79.36 57.931 79.392 58 ;
    END
  END dout[572]
  PIN dout[573]
    DIRECTION OUTPUT ;
    USE SIGNAL ;
    PORT
      LAYER M5 ;
        RECT  88.944 57.916 88.968 58 ;
    END
  END dout[573]
  PIN dout[574]
    DIRECTION OUTPUT ;
    USE SIGNAL ;
    PORT
      LAYER M7 ;
        RECT  80.896 57.931 80.928 58 ;
    END
  END dout[574]
  PIN dout[575]
    DIRECTION OUTPUT ;
    USE SIGNAL ;
    PORT
      LAYER M5 ;
        RECT  84.384 57.916 84.408 58 ;
    END
  END dout[575]
  PIN dout[576]
    DIRECTION OUTPUT ;
    USE SIGNAL ;
    PORT
      LAYER M7 ;
        RECT  81.664 57.931 81.696 58 ;
    END
  END dout[576]
  PIN dout[577]
    DIRECTION OUTPUT ;
    USE SIGNAL ;
    PORT
      LAYER M5 ;
        RECT  86.112 57.916 86.136 58 ;
    END
  END dout[577]
  PIN dout[578]
    DIRECTION OUTPUT ;
    USE SIGNAL ;
    PORT
      LAYER M5 ;
        RECT  78.432 57.916 78.456 58 ;
    END
  END dout[578]
  PIN dout[579]
    DIRECTION OUTPUT ;
    USE SIGNAL ;
    PORT
      LAYER M5 ;
        RECT  83.184 57.916 83.208 58 ;
    END
  END dout[579]
  PIN dout[57]
    DIRECTION OUTPUT ;
    USE SIGNAL ;
    PORT
      LAYER M7 ;
        RECT  32.192 57.931 32.224 58 ;
    END
  END dout[57]
  PIN dout[580]
    DIRECTION OUTPUT ;
    USE SIGNAL ;
    PORT
      LAYER M5 ;
        RECT  85.488 57.916 85.512 58 ;
    END
  END dout[580]
  PIN dout[581]
    DIRECTION OUTPUT ;
    USE SIGNAL ;
    PORT
      LAYER M5 ;
        RECT  84.048 57.916 84.072 58 ;
    END
  END dout[581]
  PIN dout[582]
    DIRECTION OUTPUT ;
    USE SIGNAL ;
    PORT
      LAYER M5 ;
        RECT  78.288 57.916 78.312 58 ;
    END
  END dout[582]
  PIN dout[583]
    DIRECTION OUTPUT ;
    USE SIGNAL ;
    PORT
      LAYER M7 ;
        RECT  80.768 57.931 80.8 58 ;
    END
  END dout[583]
  PIN dout[584]
    DIRECTION OUTPUT ;
    USE SIGNAL ;
    PORT
      LAYER M7 ;
        RECT  82.88 57.931 82.912 58 ;
    END
  END dout[584]
  PIN dout[585]
    DIRECTION OUTPUT ;
    USE SIGNAL ;
    PORT
      LAYER M5 ;
        RECT  81.408 57.916 81.432 58 ;
    END
  END dout[585]
  PIN dout[586]
    DIRECTION OUTPUT ;
    USE SIGNAL ;
    PORT
      LAYER M5 ;
        RECT  78.576 57.916 78.6 58 ;
    END
  END dout[586]
  PIN dout[587]
    DIRECTION OUTPUT ;
    USE SIGNAL ;
    PORT
      LAYER M5 ;
        RECT  78.048 57.916 78.072 58 ;
    END
  END dout[587]
  PIN dout[588]
    DIRECTION OUTPUT ;
    USE SIGNAL ;
    PORT
      LAYER M5 ;
        RECT  76.368 57.916 76.392 58 ;
    END
  END dout[588]
  PIN dout[589]
    DIRECTION OUTPUT ;
    USE SIGNAL ;
    PORT
      LAYER M5 ;
        RECT  78.24 57.916 78.264 58 ;
    END
  END dout[589]
  PIN dout[58]
    DIRECTION OUTPUT ;
    USE SIGNAL ;
    PORT
      LAYER M7 ;
        RECT  82.176 57.931 82.208 58 ;
    END
  END dout[58]
  PIN dout[590]
    DIRECTION OUTPUT ;
    USE SIGNAL ;
    PORT
      LAYER M7 ;
        RECT  79.744 57.931 79.776 58 ;
    END
  END dout[590]
  PIN dout[591]
    DIRECTION OUTPUT ;
    USE SIGNAL ;
    PORT
      LAYER M5 ;
        RECT  77.712 57.916 77.736 58 ;
    END
  END dout[591]
  PIN dout[592]
    DIRECTION OUTPUT ;
    USE SIGNAL ;
    PORT
      LAYER M5 ;
        RECT  74.4 57.916 74.424 58 ;
    END
  END dout[592]
  PIN dout[593]
    DIRECTION OUTPUT ;
    USE SIGNAL ;
    PORT
      LAYER M5 ;
        RECT  83.568 57.916 83.592 58 ;
    END
  END dout[593]
  PIN dout[594]
    DIRECTION OUTPUT ;
    USE SIGNAL ;
    PORT
      LAYER M7 ;
        RECT  79.936 57.931 79.968 58 ;
    END
  END dout[594]
  PIN dout[595]
    DIRECTION OUTPUT ;
    USE SIGNAL ;
    PORT
      LAYER M5 ;
        RECT  28.992 57.916 29.016 58 ;
    END
  END dout[595]
  PIN dout[596]
    DIRECTION OUTPUT ;
    USE SIGNAL ;
    PORT
      LAYER M7 ;
        RECT  70.336 57.931 70.368 58 ;
    END
  END dout[596]
  PIN dout[597]
    DIRECTION OUTPUT ;
    USE SIGNAL ;
    PORT
      LAYER M7 ;
        RECT  72.384 57.931 72.416 58 ;
    END
  END dout[597]
  PIN dout[598]
    DIRECTION OUTPUT ;
    USE SIGNAL ;
    PORT
      LAYER M7 ;
        RECT  81.92 57.931 81.952 58 ;
    END
  END dout[598]
  PIN dout[599]
    DIRECTION OUTPUT ;
    USE SIGNAL ;
    PORT
      LAYER M5 ;
        RECT  76.656 57.916 76.68 58 ;
    END
  END dout[599]
  PIN dout[59]
    DIRECTION OUTPUT ;
    USE SIGNAL ;
    PORT
      LAYER M5 ;
        RECT  74.832 57.916 74.856 58 ;
    END
  END dout[59]
  PIN dout[5]
    DIRECTION OUTPUT ;
    USE SIGNAL ;
    PORT
      LAYER M5 ;
        RECT  81.984 57.916 82.008 58 ;
    END
  END dout[5]
  PIN dout[600]
    DIRECTION OUTPUT ;
    USE SIGNAL ;
    PORT
      LAYER M5 ;
        RECT  76.176 57.916 76.2 58 ;
    END
  END dout[600]
  PIN dout[601]
    DIRECTION OUTPUT ;
    USE SIGNAL ;
    PORT
      LAYER M5 ;
        RECT  29.088 57.916 29.112 58 ;
    END
  END dout[601]
  PIN dout[602]
    DIRECTION OUTPUT ;
    USE SIGNAL ;
    PORT
      LAYER M7 ;
        RECT  31.104 57.931 31.136 58 ;
    END
  END dout[602]
  PIN dout[603]
    DIRECTION OUTPUT ;
    USE SIGNAL ;
    PORT
      LAYER M5 ;
        RECT  73.824 57.916 73.848 58 ;
    END
  END dout[603]
  PIN dout[604]
    DIRECTION OUTPUT ;
    USE SIGNAL ;
    PORT
      LAYER M7 ;
        RECT  71.936 57.931 71.968 58 ;
    END
  END dout[604]
  PIN dout[605]
    DIRECTION OUTPUT ;
    USE SIGNAL ;
    PORT
      LAYER M7 ;
        RECT  30.912 57.931 30.944 58 ;
    END
  END dout[605]
  PIN dout[606]
    DIRECTION OUTPUT ;
    USE SIGNAL ;
    PORT
      LAYER M5 ;
        RECT  74.88 57.916 74.904 58 ;
    END
  END dout[606]
  PIN dout[607]
    DIRECTION OUTPUT ;
    USE SIGNAL ;
    PORT
      LAYER M5 ;
        RECT  28.32 57.916 28.344 58 ;
    END
  END dout[607]
  PIN dout[608]
    DIRECTION OUTPUT ;
    USE SIGNAL ;
    PORT
      LAYER M7 ;
        RECT  72.192 57.931 72.224 58 ;
    END
  END dout[608]
  PIN dout[609]
    DIRECTION OUTPUT ;
    USE SIGNAL ;
    PORT
      LAYER M5 ;
        RECT  86.64 57.916 86.664 58 ;
    END
  END dout[609]
  PIN dout[60]
    DIRECTION OUTPUT ;
    USE SIGNAL ;
    PORT
      LAYER M7 ;
        RECT  80 57.931 80.032 58 ;
    END
  END dout[60]
  PIN dout[610]
    DIRECTION OUTPUT ;
    USE SIGNAL ;
    PORT
      LAYER M7 ;
        RECT  81.472 57.931 81.504 58 ;
    END
  END dout[610]
  PIN dout[611]
    DIRECTION OUTPUT ;
    USE SIGNAL ;
    PORT
      LAYER M7 ;
        RECT  32 57.931 32.032 58 ;
    END
  END dout[611]
  PIN dout[612]
    DIRECTION OUTPUT ;
    USE SIGNAL ;
    PORT
      LAYER M5 ;
        RECT  83.664 57.916 83.688 58 ;
    END
  END dout[612]
  PIN dout[613]
    DIRECTION OUTPUT ;
    USE SIGNAL ;
    PORT
      LAYER M7 ;
        RECT  82.432 57.931 82.464 58 ;
    END
  END dout[613]
  PIN dout[614]
    DIRECTION OUTPUT ;
    USE SIGNAL ;
    PORT
      LAYER M5 ;
        RECT  25.392 57.916 25.416 58 ;
    END
  END dout[614]
  PIN dout[615]
    DIRECTION OUTPUT ;
    USE SIGNAL ;
    PORT
      LAYER M5 ;
        RECT  78.768 57.916 78.792 58 ;
    END
  END dout[615]
  PIN dout[616]
    DIRECTION OUTPUT ;
    USE SIGNAL ;
    PORT
      LAYER M7 ;
        RECT  78.784 57.931 78.816 58 ;
    END
  END dout[616]
  PIN dout[617]
    DIRECTION OUTPUT ;
    USE SIGNAL ;
    PORT
      LAYER M7 ;
        RECT  32.256 57.931 32.288 58 ;
    END
  END dout[617]
  PIN dout[618]
    DIRECTION OUTPUT ;
    USE SIGNAL ;
    PORT
      LAYER M7 ;
        RECT  82.112 57.931 82.144 58 ;
    END
  END dout[618]
  PIN dout[619]
    DIRECTION OUTPUT ;
    USE SIGNAL ;
    PORT
      LAYER M5 ;
        RECT  75.024 57.916 75.048 58 ;
    END
  END dout[619]
  PIN dout[61]
    DIRECTION OUTPUT ;
    USE SIGNAL ;
    PORT
      LAYER M7 ;
        RECT  78.976 57.931 79.008 58 ;
    END
  END dout[61]
  PIN dout[620]
    DIRECTION OUTPUT ;
    USE SIGNAL ;
    PORT
      LAYER M7 ;
        RECT  78.848 57.931 78.88 58 ;
    END
  END dout[620]
  PIN dout[621]
    DIRECTION OUTPUT ;
    USE SIGNAL ;
    PORT
      LAYER M7 ;
        RECT  78.592 57.931 78.624 58 ;
    END
  END dout[621]
  PIN dout[622]
    DIRECTION OUTPUT ;
    USE SIGNAL ;
    PORT
      LAYER M5 ;
        RECT  76.896 57.916 76.92 58 ;
    END
  END dout[622]
  PIN dout[623]
    DIRECTION OUTPUT ;
    USE SIGNAL ;
    PORT
      LAYER M5 ;
        RECT  76.8 57.916 76.824 58 ;
    END
  END dout[623]
  PIN dout[624]
    DIRECTION OUTPUT ;
    USE SIGNAL ;
    PORT
      LAYER M5 ;
        RECT  15.792 57.916 15.816 58 ;
    END
  END dout[624]
  PIN dout[625]
    DIRECTION OUTPUT ;
    USE SIGNAL ;
    PORT
      LAYER M5 ;
        RECT  15.696 57.916 15.72 58 ;
    END
  END dout[625]
  PIN dout[626]
    DIRECTION OUTPUT ;
    USE SIGNAL ;
    PORT
      LAYER M5 ;
        RECT  34.08 57.916 34.104 58 ;
    END
  END dout[626]
  PIN dout[627]
    DIRECTION OUTPUT ;
    USE SIGNAL ;
    PORT
      LAYER M5 ;
        RECT  35.184 57.916 35.208 58 ;
    END
  END dout[627]
  PIN dout[628]
    DIRECTION OUTPUT ;
    USE SIGNAL ;
    PORT
      LAYER M5 ;
        RECT  13.056 57.916 13.08 58 ;
    END
  END dout[628]
  PIN dout[629]
    DIRECTION OUTPUT ;
    USE SIGNAL ;
    PORT
      LAYER M5 ;
        RECT  11.424 57.916 11.448 58 ;
    END
  END dout[629]
  PIN dout[62]
    DIRECTION OUTPUT ;
    USE SIGNAL ;
    PORT
      LAYER M5 ;
        RECT  76.464 57.916 76.488 58 ;
    END
  END dout[62]
  PIN dout[630]
    DIRECTION OUTPUT ;
    USE SIGNAL ;
    PORT
      LAYER M5 ;
        RECT  16.512 57.916 16.536 58 ;
    END
  END dout[630]
  PIN dout[631]
    DIRECTION OUTPUT ;
    USE SIGNAL ;
    PORT
      LAYER M5 ;
        RECT  9.84 57.916 9.864 58 ;
    END
  END dout[631]
  PIN dout[632]
    DIRECTION OUTPUT ;
    USE SIGNAL ;
    PORT
      LAYER M5 ;
        RECT  7.92 57.916 7.944 58 ;
    END
  END dout[632]
  PIN dout[633]
    DIRECTION OUTPUT ;
    USE SIGNAL ;
    PORT
      LAYER M7 ;
        RECT  6.912 57.931 6.944 58 ;
    END
  END dout[633]
  PIN dout[634]
    DIRECTION OUTPUT ;
    USE SIGNAL ;
    PORT
      LAYER M5 ;
        RECT  12.816 57.916 12.84 58 ;
    END
  END dout[634]
  PIN dout[635]
    DIRECTION OUTPUT ;
    USE SIGNAL ;
    PORT
      LAYER M7 ;
        RECT  4.032 57.931 4.064 58 ;
    END
  END dout[635]
  PIN dout[636]
    DIRECTION OUTPUT ;
    USE SIGNAL ;
    PORT
      LAYER M7 ;
        RECT  6.08 57.931 6.112 58 ;
    END
  END dout[636]
  PIN dout[637]
    DIRECTION OUTPUT ;
    USE SIGNAL ;
    PORT
      LAYER M5 ;
        RECT  9.936 57.916 9.96 58 ;
    END
  END dout[637]
  PIN dout[638]
    DIRECTION OUTPUT ;
    USE SIGNAL ;
    PORT
      LAYER M5 ;
        RECT  2.304 57.916 2.328 58 ;
    END
  END dout[638]
  PIN dout[639]
    DIRECTION OUTPUT ;
    USE SIGNAL ;
    PORT
      LAYER M5 ;
        RECT  2.592 57.916 2.616 58 ;
    END
  END dout[639]
  PIN dout[63]
    DIRECTION OUTPUT ;
    USE SIGNAL ;
    PORT
      LAYER M5 ;
        RECT  76.32 57.916 76.344 58 ;
    END
  END dout[63]
  PIN dout[640]
    DIRECTION OUTPUT ;
    USE SIGNAL ;
    PORT
      LAYER M7 ;
        RECT  4.608 57.931 4.64 58 ;
    END
  END dout[640]
  PIN dout[641]
    DIRECTION OUTPUT ;
    USE SIGNAL ;
    PORT
      LAYER M5 ;
        RECT  1.968 57.916 1.992 58 ;
    END
  END dout[641]
  PIN dout[642]
    DIRECTION OUTPUT ;
    USE SIGNAL ;
    PORT
      LAYER M7 ;
        RECT  6.208 57.931 6.24 58 ;
    END
  END dout[642]
  PIN dout[643]
    DIRECTION OUTPUT ;
    USE SIGNAL ;
    PORT
      LAYER M7 ;
        RECT  4.48 57.931 4.512 58 ;
    END
  END dout[643]
  PIN dout[644]
    DIRECTION OUTPUT ;
    USE SIGNAL ;
    PORT
      LAYER M5 ;
        RECT  8.736 57.916 8.76 58 ;
    END
  END dout[644]
  PIN dout[645]
    DIRECTION OUTPUT ;
    USE SIGNAL ;
    PORT
      LAYER M5 ;
        RECT  10.416 57.916 10.44 58 ;
    END
  END dout[645]
  PIN dout[646]
    DIRECTION OUTPUT ;
    USE SIGNAL ;
    PORT
      LAYER M5 ;
        RECT  7.872 57.916 7.896 58 ;
    END
  END dout[646]
  PIN dout[647]
    DIRECTION OUTPUT ;
    USE SIGNAL ;
    PORT
      LAYER M5 ;
        RECT  1.632 57.916 1.656 58 ;
    END
  END dout[647]
  PIN dout[648]
    DIRECTION OUTPUT ;
    USE SIGNAL ;
    PORT
      LAYER M5 ;
        RECT  9.072 57.916 9.096 58 ;
    END
  END dout[648]
  PIN dout[649]
    DIRECTION OUTPUT ;
    USE SIGNAL ;
    PORT
      LAYER M5 ;
        RECT  10.608 57.916 10.632 58 ;
    END
  END dout[649]
  PIN dout[64]
    DIRECTION OUTPUT ;
    USE SIGNAL ;
    PORT
      LAYER M5 ;
        RECT  15.888 57.916 15.912 58 ;
    END
  END dout[64]
  PIN dout[650]
    DIRECTION OUTPUT ;
    USE SIGNAL ;
    PORT
      LAYER M5 ;
        RECT  16.56 57.916 16.584 58 ;
    END
  END dout[650]
  PIN dout[651]
    DIRECTION OUTPUT ;
    USE SIGNAL ;
    PORT
      LAYER M7 ;
        RECT  31.168 57.931 31.2 58 ;
    END
  END dout[651]
  PIN dout[652]
    DIRECTION OUTPUT ;
    USE SIGNAL ;
    PORT
      LAYER M5 ;
        RECT  15.072 57.916 15.096 58 ;
    END
  END dout[652]
  PIN dout[653]
    DIRECTION OUTPUT ;
    USE SIGNAL ;
    PORT
      LAYER M5 ;
        RECT  15.984 57.916 16.008 58 ;
    END
  END dout[653]
  PIN dout[654]
    DIRECTION OUTPUT ;
    USE SIGNAL ;
    PORT
      LAYER M5 ;
        RECT  17.952 57.916 17.976 58 ;
    END
  END dout[654]
  PIN dout[655]
    DIRECTION OUTPUT ;
    USE SIGNAL ;
    PORT
      LAYER M5 ;
        RECT  22.8 57.916 22.824 58 ;
    END
  END dout[655]
  PIN dout[656]
    DIRECTION OUTPUT ;
    USE SIGNAL ;
    PORT
      LAYER M7 ;
        RECT  40.768 57.931 40.8 58 ;
    END
  END dout[656]
  PIN dout[657]
    DIRECTION OUTPUT ;
    USE SIGNAL ;
    PORT
      LAYER M5 ;
        RECT  24.48 57.916 24.504 58 ;
    END
  END dout[657]
  PIN dout[658]
    DIRECTION OUTPUT ;
    USE SIGNAL ;
    PORT
      LAYER M7 ;
        RECT  20.224 57.931 20.256 58 ;
    END
  END dout[658]
  PIN dout[659]
    DIRECTION OUTPUT ;
    USE SIGNAL ;
    PORT
      LAYER M7 ;
        RECT  32.064 57.931 32.096 58 ;
    END
  END dout[659]
  PIN dout[65]
    DIRECTION OUTPUT ;
    USE SIGNAL ;
    PORT
      LAYER M5 ;
        RECT  15.648 57.916 15.672 58 ;
    END
  END dout[65]
  PIN dout[660]
    DIRECTION OUTPUT ;
    USE SIGNAL ;
    PORT
      LAYER M7 ;
        RECT  6.848 57.931 6.88 58 ;
    END
  END dout[660]
  PIN dout[661]
    DIRECTION OUTPUT ;
    USE SIGNAL ;
    PORT
      LAYER M7 ;
        RECT  20.544 57.931 20.576 58 ;
    END
  END dout[661]
  PIN dout[662]
    DIRECTION OUTPUT ;
    USE SIGNAL ;
    PORT
      LAYER M7 ;
        RECT  21.696 57.931 21.728 58 ;
    END
  END dout[662]
  PIN dout[663]
    DIRECTION OUTPUT ;
    USE SIGNAL ;
    PORT
      LAYER M5 ;
        RECT  17.904 57.916 17.928 58 ;
    END
  END dout[663]
  PIN dout[664]
    DIRECTION OUTPUT ;
    USE SIGNAL ;
    PORT
      LAYER M5 ;
        RECT  25.536 57.916 25.56 58 ;
    END
  END dout[664]
  PIN dout[665]
    DIRECTION OUTPUT ;
    USE SIGNAL ;
    PORT
      LAYER M5 ;
        RECT  26.592 57.916 26.616 58 ;
    END
  END dout[665]
  PIN dout[666]
    DIRECTION OUTPUT ;
    USE SIGNAL ;
    PORT
      LAYER M7 ;
        RECT  40.576 57.931 40.608 58 ;
    END
  END dout[666]
  PIN dout[667]
    DIRECTION OUTPUT ;
    USE SIGNAL ;
    PORT
      LAYER M7 ;
        RECT  29.888 57.931 29.92 58 ;
    END
  END dout[667]
  PIN dout[668]
    DIRECTION OUTPUT ;
    USE SIGNAL ;
    PORT
      LAYER M7 ;
        RECT  22.272 57.931 22.304 58 ;
    END
  END dout[668]
  PIN dout[669]
    DIRECTION OUTPUT ;
    USE SIGNAL ;
    PORT
      LAYER M5 ;
        RECT  25.776 57.916 25.8 58 ;
    END
  END dout[669]
  PIN dout[66]
    DIRECTION OUTPUT ;
    USE SIGNAL ;
    PORT
      LAYER M5 ;
        RECT  34.896 57.916 34.92 58 ;
    END
  END dout[66]
  PIN dout[670]
    DIRECTION OUTPUT ;
    USE SIGNAL ;
    PORT
      LAYER M7 ;
        RECT  41.536 57.931 41.568 58 ;
    END
  END dout[670]
  PIN dout[671]
    DIRECTION OUTPUT ;
    USE SIGNAL ;
    PORT
      LAYER M5 ;
        RECT  26.928 57.916 26.952 58 ;
    END
  END dout[671]
  PIN dout[672]
    DIRECTION OUTPUT ;
    USE SIGNAL ;
    PORT
      LAYER M7 ;
        RECT  43.456 57.931 43.488 58 ;
    END
  END dout[672]
  PIN dout[673]
    DIRECTION OUTPUT ;
    USE SIGNAL ;
    PORT
      LAYER M7 ;
        RECT  21.568 57.931 21.6 58 ;
    END
  END dout[673]
  PIN dout[674]
    DIRECTION OUTPUT ;
    USE SIGNAL ;
    PORT
      LAYER M5 ;
        RECT  24.816 57.916 24.84 58 ;
    END
  END dout[674]
  PIN dout[675]
    DIRECTION OUTPUT ;
    USE SIGNAL ;
    PORT
      LAYER M7 ;
        RECT  31.936 57.931 31.968 58 ;
    END
  END dout[675]
  PIN dout[676]
    DIRECTION OUTPUT ;
    USE SIGNAL ;
    PORT
      LAYER M5 ;
        RECT  12.96 57.916 12.984 58 ;
    END
  END dout[676]
  PIN dout[677]
    DIRECTION OUTPUT ;
    USE SIGNAL ;
    PORT
      LAYER M5 ;
        RECT  40.272 57.916 40.296 58 ;
    END
  END dout[677]
  PIN dout[678]
    DIRECTION OUTPUT ;
    USE SIGNAL ;
    PORT
      LAYER M5 ;
        RECT  28.56 57.916 28.584 58 ;
    END
  END dout[678]
  PIN dout[679]
    DIRECTION OUTPUT ;
    USE SIGNAL ;
    PORT
      LAYER M7 ;
        RECT  44.8 57.931 44.832 58 ;
    END
  END dout[679]
  PIN dout[67]
    DIRECTION OUTPUT ;
    USE SIGNAL ;
    PORT
      LAYER M5 ;
        RECT  35.232 57.916 35.256 58 ;
    END
  END dout[67]
  PIN dout[680]
    DIRECTION OUTPUT ;
    USE SIGNAL ;
    PORT
      LAYER M5 ;
        RECT  35.472 57.916 35.496 58 ;
    END
  END dout[680]
  PIN dout[681]
    DIRECTION OUTPUT ;
    USE SIGNAL ;
    PORT
      LAYER M7 ;
        RECT  41.984 57.931 42.016 58 ;
    END
  END dout[681]
  PIN dout[682]
    DIRECTION OUTPUT ;
    USE SIGNAL ;
    PORT
      LAYER M5 ;
        RECT  37.632 57.916 37.656 58 ;
    END
  END dout[682]
  PIN dout[683]
    DIRECTION OUTPUT ;
    USE SIGNAL ;
    PORT
      LAYER M7 ;
        RECT  43.584 57.931 43.616 58 ;
    END
  END dout[683]
  PIN dout[684]
    DIRECTION OUTPUT ;
    USE SIGNAL ;
    PORT
      LAYER M5 ;
        RECT  46.8 57.916 46.824 58 ;
    END
  END dout[684]
  PIN dout[685]
    DIRECTION OUTPUT ;
    USE SIGNAL ;
    PORT
      LAYER M7 ;
        RECT  40.96 57.931 40.992 58 ;
    END
  END dout[685]
  PIN dout[686]
    DIRECTION OUTPUT ;
    USE SIGNAL ;
    PORT
      LAYER M7 ;
        RECT  42.112 57.931 42.144 58 ;
    END
  END dout[686]
  PIN dout[687]
    DIRECTION OUTPUT ;
    USE SIGNAL ;
    PORT
      LAYER M7 ;
        RECT  33.408 57.931 33.44 58 ;
    END
  END dout[687]
  PIN dout[688]
    DIRECTION OUTPUT ;
    USE SIGNAL ;
    PORT
      LAYER M5 ;
        RECT  37.296 57.916 37.32 58 ;
    END
  END dout[688]
  PIN dout[689]
    DIRECTION OUTPUT ;
    USE SIGNAL ;
    PORT
      LAYER M5 ;
        RECT  34.704 57.916 34.728 58 ;
    END
  END dout[689]
  PIN dout[68]
    DIRECTION OUTPUT ;
    USE SIGNAL ;
    PORT
      LAYER M5 ;
        RECT  13.584 57.916 13.608 58 ;
    END
  END dout[68]
  PIN dout[690]
    DIRECTION OUTPUT ;
    USE SIGNAL ;
    PORT
      LAYER M5 ;
        RECT  11.664 57.916 11.688 58 ;
    END
  END dout[690]
  PIN dout[691]
    DIRECTION OUTPUT ;
    USE SIGNAL ;
    PORT
      LAYER M5 ;
        RECT  39.936 57.916 39.96 58 ;
    END
  END dout[691]
  PIN dout[692]
    DIRECTION OUTPUT ;
    USE SIGNAL ;
    PORT
      LAYER M5 ;
        RECT  9.264 57.916 9.288 58 ;
    END
  END dout[692]
  PIN dout[693]
    DIRECTION OUTPUT ;
    USE SIGNAL ;
    PORT
      LAYER M7 ;
        RECT  32.576 57.931 32.608 58 ;
    END
  END dout[693]
  PIN dout[694]
    DIRECTION OUTPUT ;
    USE SIGNAL ;
    PORT
      LAYER M5 ;
        RECT  10.512 57.916 10.536 58 ;
    END
  END dout[694]
  PIN dout[695]
    DIRECTION OUTPUT ;
    USE SIGNAL ;
    PORT
      LAYER M5 ;
        RECT  13.728 57.916 13.752 58 ;
    END
  END dout[695]
  PIN dout[696]
    DIRECTION OUTPUT ;
    USE SIGNAL ;
    PORT
      LAYER M5 ;
        RECT  8.88 57.916 8.904 58 ;
    END
  END dout[696]
  PIN dout[697]
    DIRECTION OUTPUT ;
    USE SIGNAL ;
    PORT
      LAYER M5 ;
        RECT  27.888 57.916 27.912 58 ;
    END
  END dout[697]
  PIN dout[698]
    DIRECTION OUTPUT ;
    USE SIGNAL ;
    PORT
      LAYER M7 ;
        RECT  5.76 57.931 5.792 58 ;
    END
  END dout[698]
  PIN dout[699]
    DIRECTION OUTPUT ;
    USE SIGNAL ;
    PORT
      LAYER M5 ;
        RECT  11.376 57.916 11.4 58 ;
    END
  END dout[699]
  PIN dout[69]
    DIRECTION OUTPUT ;
    USE SIGNAL ;
    PORT
      LAYER M5 ;
        RECT  11.568 57.916 11.592 58 ;
    END
  END dout[69]
  PIN dout[6]
    DIRECTION OUTPUT ;
    USE SIGNAL ;
    PORT
      LAYER M5 ;
        RECT  83.376 57.916 83.4 58 ;
    END
  END dout[6]
  PIN dout[700]
    DIRECTION OUTPUT ;
    USE SIGNAL ;
    PORT
      LAYER M5 ;
        RECT  2.448 57.916 2.472 58 ;
    END
  END dout[700]
  PIN dout[701]
    DIRECTION OUTPUT ;
    USE SIGNAL ;
    PORT
      LAYER M7 ;
        RECT  40.256 57.931 40.288 58 ;
    END
  END dout[701]
  PIN dout[702]
    DIRECTION OUTPUT ;
    USE SIGNAL ;
    PORT
      LAYER M7 ;
        RECT  4.096 57.931 4.128 58 ;
    END
  END dout[702]
  PIN dout[703]
    DIRECTION OUTPUT ;
    USE SIGNAL ;
    PORT
      LAYER M7 ;
        RECT  6.528 57.931 6.56 58 ;
    END
  END dout[703]
  PIN dout[704]
    DIRECTION OUTPUT ;
    USE SIGNAL ;
    PORT
      LAYER M5 ;
        RECT  1.92 57.916 1.944 58 ;
    END
  END dout[704]
  PIN dout[705]
    DIRECTION OUTPUT ;
    USE SIGNAL ;
    PORT
      LAYER M5 ;
        RECT  34.608 57.916 34.632 58 ;
    END
  END dout[705]
  PIN dout[706]
    DIRECTION OUTPUT ;
    USE SIGNAL ;
    PORT
      LAYER M7 ;
        RECT  6.4 57.931 6.432 58 ;
    END
  END dout[706]
  PIN dout[707]
    DIRECTION OUTPUT ;
    USE SIGNAL ;
    PORT
      LAYER M7 ;
        RECT  5.888 57.931 5.92 58 ;
    END
  END dout[707]
  PIN dout[708]
    DIRECTION OUTPUT ;
    USE SIGNAL ;
    PORT
      LAYER M5 ;
        RECT  7.728 57.916 7.752 58 ;
    END
  END dout[708]
  PIN dout[709]
    DIRECTION OUTPUT ;
    USE SIGNAL ;
    PORT
      LAYER M7 ;
        RECT  4.544 57.931 4.576 58 ;
    END
  END dout[709]
  PIN dout[70]
    DIRECTION OUTPUT ;
    USE SIGNAL ;
    PORT
      LAYER M5 ;
        RECT  16.608 57.916 16.632 58 ;
    END
  END dout[70]
  PIN dout[710]
    DIRECTION OUTPUT ;
    USE SIGNAL ;
    PORT
      LAYER M7 ;
        RECT  32.448 57.931 32.48 58 ;
    END
  END dout[710]
  PIN dout[711]
    DIRECTION OUTPUT ;
    USE SIGNAL ;
    PORT
      LAYER M5 ;
        RECT  40.032 57.916 40.056 58 ;
    END
  END dout[711]
  PIN dout[712]
    DIRECTION OUTPUT ;
    USE SIGNAL ;
    PORT
      LAYER M7 ;
        RECT  30.08 57.931 30.112 58 ;
    END
  END dout[712]
  PIN dout[713]
    DIRECTION OUTPUT ;
    USE SIGNAL ;
    PORT
      LAYER M7 ;
        RECT  30.144 57.931 30.176 58 ;
    END
  END dout[713]
  PIN dout[714]
    DIRECTION OUTPUT ;
    USE SIGNAL ;
    PORT
      LAYER M5 ;
        RECT  28.944 57.916 28.968 58 ;
    END
  END dout[714]
  PIN dout[715]
    DIRECTION OUTPUT ;
    USE SIGNAL ;
    PORT
      LAYER M7 ;
        RECT  30.656 57.931 30.688 58 ;
    END
  END dout[715]
  PIN dout[716]
    DIRECTION OUTPUT ;
    USE SIGNAL ;
    PORT
      LAYER M7 ;
        RECT  31.68 57.931 31.712 58 ;
    END
  END dout[716]
  PIN dout[717]
    DIRECTION OUTPUT ;
    USE SIGNAL ;
    PORT
      LAYER M5 ;
        RECT  34.992 57.916 35.016 58 ;
    END
  END dout[717]
  PIN dout[718]
    DIRECTION OUTPUT ;
    USE SIGNAL ;
    PORT
      LAYER M5 ;
        RECT  24.72 57.916 24.744 58 ;
    END
  END dout[718]
  PIN dout[719]
    DIRECTION OUTPUT ;
    USE SIGNAL ;
    PORT
      LAYER M5 ;
        RECT  26.16 57.916 26.184 58 ;
    END
  END dout[719]
  PIN dout[71]
    DIRECTION OUTPUT ;
    USE SIGNAL ;
    PORT
      LAYER M5 ;
        RECT  9.792 57.916 9.816 58 ;
    END
  END dout[71]
  PIN dout[720]
    DIRECTION OUTPUT ;
    USE SIGNAL ;
    PORT
      LAYER M7 ;
        RECT  41.088 57.931 41.12 58 ;
    END
  END dout[720]
  PIN dout[721]
    DIRECTION OUTPUT ;
    USE SIGNAL ;
    PORT
      LAYER M5 ;
        RECT  35.328 57.916 35.352 58 ;
    END
  END dout[721]
  PIN dout[722]
    DIRECTION OUTPUT ;
    USE SIGNAL ;
    PORT
      LAYER M7 ;
        RECT  31.424 57.931 31.456 58 ;
    END
  END dout[722]
  PIN dout[723]
    DIRECTION OUTPUT ;
    USE SIGNAL ;
    PORT
      LAYER M5 ;
        RECT  45.792 57.916 45.816 58 ;
    END
  END dout[723]
  PIN dout[724]
    DIRECTION OUTPUT ;
    USE SIGNAL ;
    PORT
      LAYER M7 ;
        RECT  32.768 57.931 32.8 58 ;
    END
  END dout[724]
  PIN dout[725]
    DIRECTION OUTPUT ;
    USE SIGNAL ;
    PORT
      LAYER M5 ;
        RECT  28.848 57.916 28.872 58 ;
    END
  END dout[725]
  PIN dout[726]
    DIRECTION OUTPUT ;
    USE SIGNAL ;
    PORT
      LAYER M5 ;
        RECT  26.064 57.916 26.088 58 ;
    END
  END dout[726]
  PIN dout[727]
    DIRECTION OUTPUT ;
    USE SIGNAL ;
    PORT
      LAYER M5 ;
        RECT  36.864 57.916 36.888 58 ;
    END
  END dout[727]
  PIN dout[728]
    DIRECTION OUTPUT ;
    USE SIGNAL ;
    PORT
      LAYER M5 ;
        RECT  36.336 57.916 36.36 58 ;
    END
  END dout[728]
  PIN dout[729]
    DIRECTION OUTPUT ;
    USE SIGNAL ;
    PORT
      LAYER M5 ;
        RECT  2.16 57.916 2.184 58 ;
    END
  END dout[729]
  PIN dout[72]
    DIRECTION OUTPUT ;
    USE SIGNAL ;
    PORT
      LAYER M5 ;
        RECT  7.824 57.916 7.848 58 ;
    END
  END dout[72]
  PIN dout[730]
    DIRECTION OUTPUT ;
    USE SIGNAL ;
    PORT
      LAYER M5 ;
        RECT  14.064 57.916 14.088 58 ;
    END
  END dout[730]
  PIN dout[731]
    DIRECTION OUTPUT ;
    USE SIGNAL ;
    PORT
      LAYER M7 ;
        RECT  42.496 57.931 42.528 58 ;
    END
  END dout[731]
  PIN dout[732]
    DIRECTION OUTPUT ;
    USE SIGNAL ;
    PORT
      LAYER M5 ;
        RECT  39.264 57.916 39.288 58 ;
    END
  END dout[732]
  PIN dout[733]
    DIRECTION OUTPUT ;
    USE SIGNAL ;
    PORT
      LAYER M5 ;
        RECT  2.64 57.916 2.664 58 ;
    END
  END dout[733]
  PIN dout[734]
    DIRECTION OUTPUT ;
    USE SIGNAL ;
    PORT
      LAYER M5 ;
        RECT  40.176 57.916 40.2 58 ;
    END
  END dout[734]
  PIN dout[735]
    DIRECTION OUTPUT ;
    USE SIGNAL ;
    PORT
      LAYER M5 ;
        RECT  38.784 57.916 38.808 58 ;
    END
  END dout[735]
  PIN dout[736]
    DIRECTION OUTPUT ;
    USE SIGNAL ;
    PORT
      LAYER M5 ;
        RECT  38.64 57.916 38.664 58 ;
    END
  END dout[736]
  PIN dout[737]
    DIRECTION OUTPUT ;
    USE SIGNAL ;
    PORT
      LAYER M7 ;
        RECT  33.536 57.931 33.568 58 ;
    END
  END dout[737]
  PIN dout[738]
    DIRECTION OUTPUT ;
    USE SIGNAL ;
    PORT
      LAYER M7 ;
        RECT  40.64 57.931 40.672 58 ;
    END
  END dout[738]
  PIN dout[739]
    DIRECTION OUTPUT ;
    USE SIGNAL ;
    PORT
      LAYER M5 ;
        RECT  2.832 57.916 2.856 58 ;
    END
  END dout[739]
  PIN dout[73]
    DIRECTION OUTPUT ;
    USE SIGNAL ;
    PORT
      LAYER M7 ;
        RECT  6.976 57.931 7.008 58 ;
    END
  END dout[73]
  PIN dout[740]
    DIRECTION OUTPUT ;
    USE SIGNAL ;
    PORT
      LAYER M5 ;
        RECT  38.112 57.916 38.136 58 ;
    END
  END dout[740]
  PIN dout[741]
    DIRECTION OUTPUT ;
    USE SIGNAL ;
    PORT
      LAYER M5 ;
        RECT  38.16 57.916 38.184 58 ;
    END
  END dout[741]
  PIN dout[742]
    DIRECTION OUTPUT ;
    USE SIGNAL ;
    PORT
      LAYER M5 ;
        RECT  37.968 57.916 37.992 58 ;
    END
  END dout[742]
  PIN dout[743]
    DIRECTION OUTPUT ;
    USE SIGNAL ;
    PORT
      LAYER M5 ;
        RECT  39.792 57.916 39.816 58 ;
    END
  END dout[743]
  PIN dout[744]
    DIRECTION OUTPUT ;
    USE SIGNAL ;
    PORT
      LAYER M5 ;
        RECT  40.368 57.916 40.392 58 ;
    END
  END dout[744]
  PIN dout[745]
    DIRECTION OUTPUT ;
    USE SIGNAL ;
    PORT
      LAYER M7 ;
        RECT  29.824 57.931 29.856 58 ;
    END
  END dout[745]
  PIN dout[746]
    DIRECTION OUTPUT ;
    USE SIGNAL ;
    PORT
      LAYER M5 ;
        RECT  14.736 57.916 14.76 58 ;
    END
  END dout[746]
  PIN dout[747]
    DIRECTION OUTPUT ;
    USE SIGNAL ;
    PORT
      LAYER M5 ;
        RECT  36.72 57.916 36.744 58 ;
    END
  END dout[747]
  PIN dout[748]
    DIRECTION OUTPUT ;
    USE SIGNAL ;
    PORT
      LAYER M7 ;
        RECT  18.752 57.931 18.784 58 ;
    END
  END dout[748]
  PIN dout[749]
    DIRECTION OUTPUT ;
    USE SIGNAL ;
    PORT
      LAYER M5 ;
        RECT  23.856 57.916 23.88 58 ;
    END
  END dout[749]
  PIN dout[74]
    DIRECTION OUTPUT ;
    USE SIGNAL ;
    PORT
      LAYER M5 ;
        RECT  12.768 57.916 12.792 58 ;
    END
  END dout[74]
  PIN dout[750]
    DIRECTION OUTPUT ;
    USE SIGNAL ;
    PORT
      LAYER M7 ;
        RECT  33.344 57.931 33.376 58 ;
    END
  END dout[750]
  PIN dout[751]
    DIRECTION OUTPUT ;
    USE SIGNAL ;
    PORT
      LAYER M7 ;
        RECT  33.152 57.931 33.184 58 ;
    END
  END dout[751]
  PIN dout[752]
    DIRECTION OUTPUT ;
    USE SIGNAL ;
    PORT
      LAYER M5 ;
        RECT  55.44 57.916 55.464 58 ;
    END
  END dout[752]
  PIN dout[753]
    DIRECTION OUTPUT ;
    USE SIGNAL ;
    PORT
      LAYER M5 ;
        RECT  78.528 57.916 78.552 58 ;
    END
  END dout[753]
  PIN dout[754]
    DIRECTION OUTPUT ;
    USE SIGNAL ;
    PORT
      LAYER M5 ;
        RECT  61.296 57.916 61.32 58 ;
    END
  END dout[754]
  PIN dout[755]
    DIRECTION OUTPUT ;
    USE SIGNAL ;
    PORT
      LAYER M5 ;
        RECT  81.936 57.916 81.96 58 ;
    END
  END dout[755]
  PIN dout[756]
    DIRECTION OUTPUT ;
    USE SIGNAL ;
    PORT
      LAYER M5 ;
        RECT  48.384 57.916 48.408 58 ;
    END
  END dout[756]
  PIN dout[757]
    DIRECTION OUTPUT ;
    USE SIGNAL ;
    PORT
      LAYER M5 ;
        RECT  66.48 57.916 66.504 58 ;
    END
  END dout[757]
  PIN dout[758]
    DIRECTION OUTPUT ;
    USE SIGNAL ;
    PORT
      LAYER M5 ;
        RECT  55.536 57.916 55.56 58 ;
    END
  END dout[758]
  PIN dout[759]
    DIRECTION OUTPUT ;
    USE SIGNAL ;
    PORT
      LAYER M5 ;
        RECT  63.888 57.916 63.912 58 ;
    END
  END dout[759]
  PIN dout[75]
    DIRECTION OUTPUT ;
    USE SIGNAL ;
    PORT
      LAYER M7 ;
        RECT  4.16 57.931 4.192 58 ;
    END
  END dout[75]
  PIN dout[760]
    DIRECTION OUTPUT ;
    USE SIGNAL ;
    PORT
      LAYER M7 ;
        RECT  59.84 57.931 59.872 58 ;
    END
  END dout[760]
  PIN dout[761]
    DIRECTION OUTPUT ;
    USE SIGNAL ;
    PORT
      LAYER M7 ;
        RECT  57.28 57.931 57.312 58 ;
    END
  END dout[761]
  PIN dout[762]
    DIRECTION OUTPUT ;
    USE SIGNAL ;
    PORT
      LAYER M5 ;
        RECT  53.52 57.916 53.544 58 ;
    END
  END dout[762]
  PIN dout[763]
    DIRECTION OUTPUT ;
    USE SIGNAL ;
    PORT
      LAYER M7 ;
        RECT  67.904 57.931 67.936 58 ;
    END
  END dout[763]
  PIN dout[764]
    DIRECTION OUTPUT ;
    USE SIGNAL ;
    PORT
      LAYER M5 ;
        RECT  52.032 57.916 52.056 58 ;
    END
  END dout[764]
  PIN dout[765]
    DIRECTION OUTPUT ;
    USE SIGNAL ;
    PORT
      LAYER M7 ;
        RECT  70.144 57.931 70.176 58 ;
    END
  END dout[765]
  PIN dout[766]
    DIRECTION OUTPUT ;
    USE SIGNAL ;
    PORT
      LAYER M7 ;
        RECT  69.632 57.931 69.664 58 ;
    END
  END dout[766]
  PIN dout[767]
    DIRECTION OUTPUT ;
    USE SIGNAL ;
    PORT
      LAYER M5 ;
        RECT  74.976 57.916 75 58 ;
    END
  END dout[767]
  PIN dout[768]
    DIRECTION OUTPUT ;
    USE SIGNAL ;
    PORT
      LAYER M5 ;
        RECT  72.672 57.916 72.696 58 ;
    END
  END dout[768]
  PIN dout[769]
    DIRECTION OUTPUT ;
    USE SIGNAL ;
    PORT
      LAYER M5 ;
        RECT  74.928 57.916 74.952 58 ;
    END
  END dout[769]
  PIN dout[76]
    DIRECTION OUTPUT ;
    USE SIGNAL ;
    PORT
      LAYER M7 ;
        RECT  5.824 57.931 5.856 58 ;
    END
  END dout[76]
  PIN dout[770]
    DIRECTION OUTPUT ;
    USE SIGNAL ;
    PORT
      LAYER M5 ;
        RECT  76.752 57.916 76.776 58 ;
    END
  END dout[770]
  PIN dout[771]
    DIRECTION OUTPUT ;
    USE SIGNAL ;
    PORT
      LAYER M5 ;
        RECT  76.416 57.916 76.44 58 ;
    END
  END dout[771]
  PIN dout[772]
    DIRECTION OUTPUT ;
    USE SIGNAL ;
    PORT
      LAYER M5 ;
        RECT  73.344 57.916 73.368 58 ;
    END
  END dout[772]
  PIN dout[773]
    DIRECTION OUTPUT ;
    USE SIGNAL ;
    PORT
      LAYER M5 ;
        RECT  80.784 57.916 80.808 58 ;
    END
  END dout[773]
  PIN dout[774]
    DIRECTION OUTPUT ;
    USE SIGNAL ;
    PORT
      LAYER M7 ;
        RECT  81.984 57.931 82.016 58 ;
    END
  END dout[774]
  PIN dout[775]
    DIRECTION OUTPUT ;
    USE SIGNAL ;
    PORT
      LAYER M5 ;
        RECT  87.168 57.916 87.192 58 ;
    END
  END dout[775]
  PIN dout[776]
    DIRECTION OUTPUT ;
    USE SIGNAL ;
    PORT
      LAYER M7 ;
        RECT  83.584 57.931 83.616 58 ;
    END
  END dout[776]
  PIN dout[777]
    DIRECTION OUTPUT ;
    USE SIGNAL ;
    PORT
      LAYER M5 ;
        RECT  86.592 57.916 86.616 58 ;
    END
  END dout[777]
  PIN dout[778]
    DIRECTION OUTPUT ;
    USE SIGNAL ;
    PORT
      LAYER M5 ;
        RECT  86.064 57.916 86.088 58 ;
    END
  END dout[778]
  PIN dout[779]
    DIRECTION OUTPUT ;
    USE SIGNAL ;
    PORT
      LAYER M5 ;
        RECT  82.56 57.916 82.584 58 ;
    END
  END dout[779]
  PIN dout[77]
    DIRECTION OUTPUT ;
    USE SIGNAL ;
    PORT
      LAYER M5 ;
        RECT  9.888 57.916 9.912 58 ;
    END
  END dout[77]
  PIN dout[780]
    DIRECTION OUTPUT ;
    USE SIGNAL ;
    PORT
      LAYER M5 ;
        RECT  88.704 57.916 88.728 58 ;
    END
  END dout[780]
  PIN dout[781]
    DIRECTION OUTPUT ;
    USE SIGNAL ;
    PORT
      LAYER M5 ;
        RECT  81.36 57.916 81.384 58 ;
    END
  END dout[781]
  PIN dout[782]
    DIRECTION OUTPUT ;
    USE SIGNAL ;
    PORT
      LAYER M5 ;
        RECT  87.36 57.916 87.384 58 ;
    END
  END dout[782]
  PIN dout[783]
    DIRECTION OUTPUT ;
    USE SIGNAL ;
    PORT
      LAYER M5 ;
        RECT  82.08 57.916 82.104 58 ;
    END
  END dout[783]
  PIN dout[784]
    DIRECTION OUTPUT ;
    USE SIGNAL ;
    PORT
      LAYER M5 ;
        RECT  85.824 57.916 85.848 58 ;
    END
  END dout[784]
  PIN dout[785]
    DIRECTION OUTPUT ;
    USE SIGNAL ;
    PORT
      LAYER M5 ;
        RECT  86.256 57.916 86.28 58 ;
    END
  END dout[785]
  PIN dout[786]
    DIRECTION OUTPUT ;
    USE SIGNAL ;
    PORT
      LAYER M5 ;
        RECT  85.68 57.916 85.704 58 ;
    END
  END dout[786]
  PIN dout[787]
    DIRECTION OUTPUT ;
    USE SIGNAL ;
    PORT
      LAYER M5 ;
        RECT  88.56 57.916 88.584 58 ;
    END
  END dout[787]
  PIN dout[788]
    DIRECTION OUTPUT ;
    USE SIGNAL ;
    PORT
      LAYER M5 ;
        RECT  85.584 57.916 85.608 58 ;
    END
  END dout[788]
  PIN dout[789]
    DIRECTION OUTPUT ;
    USE SIGNAL ;
    PORT
      LAYER M5 ;
        RECT  87.456 57.916 87.48 58 ;
    END
  END dout[789]
  PIN dout[78]
    DIRECTION OUTPUT ;
    USE SIGNAL ;
    PORT
      LAYER M5 ;
        RECT  2.4 57.916 2.424 58 ;
    END
  END dout[78]
  PIN dout[790]
    DIRECTION OUTPUT ;
    USE SIGNAL ;
    PORT
      LAYER M5 ;
        RECT  85.152 57.916 85.176 58 ;
    END
  END dout[790]
  PIN dout[791]
    DIRECTION OUTPUT ;
    USE SIGNAL ;
    PORT
      LAYER M5 ;
        RECT  88.368 57.916 88.392 58 ;
    END
  END dout[791]
  PIN dout[792]
    DIRECTION OUTPUT ;
    USE SIGNAL ;
    PORT
      LAYER M5 ;
        RECT  80.592 57.916 80.616 58 ;
    END
  END dout[792]
  PIN dout[793]
    DIRECTION OUTPUT ;
    USE SIGNAL ;
    PORT
      LAYER M5 ;
        RECT  82.896 57.916 82.92 58 ;
    END
  END dout[793]
  PIN dout[794]
    DIRECTION OUTPUT ;
    USE SIGNAL ;
    PORT
      LAYER M7 ;
        RECT  82.752 57.931 82.784 58 ;
    END
  END dout[794]
  PIN dout[795]
    DIRECTION OUTPUT ;
    USE SIGNAL ;
    PORT
      LAYER M5 ;
        RECT  88.464 57.916 88.488 58 ;
    END
  END dout[795]
  PIN dout[796]
    DIRECTION OUTPUT ;
    USE SIGNAL ;
    PORT
      LAYER M5 ;
        RECT  87.072 57.916 87.096 58 ;
    END
  END dout[796]
  PIN dout[797]
    DIRECTION OUTPUT ;
    USE SIGNAL ;
    PORT
      LAYER M5 ;
        RECT  84.192 57.916 84.216 58 ;
    END
  END dout[797]
  PIN dout[798]
    DIRECTION OUTPUT ;
    USE SIGNAL ;
    PORT
      LAYER M5 ;
        RECT  85.44 57.916 85.464 58 ;
    END
  END dout[798]
  PIN dout[799]
    DIRECTION OUTPUT ;
    USE SIGNAL ;
    PORT
      LAYER M5 ;
        RECT  83.52 57.916 83.544 58 ;
    END
  END dout[799]
  PIN dout[79]
    DIRECTION OUTPUT ;
    USE SIGNAL ;
    PORT
      LAYER M5 ;
        RECT  1.872 57.916 1.896 58 ;
    END
  END dout[79]
  PIN dout[7]
    DIRECTION OUTPUT ;
    USE SIGNAL ;
    PORT
      LAYER M7 ;
        RECT  79.424 57.931 79.456 58 ;
    END
  END dout[7]
  PIN dout[800]
    DIRECTION OUTPUT ;
    USE SIGNAL ;
    PORT
      LAYER M7 ;
        RECT  80.576 57.931 80.608 58 ;
    END
  END dout[800]
  PIN dout[801]
    DIRECTION OUTPUT ;
    USE SIGNAL ;
    PORT
      LAYER M7 ;
        RECT  83.008 57.931 83.04 58 ;
    END
  END dout[801]
  PIN dout[802]
    DIRECTION OUTPUT ;
    USE SIGNAL ;
    PORT
      LAYER M5 ;
        RECT  85.536 57.916 85.56 58 ;
    END
  END dout[802]
  PIN dout[803]
    DIRECTION OUTPUT ;
    USE SIGNAL ;
    PORT
      LAYER M5 ;
        RECT  65.376 57.916 65.4 58 ;
    END
  END dout[803]
  PIN dout[804]
    DIRECTION OUTPUT ;
    USE SIGNAL ;
    PORT
      LAYER M7 ;
        RECT  80.448 57.931 80.48 58 ;
    END
  END dout[804]
  PIN dout[805]
    DIRECTION OUTPUT ;
    USE SIGNAL ;
    PORT
      LAYER M5 ;
        RECT  50.256 57.916 50.28 58 ;
    END
  END dout[805]
  PIN dout[806]
    DIRECTION OUTPUT ;
    USE SIGNAL ;
    PORT
      LAYER M5 ;
        RECT  61.968 57.916 61.992 58 ;
    END
  END dout[806]
  PIN dout[807]
    DIRECTION OUTPUT ;
    USE SIGNAL ;
    PORT
      LAYER M5 ;
        RECT  50.16 57.916 50.184 58 ;
    END
  END dout[807]
  PIN dout[808]
    DIRECTION OUTPUT ;
    USE SIGNAL ;
    PORT
      LAYER M7 ;
        RECT  68.608 57.931 68.64 58 ;
    END
  END dout[808]
  PIN dout[809]
    DIRECTION OUTPUT ;
    USE SIGNAL ;
    PORT
      LAYER M7 ;
        RECT  42.304 57.931 42.336 58 ;
    END
  END dout[809]
  PIN dout[80]
    DIRECTION OUTPUT ;
    USE SIGNAL ;
    PORT
      LAYER M7 ;
        RECT  4.992 57.931 5.024 58 ;
    END
  END dout[80]
  PIN dout[810]
    DIRECTION OUTPUT ;
    USE SIGNAL ;
    PORT
      LAYER M5 ;
        RECT  46.32 57.916 46.344 58 ;
    END
  END dout[810]
  PIN dout[811]
    DIRECTION OUTPUT ;
    USE SIGNAL ;
    PORT
      LAYER M7 ;
        RECT  42.624 57.931 42.656 58 ;
    END
  END dout[811]
  PIN dout[812]
    DIRECTION OUTPUT ;
    USE SIGNAL ;
    PORT
      LAYER M7 ;
        RECT  44.032 57.931 44.064 58 ;
    END
  END dout[812]
  PIN dout[813]
    DIRECTION OUTPUT ;
    USE SIGNAL ;
    PORT
      LAYER M5 ;
        RECT  80.736 57.916 80.76 58 ;
    END
  END dout[813]
  PIN dout[814]
    DIRECTION OUTPUT ;
    USE SIGNAL ;
    PORT
      LAYER M5 ;
        RECT  49.344 57.916 49.368 58 ;
    END
  END dout[814]
  PIN dout[815]
    DIRECTION OUTPUT ;
    USE SIGNAL ;
    PORT
      LAYER M5 ;
        RECT  46.368 57.916 46.392 58 ;
    END
  END dout[815]
  PIN dout[816]
    DIRECTION OUTPUT ;
    USE SIGNAL ;
    PORT
      LAYER M5 ;
        RECT  87.984 57.916 88.008 58 ;
    END
  END dout[816]
  PIN dout[817]
    DIRECTION OUTPUT ;
    USE SIGNAL ;
    PORT
      LAYER M7 ;
        RECT  83.2 57.931 83.232 58 ;
    END
  END dout[817]
  PIN dout[818]
    DIRECTION OUTPUT ;
    USE SIGNAL ;
    PORT
      LAYER M5 ;
        RECT  81.312 57.916 81.336 58 ;
    END
  END dout[818]
  PIN dout[819]
    DIRECTION OUTPUT ;
    USE SIGNAL ;
    PORT
      LAYER M7 ;
        RECT  84.16 57.931 84.192 58 ;
    END
  END dout[819]
  PIN dout[81]
    DIRECTION OUTPUT ;
    USE SIGNAL ;
    PORT
      LAYER M5 ;
        RECT  2.688 57.916 2.712 58 ;
    END
  END dout[81]
  PIN dout[820]
    DIRECTION OUTPUT ;
    USE SIGNAL ;
    PORT
      LAYER M5 ;
        RECT  87.216 57.916 87.24 58 ;
    END
  END dout[820]
  PIN dout[821]
    DIRECTION OUTPUT ;
    USE SIGNAL ;
    PORT
      LAYER M5 ;
        RECT  88.8 57.916 88.824 58 ;
    END
  END dout[821]
  PIN dout[822]
    DIRECTION OUTPUT ;
    USE SIGNAL ;
    PORT
      LAYER M5 ;
        RECT  84.144 57.916 84.168 58 ;
    END
  END dout[822]
  PIN dout[823]
    DIRECTION OUTPUT ;
    USE SIGNAL ;
    PORT
      LAYER M7 ;
        RECT  78.336 57.931 78.368 58 ;
    END
  END dout[823]
  PIN dout[824]
    DIRECTION OUTPUT ;
    USE SIGNAL ;
    PORT
      LAYER M5 ;
        RECT  86.736 57.916 86.76 58 ;
    END
  END dout[824]
  PIN dout[825]
    DIRECTION OUTPUT ;
    USE SIGNAL ;
    PORT
      LAYER M7 ;
        RECT  80.64 57.931 80.672 58 ;
    END
  END dout[825]
  PIN dout[826]
    DIRECTION OUTPUT ;
    USE SIGNAL ;
    PORT
      LAYER M7 ;
        RECT  82.816 57.931 82.848 58 ;
    END
  END dout[826]
  PIN dout[827]
    DIRECTION OUTPUT ;
    USE SIGNAL ;
    PORT
      LAYER M5 ;
        RECT  86.352 57.916 86.376 58 ;
    END
  END dout[827]
  PIN dout[828]
    DIRECTION OUTPUT ;
    USE SIGNAL ;
    PORT
      LAYER M5 ;
        RECT  84.912 57.916 84.936 58 ;
    END
  END dout[828]
  PIN dout[829]
    DIRECTION OUTPUT ;
    USE SIGNAL ;
    PORT
      LAYER M5 ;
        RECT  81.264 57.916 81.288 58 ;
    END
  END dout[829]
  PIN dout[82]
    DIRECTION OUTPUT ;
    USE SIGNAL ;
    PORT
      LAYER M7 ;
        RECT  6.144 57.931 6.176 58 ;
    END
  END dout[82]
  PIN dout[830]
    DIRECTION OUTPUT ;
    USE SIGNAL ;
    PORT
      LAYER M5 ;
        RECT  84.672 57.916 84.696 58 ;
    END
  END dout[830]
  PIN dout[831]
    DIRECTION OUTPUT ;
    USE SIGNAL ;
    PORT
      LAYER M5 ;
        RECT  89.232 57.916 89.256 58 ;
    END
  END dout[831]
  PIN dout[832]
    DIRECTION OUTPUT ;
    USE SIGNAL ;
    PORT
      LAYER M5 ;
        RECT  85.632 57.916 85.656 58 ;
    END
  END dout[832]
  PIN dout[833]
    DIRECTION OUTPUT ;
    USE SIGNAL ;
    PORT
      LAYER M5 ;
        RECT  89.04 57.916 89.064 58 ;
    END
  END dout[833]
  PIN dout[834]
    DIRECTION OUTPUT ;
    USE SIGNAL ;
    PORT
      LAYER M5 ;
        RECT  82.032 57.916 82.056 58 ;
    END
  END dout[834]
  PIN dout[835]
    DIRECTION OUTPUT ;
    USE SIGNAL ;
    PORT
      LAYER M5 ;
        RECT  88.32 57.916 88.344 58 ;
    END
  END dout[835]
  PIN dout[836]
    DIRECTION OUTPUT ;
    USE SIGNAL ;
    PORT
      LAYER M5 ;
        RECT  81.216 57.916 81.24 58 ;
    END
  END dout[836]
  PIN dout[837]
    DIRECTION OUTPUT ;
    USE SIGNAL ;
    PORT
      LAYER M5 ;
        RECT  83.76 57.916 83.784 58 ;
    END
  END dout[837]
  PIN dout[838]
    DIRECTION OUTPUT ;
    USE SIGNAL ;
    PORT
      LAYER M5 ;
        RECT  88.272 57.916 88.296 58 ;
    END
  END dout[838]
  PIN dout[839]
    DIRECTION OUTPUT ;
    USE SIGNAL ;
    PORT
      LAYER M5 ;
        RECT  83.952 57.916 83.976 58 ;
    END
  END dout[839]
  PIN dout[83]
    DIRECTION OUTPUT ;
    USE SIGNAL ;
    PORT
      LAYER M7 ;
        RECT  4.416 57.931 4.448 58 ;
    END
  END dout[83]
  PIN dout[84]
    DIRECTION OUTPUT ;
    USE SIGNAL ;
    PORT
      LAYER M5 ;
        RECT  8.688 57.916 8.712 58 ;
    END
  END dout[84]
  PIN dout[85]
    DIRECTION OUTPUT ;
    USE SIGNAL ;
    PORT
      LAYER M5 ;
        RECT  10.464 57.916 10.488 58 ;
    END
  END dout[85]
  PIN dout[86]
    DIRECTION OUTPUT ;
    USE SIGNAL ;
    PORT
      LAYER M5 ;
        RECT  8.064 57.916 8.088 58 ;
    END
  END dout[86]
  PIN dout[87]
    DIRECTION OUTPUT ;
    USE SIGNAL ;
    PORT
      LAYER M5 ;
        RECT  1.68 57.916 1.704 58 ;
    END
  END dout[87]
  PIN dout[88]
    DIRECTION OUTPUT ;
    USE SIGNAL ;
    PORT
      LAYER M5 ;
        RECT  9.12 57.916 9.144 58 ;
    END
  END dout[88]
  PIN dout[89]
    DIRECTION OUTPUT ;
    USE SIGNAL ;
    PORT
      LAYER M5 ;
        RECT  11.472 57.916 11.496 58 ;
    END
  END dout[89]
  PIN dout[8]
    DIRECTION OUTPUT ;
    USE SIGNAL ;
    PORT
      LAYER M7 ;
        RECT  82.368 57.931 82.4 58 ;
    END
  END dout[8]
  PIN dout[90]
    DIRECTION OUTPUT ;
    USE SIGNAL ;
    PORT
      LAYER M5 ;
        RECT  15.408 57.916 15.432 58 ;
    END
  END dout[90]
  PIN dout[91]
    DIRECTION OUTPUT ;
    USE SIGNAL ;
    PORT
      LAYER M7 ;
        RECT  30.528 57.931 30.56 58 ;
    END
  END dout[91]
  PIN dout[92]
    DIRECTION OUTPUT ;
    USE SIGNAL ;
    PORT
      LAYER M5 ;
        RECT  14.688 57.916 14.712 58 ;
    END
  END dout[92]
  PIN dout[93]
    DIRECTION OUTPUT ;
    USE SIGNAL ;
    PORT
      LAYER M5 ;
        RECT  15.84 57.916 15.864 58 ;
    END
  END dout[93]
  PIN dout[94]
    DIRECTION OUTPUT ;
    USE SIGNAL ;
    PORT
      LAYER M5 ;
        RECT  17.424 57.916 17.448 58 ;
    END
  END dout[94]
  PIN dout[95]
    DIRECTION OUTPUT ;
    USE SIGNAL ;
    PORT
      LAYER M5 ;
        RECT  22.944 57.916 22.968 58 ;
    END
  END dout[95]
  PIN dout[96]
    DIRECTION OUTPUT ;
    USE SIGNAL ;
    PORT
      LAYER M7 ;
        RECT  40.832 57.931 40.864 58 ;
    END
  END dout[96]
  PIN dout[97]
    DIRECTION OUTPUT ;
    USE SIGNAL ;
    PORT
      LAYER M5 ;
        RECT  24.528 57.916 24.552 58 ;
    END
  END dout[97]
  PIN dout[98]
    DIRECTION OUTPUT ;
    USE SIGNAL ;
    PORT
      LAYER M7 ;
        RECT  20.288 57.931 20.32 58 ;
    END
  END dout[98]
  PIN dout[99]
    DIRECTION OUTPUT ;
    USE SIGNAL ;
    PORT
      LAYER M7 ;
        RECT  31.552 57.931 31.584 58 ;
    END
  END dout[99]
  PIN dout[9]
    DIRECTION OUTPUT ;
    USE SIGNAL ;
    PORT
      LAYER M7 ;
        RECT  80.832 57.931 80.864 58 ;
    END
  END dout[9]
  PIN go_check
    DIRECTION INPUT ;
    USE SIGNAL ;
    PORT
      LAYER M5 ;
        RECT  39.84 0 39.864 0.084 ;
    END
  END go_check
  PIN go_commit
    DIRECTION INPUT ;
    USE SIGNAL ;
    PORT
      LAYER M5 ;
        RECT  39.744 0 39.768 0.084 ;
    END
  END go_commit
  PIN go_repair
    DIRECTION INPUT ;
    USE SIGNAL ;
    PORT
      LAYER M5 ;
        RECT  35.76 0 35.784 0.084 ;
    END
  END go_repair
  PIN go_sel
    DIRECTION INPUT ;
    USE SIGNAL ;
    PORT
      LAYER M5 ;
        RECT  39.216 0 39.24 0.084 ;
    END
  END go_sel
  PIN gr
    DIRECTION INPUT ;
    USE SIGNAL ;
    PORT
      LAYER M7 ;
        RECT  45.76 0 45.792 0.069 ;
    END
  END gr
  PIN grc_o[0]
    DIRECTION OUTPUT ;
    USE SIGNAL ;
    PORT
      LAYER M7 ;
        RECT  48.128 0 48.16 0.069 ;
    END
  END grc_o[0]
  PIN grc_o[1]
    DIRECTION OUTPUT ;
    USE SIGNAL ;
    PORT
      LAYER M7 ;
        RECT  7.168 0 7.2 0.069 ;
    END
  END grc_o[1]
  PIN grc_o[2]
    DIRECTION OUTPUT ;
    USE SIGNAL ;
    PORT
      LAYER M5 ;
        RECT  19.92 0 19.944 0.084 ;
    END
  END grc_o[2]
  PIN grc_o[3]
    DIRECTION OUTPUT ;
    USE SIGNAL ;
    PORT
      LAYER M5 ;
        RECT  50.88 0 50.904 0.084 ;
    END
  END grc_o[3]
  PIN grc_o[4]
    DIRECTION OUTPUT ;
    USE SIGNAL ;
    PORT
      LAYER M5 ;
        RECT  50.976 0 51 0.084 ;
    END
  END grc_o[4]
  PIN ph4[0]
    DIRECTION INPUT ;
    USE SIGNAL ;
    PORT
      LAYER M5 ;
        RECT  40.752 0 40.776 0.084 ;
    END
  END ph4[0]
  PIN ph4[1]
    DIRECTION INPUT ;
    USE SIGNAL ;
    PORT
      LAYER M5 ;
        RECT  41.568 0 41.592 0.084 ;
    END
  END ph4[1]
  PIN ph4[2]
    DIRECTION INPUT ;
    USE SIGNAL ;
    PORT
      LAYER M5 ;
        RECT  40.464 0 40.488 0.084 ;
    END
  END ph4[2]
  PIN ph4[3]
    DIRECTION INPUT ;
    USE SIGNAL ;
    PORT
      LAYER M5 ;
        RECT  39.264 0 39.288 0.084 ;
    END
  END ph4[3]
  PIN q[0]
    DIRECTION OUTPUT ;
    USE SIGNAL ;
    PORT
      LAYER M5 ;
        RECT  82.272 0 82.296 0.084 ;
    END
  END q[0]
  PIN q[100]
    DIRECTION OUTPUT ;
    USE SIGNAL ;
    PORT
      LAYER M5 ;
        RECT  6 0 6.024 0.084 ;
    END
  END q[100]
  PIN q[101]
    DIRECTION OUTPUT ;
    USE SIGNAL ;
    PORT
      LAYER M7 ;
        RECT  19.072 0 19.104 0.069 ;
    END
  END q[101]
  PIN q[102]
    DIRECTION OUTPUT ;
    USE SIGNAL ;
    PORT
      LAYER M7 ;
        RECT  20.16 0 20.192 0.069 ;
    END
  END q[102]
  PIN q[103]
    DIRECTION OUTPUT ;
    USE SIGNAL ;
    PORT
      LAYER M7 ;
        RECT  16.704 0 16.736 0.069 ;
    END
  END q[103]
  PIN q[104]
    DIRECTION OUTPUT ;
    USE SIGNAL ;
    PORT
      LAYER M5 ;
        RECT  24.336 0 24.36 0.084 ;
    END
  END q[104]
  PIN q[105]
    DIRECTION OUTPUT ;
    USE SIGNAL ;
    PORT
      LAYER M5 ;
        RECT  25.056 0 25.08 0.084 ;
    END
  END q[105]
  PIN q[106]
    DIRECTION OUTPUT ;
    USE SIGNAL ;
    PORT
      LAYER M5 ;
        RECT  39.648 0 39.672 0.084 ;
    END
  END q[106]
  PIN q[107]
    DIRECTION OUTPUT ;
    USE SIGNAL ;
    PORT
      LAYER M5 ;
        RECT  28.464 0 28.488 0.084 ;
    END
  END q[107]
  PIN q[108]
    DIRECTION OUTPUT ;
    USE SIGNAL ;
    PORT
      LAYER M7 ;
        RECT  20.8 0 20.832 0.069 ;
    END
  END q[108]
  PIN q[109]
    DIRECTION OUTPUT ;
    USE SIGNAL ;
    PORT
      LAYER M5 ;
        RECT  24.912 0 24.936 0.084 ;
    END
  END q[109]
  PIN q[10]
    DIRECTION OUTPUT ;
    USE SIGNAL ;
    PORT
      LAYER M5 ;
        RECT  79.872 0 79.896 0.084 ;
    END
  END q[10]
  PIN q[110]
    DIRECTION OUTPUT ;
    USE SIGNAL ;
    PORT
      LAYER M5 ;
        RECT  39.888 0 39.912 0.084 ;
    END
  END q[110]
  PIN q[111]
    DIRECTION OUTPUT ;
    USE SIGNAL ;
    PORT
      LAYER M5 ;
        RECT  25.488 0 25.512 0.084 ;
    END
  END q[111]
  PIN q[112]
    DIRECTION OUTPUT ;
    USE SIGNAL ;
    PORT
      LAYER M5 ;
        RECT  42.192 0 42.216 0.084 ;
    END
  END q[112]
  PIN q[113]
    DIRECTION OUTPUT ;
    USE SIGNAL ;
    PORT
      LAYER M7 ;
        RECT  20.224 0 20.256 0.069 ;
    END
  END q[113]
  PIN q[114]
    DIRECTION OUTPUT ;
    USE SIGNAL ;
    PORT
      LAYER M5 ;
        RECT  23.856 0 23.88 0.084 ;
    END
  END q[114]
  PIN q[115]
    DIRECTION OUTPUT ;
    USE SIGNAL ;
    PORT
      LAYER M7 ;
        RECT  30.272 0 30.304 0.069 ;
    END
  END q[115]
  PIN q[116]
    DIRECTION OUTPUT ;
    USE SIGNAL ;
    PORT
      LAYER M5 ;
        RECT  11.856 0 11.88 0.084 ;
    END
  END q[116]
  PIN q[117]
    DIRECTION OUTPUT ;
    USE SIGNAL ;
    PORT
      LAYER M5 ;
        RECT  39.312 0 39.336 0.084 ;
    END
  END q[117]
  PIN q[118]
    DIRECTION OUTPUT ;
    USE SIGNAL ;
    PORT
      LAYER M5 ;
        RECT  27.216 0 27.24 0.084 ;
    END
  END q[118]
  PIN q[119]
    DIRECTION OUTPUT ;
    USE SIGNAL ;
    PORT
      LAYER M5 ;
        RECT  43.296 0 43.32 0.084 ;
    END
  END q[119]
  PIN q[11]
    DIRECTION OUTPUT ;
    USE SIGNAL ;
    PORT
      LAYER M7 ;
        RECT  83.712 0 83.744 0.069 ;
    END
  END q[11]
  PIN q[120]
    DIRECTION OUTPUT ;
    USE SIGNAL ;
    PORT
      LAYER M5 ;
        RECT  34.08 0 34.104 0.084 ;
    END
  END q[120]
  PIN q[121]
    DIRECTION OUTPUT ;
    USE SIGNAL ;
    PORT
      LAYER M5 ;
        RECT  39.696 0 39.72 0.084 ;
    END
  END q[121]
  PIN q[122]
    DIRECTION OUTPUT ;
    USE SIGNAL ;
    PORT
      LAYER M5 ;
        RECT  36.768 0 36.792 0.084 ;
    END
  END q[122]
  PIN q[123]
    DIRECTION OUTPUT ;
    USE SIGNAL ;
    PORT
      LAYER M5 ;
        RECT  42.432 0 42.456 0.084 ;
    END
  END q[123]
  PIN q[124]
    DIRECTION OUTPUT ;
    USE SIGNAL ;
    PORT
      LAYER M7 ;
        RECT  45.504 0 45.536 0.069 ;
    END
  END q[124]
  PIN q[125]
    DIRECTION OUTPUT ;
    USE SIGNAL ;
    PORT
      LAYER M5 ;
        RECT  39.984 0 40.008 0.084 ;
    END
  END q[125]
  PIN q[126]
    DIRECTION OUTPUT ;
    USE SIGNAL ;
    PORT
      LAYER M5 ;
        RECT  40.896 0 40.92 0.084 ;
    END
  END q[126]
  PIN q[127]
    DIRECTION OUTPUT ;
    USE SIGNAL ;
    PORT
      LAYER M7 ;
        RECT  32.512 0 32.544 0.069 ;
    END
  END q[127]
  PIN q[128]
    DIRECTION OUTPUT ;
    USE SIGNAL ;
    PORT
      LAYER M5 ;
        RECT  36.144 0 36.168 0.084 ;
    END
  END q[128]
  PIN q[129]
    DIRECTION OUTPUT ;
    USE SIGNAL ;
    PORT
      LAYER M5 ;
        RECT  33.072 0 33.096 0.084 ;
    END
  END q[129]
  PIN q[12]
    DIRECTION OUTPUT ;
    USE SIGNAL ;
    PORT
      LAYER M5 ;
        RECT  78.768 0 78.792 0.084 ;
    END
  END q[12]
  PIN q[130]
    DIRECTION OUTPUT ;
    USE SIGNAL ;
    PORT
      LAYER M7 ;
        RECT  10.88 0 10.912 0.069 ;
    END
  END q[130]
  PIN q[131]
    DIRECTION OUTPUT ;
    USE SIGNAL ;
    PORT
      LAYER M5 ;
        RECT  39.36 0 39.384 0.084 ;
    END
  END q[131]
  PIN q[132]
    DIRECTION OUTPUT ;
    USE SIGNAL ;
    PORT
      LAYER M7 ;
        RECT  8.064 0 8.096 0.069 ;
    END
  END q[132]
  PIN q[133]
    DIRECTION OUTPUT ;
    USE SIGNAL ;
    PORT
      LAYER M7 ;
        RECT  31.296 0 31.328 0.069 ;
    END
  END q[133]
  PIN q[134]
    DIRECTION OUTPUT ;
    USE SIGNAL ;
    PORT
      LAYER M7 ;
        RECT  9.408 0 9.44 0.069 ;
    END
  END q[134]
  PIN q[135]
    DIRECTION OUTPUT ;
    USE SIGNAL ;
    PORT
      LAYER M5 ;
        RECT  12.192 0 12.216 0.084 ;
    END
  END q[135]
  PIN q[136]
    DIRECTION OUTPUT ;
    USE SIGNAL ;
    PORT
      LAYER M7 ;
        RECT  7.872 0 7.904 0.069 ;
    END
  END q[136]
  PIN q[137]
    DIRECTION OUTPUT ;
    USE SIGNAL ;
    PORT
      LAYER M5 ;
        RECT  26.784 0 26.808 0.084 ;
    END
  END q[137]
  PIN q[138]
    DIRECTION OUTPUT ;
    USE SIGNAL ;
    PORT
      LAYER M5 ;
        RECT  4.752 0 4.776 0.084 ;
    END
  END q[138]
  PIN q[139]
    DIRECTION OUTPUT ;
    USE SIGNAL ;
    PORT
      LAYER M7 ;
        RECT  9.664 0 9.696 0.069 ;
    END
  END q[139]
  PIN q[13]
    DIRECTION OUTPUT ;
    USE SIGNAL ;
    PORT
      LAYER M5 ;
        RECT  89.136 0 89.16 0.084 ;
    END
  END q[13]
  PIN q[140]
    DIRECTION OUTPUT ;
    USE SIGNAL ;
    PORT
      LAYER M5 ;
        RECT  2.928 0 2.952 0.084 ;
    END
  END q[140]
  PIN q[141]
    DIRECTION OUTPUT ;
    USE SIGNAL ;
    PORT
      LAYER M5 ;
        RECT  39.6 0 39.624 0.084 ;
    END
  END q[141]
  PIN q[142]
    DIRECTION OUTPUT ;
    USE SIGNAL ;
    PORT
      LAYER M5 ;
        RECT  3.312 0 3.336 0.084 ;
    END
  END q[142]
  PIN q[143]
    DIRECTION OUTPUT ;
    USE SIGNAL ;
    PORT
      LAYER M5 ;
        RECT  5.232 0 5.256 0.084 ;
    END
  END q[143]
  PIN q[144]
    DIRECTION OUTPUT ;
    USE SIGNAL ;
    PORT
      LAYER M5 ;
        RECT  1.68 0 1.704 0.084 ;
    END
  END q[144]
  PIN q[145]
    DIRECTION OUTPUT ;
    USE SIGNAL ;
    PORT
      LAYER M7 ;
        RECT  33.472 0 33.504 0.069 ;
    END
  END q[145]
  PIN q[146]
    DIRECTION OUTPUT ;
    USE SIGNAL ;
    PORT
      LAYER M5 ;
        RECT  5.04 0 5.064 0.084 ;
    END
  END q[146]
  PIN q[147]
    DIRECTION OUTPUT ;
    USE SIGNAL ;
    PORT
      LAYER M5 ;
        RECT  4.896 0 4.92 0.084 ;
    END
  END q[147]
  PIN q[148]
    DIRECTION OUTPUT ;
    USE SIGNAL ;
    PORT
      LAYER M7 ;
        RECT  6.848 0 6.88 0.069 ;
    END
  END q[148]
  PIN q[149]
    DIRECTION OUTPUT ;
    USE SIGNAL ;
    PORT
      LAYER M5 ;
        RECT  3.552 0 3.576 0.084 ;
    END
  END q[149]
  PIN q[14]
    DIRECTION OUTPUT ;
    USE SIGNAL ;
    PORT
      LAYER M5 ;
        RECT  79.392 0 79.416 0.084 ;
    END
  END q[14]
  PIN q[150]
    DIRECTION OUTPUT ;
    USE SIGNAL ;
    PORT
      LAYER M7 ;
        RECT  31.36 0 31.392 0.069 ;
    END
  END q[150]
  PIN q[151]
    DIRECTION OUTPUT ;
    USE SIGNAL ;
    PORT
      LAYER M5 ;
        RECT  38.544 0 38.568 0.084 ;
    END
  END q[151]
  PIN q[152]
    DIRECTION OUTPUT ;
    USE SIGNAL ;
    PORT
      LAYER M7 ;
        RECT  28.928 0 28.96 0.069 ;
    END
  END q[152]
  PIN q[153]
    DIRECTION OUTPUT ;
    USE SIGNAL ;
    PORT
      LAYER M7 ;
        RECT  29.056 0 29.088 0.069 ;
    END
  END q[153]
  PIN q[154]
    DIRECTION OUTPUT ;
    USE SIGNAL ;
    PORT
      LAYER M5 ;
        RECT  27.84 0 27.864 0.084 ;
    END
  END q[154]
  PIN q[155]
    DIRECTION OUTPUT ;
    USE SIGNAL ;
    PORT
      LAYER M7 ;
        RECT  28.864 0 28.896 0.069 ;
    END
  END q[155]
  PIN q[156]
    DIRECTION OUTPUT ;
    USE SIGNAL ;
    PORT
      LAYER M7 ;
        RECT  30.336 0 30.368 0.069 ;
    END
  END q[156]
  PIN q[157]
    DIRECTION OUTPUT ;
    USE SIGNAL ;
    PORT
      LAYER M5 ;
        RECT  33.984 0 34.008 0.084 ;
    END
  END q[157]
  PIN q[158]
    DIRECTION OUTPUT ;
    USE SIGNAL ;
    PORT
      LAYER M5 ;
        RECT  23.52 0 23.544 0.084 ;
    END
  END q[158]
  PIN q[159]
    DIRECTION OUTPUT ;
    USE SIGNAL ;
    PORT
      LAYER M5 ;
        RECT  24.864 0 24.888 0.084 ;
    END
  END q[159]
  PIN q[15]
    DIRECTION OUTPUT ;
    USE SIGNAL ;
    PORT
      LAYER M7 ;
        RECT  84.928 0 84.96 0.069 ;
    END
  END q[15]
  PIN q[160]
    DIRECTION OUTPUT ;
    USE SIGNAL ;
    PORT
      LAYER M5 ;
        RECT  39.408 0 39.432 0.084 ;
    END
  END q[160]
  PIN q[161]
    DIRECTION OUTPUT ;
    USE SIGNAL ;
    PORT
      LAYER M5 ;
        RECT  34.128 0 34.152 0.084 ;
    END
  END q[161]
  PIN q[162]
    DIRECTION OUTPUT ;
    USE SIGNAL ;
    PORT
      LAYER M7 ;
        RECT  30.208 0 30.24 0.069 ;
    END
  END q[162]
  PIN q[163]
    DIRECTION OUTPUT ;
    USE SIGNAL ;
    PORT
      LAYER M5 ;
        RECT  44.64 0 44.664 0.084 ;
    END
  END q[163]
  PIN q[164]
    DIRECTION OUTPUT ;
    USE SIGNAL ;
    PORT
      LAYER M7 ;
        RECT  31.616 0 31.648 0.069 ;
    END
  END q[164]
  PIN q[165]
    DIRECTION OUTPUT ;
    USE SIGNAL ;
    PORT
      LAYER M5 ;
        RECT  27.408 0 27.432 0.084 ;
    END
  END q[165]
  PIN q[166]
    DIRECTION OUTPUT ;
    USE SIGNAL ;
    PORT
      LAYER M5 ;
        RECT  25.152 0 25.176 0.084 ;
    END
  END q[166]
  PIN q[167]
    DIRECTION OUTPUT ;
    USE SIGNAL ;
    PORT
      LAYER M5 ;
        RECT  35.856 0 35.88 0.084 ;
    END
  END q[167]
  PIN q[168]
    DIRECTION OUTPUT ;
    USE SIGNAL ;
    PORT
      LAYER M5 ;
        RECT  34.896 0 34.92 0.084 ;
    END
  END q[168]
  PIN q[169]
    DIRECTION OUTPUT ;
    USE SIGNAL ;
    PORT
      LAYER M5 ;
        RECT  1.872 0 1.896 0.084 ;
    END
  END q[169]
  PIN q[16]
    DIRECTION OUTPUT ;
    USE SIGNAL ;
    PORT
      LAYER M5 ;
        RECT  80.304 0 80.328 0.084 ;
    END
  END q[16]
  PIN q[170]
    DIRECTION OUTPUT ;
    USE SIGNAL ;
    PORT
      LAYER M5 ;
        RECT  13.104 0 13.128 0.084 ;
    END
  END q[170]
  PIN q[171]
    DIRECTION OUTPUT ;
    USE SIGNAL ;
    PORT
      LAYER M5 ;
        RECT  41.616 0 41.64 0.084 ;
    END
  END q[171]
  PIN q[172]
    DIRECTION OUTPUT ;
    USE SIGNAL ;
    PORT
      LAYER M5 ;
        RECT  37.872 0 37.896 0.084 ;
    END
  END q[172]
  PIN q[173]
    DIRECTION OUTPUT ;
    USE SIGNAL ;
    PORT
      LAYER M5 ;
        RECT  2.112 0 2.136 0.084 ;
    END
  END q[173]
  PIN q[174]
    DIRECTION OUTPUT ;
    USE SIGNAL ;
    PORT
      LAYER M5 ;
        RECT  39.504 0 39.528 0.084 ;
    END
  END q[174]
  PIN q[175]
    DIRECTION OUTPUT ;
    USE SIGNAL ;
    PORT
      LAYER M5 ;
        RECT  37.728 0 37.752 0.084 ;
    END
  END q[175]
  PIN q[176]
    DIRECTION OUTPUT ;
    USE SIGNAL ;
    PORT
      LAYER M5 ;
        RECT  37.296 0 37.32 0.084 ;
    END
  END q[176]
  PIN q[177]
    DIRECTION OUTPUT ;
    USE SIGNAL ;
    PORT
      LAYER M7 ;
        RECT  32 0 32.032 0.069 ;
    END
  END q[177]
  PIN q[178]
    DIRECTION OUTPUT ;
    USE SIGNAL ;
    PORT
      LAYER M5 ;
        RECT  39.552 0 39.576 0.084 ;
    END
  END q[178]
  PIN q[179]
    DIRECTION OUTPUT ;
    USE SIGNAL ;
    PORT
      LAYER M5 ;
        RECT  2.64 0 2.664 0.084 ;
    END
  END q[179]
  PIN q[17]
    DIRECTION OUTPUT ;
    USE SIGNAL ;
    PORT
      LAYER M7 ;
        RECT  84.544 0 84.576 0.069 ;
    END
  END q[17]
  PIN q[180]
    DIRECTION OUTPUT ;
    USE SIGNAL ;
    PORT
      LAYER M5 ;
        RECT  36.432 0 36.456 0.084 ;
    END
  END q[180]
  PIN q[181]
    DIRECTION OUTPUT ;
    USE SIGNAL ;
    PORT
      LAYER M5 ;
        RECT  36.72 0 36.744 0.084 ;
    END
  END q[181]
  PIN q[182]
    DIRECTION OUTPUT ;
    USE SIGNAL ;
    PORT
      LAYER M5 ;
        RECT  36.336 0 36.36 0.084 ;
    END
  END q[182]
  PIN q[183]
    DIRECTION OUTPUT ;
    USE SIGNAL ;
    PORT
      LAYER M5 ;
        RECT  38.496 0 38.52 0.084 ;
    END
  END q[183]
  PIN q[184]
    DIRECTION OUTPUT ;
    USE SIGNAL ;
    PORT
      LAYER M5 ;
        RECT  39.12 0 39.144 0.084 ;
    END
  END q[184]
  PIN q[185]
    DIRECTION OUTPUT ;
    USE SIGNAL ;
    PORT
      LAYER M7 ;
        RECT  28.992 0 29.024 0.069 ;
    END
  END q[185]
  PIN q[186]
    DIRECTION OUTPUT ;
    USE SIGNAL ;
    PORT
      LAYER M5 ;
        RECT  13.584 0 13.608 0.084 ;
    END
  END q[186]
  PIN q[187]
    DIRECTION OUTPUT ;
    USE SIGNAL ;
    PORT
      LAYER M5 ;
        RECT  35.808 0 35.832 0.084 ;
    END
  END q[187]
  PIN q[188]
    DIRECTION OUTPUT ;
    USE SIGNAL ;
    PORT
      LAYER M5 ;
        RECT  17.28 0 17.304 0.084 ;
    END
  END q[188]
  PIN q[189]
    DIRECTION OUTPUT ;
    USE SIGNAL ;
    PORT
      LAYER M5 ;
        RECT  22.32 0 22.344 0.084 ;
    END
  END q[189]
  PIN q[18]
    DIRECTION OUTPUT ;
    USE SIGNAL ;
    PORT
      LAYER M5 ;
        RECT  77.52 0 77.544 0.084 ;
    END
  END q[18]
  PIN q[190]
    DIRECTION OUTPUT ;
    USE SIGNAL ;
    PORT
      LAYER M7 ;
        RECT  31.808 0 31.84 0.069 ;
    END
  END q[190]
  PIN q[191]
    DIRECTION OUTPUT ;
    USE SIGNAL ;
    PORT
      LAYER M7 ;
        RECT  32.384 0 32.416 0.069 ;
    END
  END q[191]
  PIN q[192]
    DIRECTION OUTPUT ;
    USE SIGNAL ;
    PORT
      LAYER M5 ;
        RECT  54.384 0 54.408 0.084 ;
    END
  END q[192]
  PIN q[193]
    DIRECTION OUTPUT ;
    USE SIGNAL ;
    PORT
      LAYER M5 ;
        RECT  77.568 0 77.592 0.084 ;
    END
  END q[193]
  PIN q[194]
    DIRECTION OUTPUT ;
    USE SIGNAL ;
    PORT
      LAYER M7 ;
        RECT  60.096 0 60.128 0.069 ;
    END
  END q[194]
  PIN q[195]
    DIRECTION OUTPUT ;
    USE SIGNAL ;
    PORT
      LAYER M7 ;
        RECT  83.008 0 83.04 0.069 ;
    END
  END q[195]
  PIN q[196]
    DIRECTION OUTPUT ;
    USE SIGNAL ;
    PORT
      LAYER M7 ;
        RECT  47.296 0 47.328 0.069 ;
    END
  END q[196]
  PIN q[197]
    DIRECTION OUTPUT ;
    USE SIGNAL ;
    PORT
      LAYER M5 ;
        RECT  65.136 0 65.16 0.084 ;
    END
  END q[197]
  PIN q[198]
    DIRECTION OUTPUT ;
    USE SIGNAL ;
    PORT
      LAYER M5 ;
        RECT  54.144 0 54.168 0.084 ;
    END
  END q[198]
  PIN q[199]
    DIRECTION OUTPUT ;
    USE SIGNAL ;
    PORT
      LAYER M5 ;
        RECT  62.736 0 62.76 0.084 ;
    END
  END q[199]
  PIN q[19]
    DIRECTION OUTPUT ;
    USE SIGNAL ;
    PORT
      LAYER M7 ;
        RECT  82.624 0 82.656 0.069 ;
    END
  END q[19]
  PIN q[1]
    DIRECTION OUTPUT ;
    USE SIGNAL ;
    PORT
      LAYER M7 ;
        RECT  85.568 0 85.6 0.069 ;
    END
  END q[1]
  PIN q[200]
    DIRECTION OUTPUT ;
    USE SIGNAL ;
    PORT
      LAYER M7 ;
        RECT  58.624 0 58.656 0.069 ;
    END
  END q[200]
  PIN q[201]
    DIRECTION OUTPUT ;
    USE SIGNAL ;
    PORT
      LAYER M7 ;
        RECT  56.192 0 56.224 0.069 ;
    END
  END q[201]
  PIN q[202]
    DIRECTION OUTPUT ;
    USE SIGNAL ;
    PORT
      LAYER M5 ;
        RECT  52.512 0 52.536 0.084 ;
    END
  END q[202]
  PIN q[203]
    DIRECTION OUTPUT ;
    USE SIGNAL ;
    PORT
      LAYER M5 ;
        RECT  65.808 0 65.832 0.084 ;
    END
  END q[203]
  PIN q[204]
    DIRECTION OUTPUT ;
    USE SIGNAL ;
    PORT
      LAYER M5 ;
        RECT  50.928 0 50.952 0.084 ;
    END
  END q[204]
  PIN q[205]
    DIRECTION OUTPUT ;
    USE SIGNAL ;
    PORT
      LAYER M7 ;
        RECT  68.992 0 69.024 0.069 ;
    END
  END q[205]
  PIN q[206]
    DIRECTION OUTPUT ;
    USE SIGNAL ;
    PORT
      LAYER M7 ;
        RECT  68.416 0 68.448 0.069 ;
    END
  END q[206]
  PIN q[207]
    DIRECTION OUTPUT ;
    USE SIGNAL ;
    PORT
      LAYER M5 ;
        RECT  74.304 0 74.328 0.084 ;
    END
  END q[207]
  PIN q[208]
    DIRECTION OUTPUT ;
    USE SIGNAL ;
    PORT
      LAYER M7 ;
        RECT  71.808 0 71.84 0.069 ;
    END
  END q[208]
  PIN q[209]
    DIRECTION OUTPUT ;
    USE SIGNAL ;
    PORT
      LAYER M5 ;
        RECT  73.968 0 73.992 0.084 ;
    END
  END q[209]
  PIN q[20]
    DIRECTION OUTPUT ;
    USE SIGNAL ;
    PORT
      LAYER M7 ;
        RECT  83.648 0 83.68 0.069 ;
    END
  END q[20]
  PIN q[210]
    DIRECTION OUTPUT ;
    USE SIGNAL ;
    PORT
      LAYER M5 ;
        RECT  74.448 0 74.472 0.084 ;
    END
  END q[210]
  PIN q[211]
    DIRECTION OUTPUT ;
    USE SIGNAL ;
    PORT
      LAYER M5 ;
        RECT  74.976 0 75 0.084 ;
    END
  END q[211]
  PIN q[212]
    DIRECTION OUTPUT ;
    USE SIGNAL ;
    PORT
      LAYER M5 ;
        RECT  71.952 0 71.976 0.084 ;
    END
  END q[212]
  PIN q[213]
    DIRECTION OUTPUT ;
    USE SIGNAL ;
    PORT
      LAYER M7 ;
        RECT  84.032 0 84.064 0.069 ;
    END
  END q[213]
  PIN q[214]
    DIRECTION OUTPUT ;
    USE SIGNAL ;
    PORT
      LAYER M5 ;
        RECT  80.496 0 80.52 0.084 ;
    END
  END q[214]
  PIN q[215]
    DIRECTION OUTPUT ;
    USE SIGNAL ;
    PORT
      LAYER M5 ;
        RECT  87.408 0 87.432 0.084 ;
    END
  END q[215]
  PIN q[216]
    DIRECTION OUTPUT ;
    USE SIGNAL ;
    PORT
      LAYER M5 ;
        RECT  82.128 0 82.152 0.084 ;
    END
  END q[216]
  PIN q[217]
    DIRECTION OUTPUT ;
    USE SIGNAL ;
    PORT
      LAYER M5 ;
        RECT  87.168 0 87.192 0.084 ;
    END
  END q[217]
  PIN q[218]
    DIRECTION OUTPUT ;
    USE SIGNAL ;
    PORT
      LAYER M5 ;
        RECT  88.224 0 88.248 0.084 ;
    END
  END q[218]
  PIN q[219]
    DIRECTION OUTPUT ;
    USE SIGNAL ;
    PORT
      LAYER M7 ;
        RECT  84.16 0 84.192 0.069 ;
    END
  END q[219]
  PIN q[21]
    DIRECTION OUTPUT ;
    USE SIGNAL ;
    PORT
      LAYER M7 ;
        RECT  83.52 0 83.552 0.069 ;
    END
  END q[21]
  PIN q[220]
    DIRECTION OUTPUT ;
    USE SIGNAL ;
    PORT
      LAYER M5 ;
        RECT  87.936 0 87.96 0.084 ;
    END
  END q[220]
  PIN q[221]
    DIRECTION OUTPUT ;
    USE SIGNAL ;
    PORT
      LAYER M5 ;
        RECT  87.12 0 87.144 0.084 ;
    END
  END q[221]
  PIN q[222]
    DIRECTION OUTPUT ;
    USE SIGNAL ;
    PORT
      LAYER M5 ;
        RECT  87.264 0 87.288 0.084 ;
    END
  END q[222]
  PIN q[223]
    DIRECTION OUTPUT ;
    USE SIGNAL ;
    PORT
      LAYER M7 ;
        RECT  84.224 0 84.256 0.069 ;
    END
  END q[223]
  PIN q[224]
    DIRECTION OUTPUT ;
    USE SIGNAL ;
    PORT
      LAYER M5 ;
        RECT  87.792 0 87.816 0.084 ;
    END
  END q[224]
  PIN q[225]
    DIRECTION OUTPUT ;
    USE SIGNAL ;
    PORT
      LAYER M7 ;
        RECT  84.992 0 85.024 0.069 ;
    END
  END q[225]
  PIN q[226]
    DIRECTION OUTPUT ;
    USE SIGNAL ;
    PORT
      LAYER M7 ;
        RECT  85.376 0 85.408 0.069 ;
    END
  END q[226]
  PIN q[227]
    DIRECTION OUTPUT ;
    USE SIGNAL ;
    PORT
      LAYER M5 ;
        RECT  89.04 0 89.064 0.084 ;
    END
  END q[227]
  PIN q[228]
    DIRECTION OUTPUT ;
    USE SIGNAL ;
    PORT
      LAYER M7 ;
        RECT  84.096 0 84.128 0.069 ;
    END
  END q[228]
  PIN q[229]
    DIRECTION OUTPUT ;
    USE SIGNAL ;
    PORT
      LAYER M5 ;
        RECT  88.848 0 88.872 0.084 ;
    END
  END q[229]
  PIN q[22]
    DIRECTION OUTPUT ;
    USE SIGNAL ;
    PORT
      LAYER M5 ;
        RECT  76.992 0 77.016 0.084 ;
    END
  END q[22]
  PIN q[230]
    DIRECTION OUTPUT ;
    USE SIGNAL ;
    PORT
      LAYER M7 ;
        RECT  83.776 0 83.808 0.069 ;
    END
  END q[230]
  PIN q[231]
    DIRECTION OUTPUT ;
    USE SIGNAL ;
    PORT
      LAYER M5 ;
        RECT  87.552 0 87.576 0.084 ;
    END
  END q[231]
  PIN q[232]
    DIRECTION OUTPUT ;
    USE SIGNAL ;
    PORT
      LAYER M7 ;
        RECT  84.48 0 84.512 0.069 ;
    END
  END q[232]
  PIN q[233]
    DIRECTION OUTPUT ;
    USE SIGNAL ;
    PORT
      LAYER M7 ;
        RECT  83.136 0 83.168 0.069 ;
    END
  END q[233]
  PIN q[234]
    DIRECTION OUTPUT ;
    USE SIGNAL ;
    PORT
      LAYER M5 ;
        RECT  81.264 0 81.288 0.084 ;
    END
  END q[234]
  PIN q[235]
    DIRECTION OUTPUT ;
    USE SIGNAL ;
    PORT
      LAYER M5 ;
        RECT  87.6 0 87.624 0.084 ;
    END
  END q[235]
  PIN q[236]
    DIRECTION OUTPUT ;
    USE SIGNAL ;
    PORT
      LAYER M5 ;
        RECT  87.504 0 87.528 0.084 ;
    END
  END q[236]
  PIN q[237]
    DIRECTION OUTPUT ;
    USE SIGNAL ;
    PORT
      LAYER M7 ;
        RECT  83.584 0 83.616 0.069 ;
    END
  END q[237]
  PIN q[238]
    DIRECTION OUTPUT ;
    USE SIGNAL ;
    PORT
      LAYER M7 ;
        RECT  85.12 0 85.152 0.069 ;
    END
  END q[238]
  PIN q[239]
    DIRECTION OUTPUT ;
    USE SIGNAL ;
    PORT
      LAYER M5 ;
        RECT  82.416 0 82.44 0.084 ;
    END
  END q[239]
  PIN q[23]
    DIRECTION OUTPUT ;
    USE SIGNAL ;
    PORT
      LAYER M5 ;
        RECT  79.584 0 79.608 0.084 ;
    END
  END q[23]
  PIN q[240]
    DIRECTION OUTPUT ;
    USE SIGNAL ;
    PORT
      LAYER M5 ;
        RECT  80.592 0 80.616 0.084 ;
    END
  END q[240]
  PIN q[241]
    DIRECTION OUTPUT ;
    USE SIGNAL ;
    PORT
      LAYER M5 ;
        RECT  81.84 0 81.864 0.084 ;
    END
  END q[241]
  PIN q[242]
    DIRECTION OUTPUT ;
    USE SIGNAL ;
    PORT
      LAYER M7 ;
        RECT  85.056 0 85.088 0.069 ;
    END
  END q[242]
  PIN q[243]
    DIRECTION OUTPUT ;
    USE SIGNAL ;
    PORT
      LAYER M5 ;
        RECT  64.464 0 64.488 0.084 ;
    END
  END q[243]
  PIN q[244]
    DIRECTION OUTPUT ;
    USE SIGNAL ;
    PORT
      LAYER M5 ;
        RECT  80.544 0 80.568 0.084 ;
    END
  END q[244]
  PIN q[245]
    DIRECTION OUTPUT ;
    USE SIGNAL ;
    PORT
      LAYER M7 ;
        RECT  49.28 0 49.312 0.069 ;
    END
  END q[245]
  PIN q[246]
    DIRECTION OUTPUT ;
    USE SIGNAL ;
    PORT
      LAYER M5 ;
        RECT  60.912 0 60.936 0.084 ;
    END
  END q[246]
  PIN q[247]
    DIRECTION OUTPUT ;
    USE SIGNAL ;
    PORT
      LAYER M7 ;
        RECT  49.152 0 49.184 0.069 ;
    END
  END q[247]
  PIN q[248]
    DIRECTION OUTPUT ;
    USE SIGNAL ;
    PORT
      LAYER M7 ;
        RECT  67.136 0 67.168 0.069 ;
    END
  END q[248]
  PIN q[249]
    DIRECTION OUTPUT ;
    USE SIGNAL ;
    PORT
      LAYER M5 ;
        RECT  41.376 0 41.4 0.084 ;
    END
  END q[249]
  PIN q[24]
    DIRECTION OUTPUT ;
    USE SIGNAL ;
    PORT
      LAYER M5 ;
        RECT  81.648 0 81.672 0.084 ;
    END
  END q[24]
  PIN q[250]
    DIRECTION OUTPUT ;
    USE SIGNAL ;
    PORT
      LAYER M7 ;
        RECT  45.44 0 45.472 0.069 ;
    END
  END q[250]
  PIN q[251]
    DIRECTION OUTPUT ;
    USE SIGNAL ;
    PORT
      LAYER M5 ;
        RECT  40.848 0 40.872 0.084 ;
    END
  END q[251]
  PIN q[252]
    DIRECTION OUTPUT ;
    USE SIGNAL ;
    PORT
      LAYER M5 ;
        RECT  43.056 0 43.08 0.084 ;
    END
  END q[252]
  PIN q[253]
    DIRECTION OUTPUT ;
    USE SIGNAL ;
    PORT
      LAYER M5 ;
        RECT  88.128 0 88.152 0.084 ;
    END
  END q[253]
  PIN q[254]
    DIRECTION OUTPUT ;
    USE SIGNAL ;
    PORT
      LAYER M7 ;
        RECT  47.936 0 47.968 0.069 ;
    END
  END q[254]
  PIN q[255]
    DIRECTION OUTPUT ;
    USE SIGNAL ;
    PORT
      LAYER M7 ;
        RECT  45.056 0 45.088 0.069 ;
    END
  END q[255]
  PIN q[256]
    DIRECTION OUTPUT ;
    USE SIGNAL ;
    PORT
      LAYER M5 ;
        RECT  88.032 0 88.056 0.084 ;
    END
  END q[256]
  PIN q[257]
    DIRECTION OUTPUT ;
    USE SIGNAL ;
    PORT
      LAYER M5 ;
        RECT  81.888 0 81.912 0.084 ;
    END
  END q[257]
  PIN q[258]
    DIRECTION OUTPUT ;
    USE SIGNAL ;
    PORT
      LAYER M5 ;
        RECT  87.984 0 88.008 0.084 ;
    END
  END q[258]
  PIN q[259]
    DIRECTION OUTPUT ;
    USE SIGNAL ;
    PORT
      LAYER M5 ;
        RECT  81.456 0 81.48 0.084 ;
    END
  END q[259]
  PIN q[25]
    DIRECTION OUTPUT ;
    USE SIGNAL ;
    PORT
      LAYER M5 ;
        RECT  82.464 0 82.488 0.084 ;
    END
  END q[25]
  PIN q[260]
    DIRECTION OUTPUT ;
    USE SIGNAL ;
    PORT
      LAYER M5 ;
        RECT  88.896 0 88.92 0.084 ;
    END
  END q[260]
  PIN q[261]
    DIRECTION OUTPUT ;
    USE SIGNAL ;
    PORT
      LAYER M5 ;
        RECT  88.416 0 88.44 0.084 ;
    END
  END q[261]
  PIN q[262]
    DIRECTION OUTPUT ;
    USE SIGNAL ;
    PORT
      LAYER M7 ;
        RECT  84.608 0 84.64 0.069 ;
    END
  END q[262]
  PIN q[263]
    DIRECTION OUTPUT ;
    USE SIGNAL ;
    PORT
      LAYER M5 ;
        RECT  80.016 0 80.04 0.084 ;
    END
  END q[263]
  PIN q[264]
    DIRECTION OUTPUT ;
    USE SIGNAL ;
    PORT
      LAYER M5 ;
        RECT  88.08 0 88.104 0.084 ;
    END
  END q[264]
  PIN q[265]
    DIRECTION OUTPUT ;
    USE SIGNAL ;
    PORT
      LAYER M5 ;
        RECT  79.632 0 79.656 0.084 ;
    END
  END q[265]
  PIN q[266]
    DIRECTION OUTPUT ;
    USE SIGNAL ;
    PORT
      LAYER M5 ;
        RECT  81.552 0 81.576 0.084 ;
    END
  END q[266]
  PIN q[267]
    DIRECTION OUTPUT ;
    USE SIGNAL ;
    PORT
      LAYER M5 ;
        RECT  89.088 0 89.112 0.084 ;
    END
  END q[267]
  PIN q[268]
    DIRECTION OUTPUT ;
    USE SIGNAL ;
    PORT
      LAYER M7 ;
        RECT  84.288 0 84.32 0.069 ;
    END
  END q[268]
  PIN q[269]
    DIRECTION OUTPUT ;
    USE SIGNAL ;
    PORT
      LAYER M5 ;
        RECT  88.608 0 88.632 0.084 ;
    END
  END q[269]
  PIN q[26]
    DIRECTION OUTPUT ;
    USE SIGNAL ;
    PORT
      LAYER M5 ;
        RECT  77.04 0 77.064 0.084 ;
    END
  END q[26]
  PIN q[270]
    DIRECTION OUTPUT ;
    USE SIGNAL ;
    PORT
      LAYER M5 ;
        RECT  87.648 0 87.672 0.084 ;
    END
  END q[270]
  PIN q[271]
    DIRECTION OUTPUT ;
    USE SIGNAL ;
    PORT
      LAYER M5 ;
        RECT  88.272 0 88.296 0.084 ;
    END
  END q[271]
  PIN q[272]
    DIRECTION OUTPUT ;
    USE SIGNAL ;
    PORT
      LAYER M5 ;
        RECT  87.696 0 87.72 0.084 ;
    END
  END q[272]
  PIN q[273]
    DIRECTION OUTPUT ;
    USE SIGNAL ;
    PORT
      LAYER M5 ;
        RECT  88.368 0 88.392 0.084 ;
    END
  END q[273]
  PIN q[274]
    DIRECTION OUTPUT ;
    USE SIGNAL ;
    PORT
      LAYER M7 ;
        RECT  83.264 0 83.296 0.069 ;
    END
  END q[274]
  PIN q[275]
    DIRECTION OUTPUT ;
    USE SIGNAL ;
    PORT
      LAYER M5 ;
        RECT  88.656 0 88.68 0.084 ;
    END
  END q[275]
  PIN q[276]
    DIRECTION OUTPUT ;
    USE SIGNAL ;
    PORT
      LAYER M7 ;
        RECT  84.864 0 84.896 0.069 ;
    END
  END q[276]
  PIN q[277]
    DIRECTION OUTPUT ;
    USE SIGNAL ;
    PORT
      LAYER M7 ;
        RECT  85.44 0 85.472 0.069 ;
    END
  END q[277]
  PIN q[278]
    DIRECTION OUTPUT ;
    USE SIGNAL ;
    PORT
      LAYER M5 ;
        RECT  87.888 0 87.912 0.084 ;
    END
  END q[278]
  PIN q[279]
    DIRECTION OUTPUT ;
    USE SIGNAL ;
    PORT
      LAYER M7 ;
        RECT  84.352 0 84.384 0.069 ;
    END
  END q[279]
  PIN q[27]
    DIRECTION OUTPUT ;
    USE SIGNAL ;
    PORT
      LAYER M5 ;
        RECT  76.656 0 76.68 0.084 ;
    END
  END q[27]
  PIN q[280]
    DIRECTION OUTPUT ;
    USE SIGNAL ;
    PORT
      LAYER M5 ;
        RECT  88.944 0 88.968 0.084 ;
    END
  END q[280]
  PIN q[281]
    DIRECTION OUTPUT ;
    USE SIGNAL ;
    PORT
      LAYER M5 ;
        RECT  87.456 0 87.48 0.084 ;
    END
  END q[281]
  PIN q[282]
    DIRECTION OUTPUT ;
    USE SIGNAL ;
    PORT
      LAYER M5 ;
        RECT  88.704 0 88.728 0.084 ;
    END
  END q[282]
  PIN q[283]
    DIRECTION OUTPUT ;
    USE SIGNAL ;
    PORT
      LAYER M5 ;
        RECT  88.176 0 88.2 0.084 ;
    END
  END q[283]
  PIN q[284]
    DIRECTION OUTPUT ;
    USE SIGNAL ;
    PORT
      LAYER M5 ;
        RECT  88.56 0 88.584 0.084 ;
    END
  END q[284]
  PIN q[285]
    DIRECTION OUTPUT ;
    USE SIGNAL ;
    PORT
      LAYER M7 ;
        RECT  83.904 0 83.936 0.069 ;
    END
  END q[285]
  PIN q[286]
    DIRECTION OUTPUT ;
    USE SIGNAL ;
    PORT
      LAYER M7 ;
        RECT  84.8 0 84.832 0.069 ;
    END
  END q[286]
  PIN q[287]
    DIRECTION OUTPUT ;
    USE SIGNAL ;
    PORT
      LAYER M7 ;
        RECT  83.072 0 83.104 0.069 ;
    END
  END q[287]
  PIN q[288]
    DIRECTION OUTPUT ;
    USE SIGNAL ;
    PORT
      LAYER M5 ;
        RECT  87.216 0 87.24 0.084 ;
    END
  END q[288]
  PIN q[289]
    DIRECTION OUTPUT ;
    USE SIGNAL ;
    PORT
      LAYER M7 ;
        RECT  84.416 0 84.448 0.069 ;
    END
  END q[289]
  PIN q[28]
    DIRECTION OUTPUT ;
    USE SIGNAL ;
    PORT
      LAYER M5 ;
        RECT  75.168 0 75.192 0.084 ;
    END
  END q[28]
  PIN q[290]
    DIRECTION OUTPUT ;
    USE SIGNAL ;
    PORT
      LAYER M7 ;
        RECT  85.312 0 85.344 0.069 ;
    END
  END q[290]
  PIN q[291]
    DIRECTION OUTPUT ;
    USE SIGNAL ;
    PORT
      LAYER M5 ;
        RECT  79.056 0 79.08 0.084 ;
    END
  END q[291]
  PIN q[292]
    DIRECTION OUTPUT ;
    USE SIGNAL ;
    PORT
      LAYER M5 ;
        RECT  80.256 0 80.28 0.084 ;
    END
  END q[292]
  PIN q[293]
    DIRECTION OUTPUT ;
    USE SIGNAL ;
    PORT
      LAYER M5 ;
        RECT  82.176 0 82.2 0.084 ;
    END
  END q[293]
  PIN q[294]
    DIRECTION OUTPUT ;
    USE SIGNAL ;
    PORT
      LAYER M7 ;
        RECT  84.736 0 84.768 0.069 ;
    END
  END q[294]
  PIN q[295]
    DIRECTION OUTPUT ;
    USE SIGNAL ;
    PORT
      LAYER M7 ;
        RECT  83.968 0 84 0.069 ;
    END
  END q[295]
  PIN q[296]
    DIRECTION OUTPUT ;
    USE SIGNAL ;
    PORT
      LAYER M5 ;
        RECT  88.752 0 88.776 0.084 ;
    END
  END q[296]
  PIN q[297]
    DIRECTION OUTPUT ;
    USE SIGNAL ;
    PORT
      LAYER M5 ;
        RECT  80.736 0 80.76 0.084 ;
    END
  END q[297]
  PIN q[298]
    DIRECTION OUTPUT ;
    USE SIGNAL ;
    PORT
      LAYER M5 ;
        RECT  80.112 0 80.136 0.084 ;
    END
  END q[298]
  PIN q[299]
    DIRECTION OUTPUT ;
    USE SIGNAL ;
    PORT
      LAYER M5 ;
        RECT  82.32 0 82.344 0.084 ;
    END
  END q[299]
  PIN q[29]
    DIRECTION OUTPUT ;
    USE SIGNAL ;
    PORT
      LAYER M5 ;
        RECT  77.184 0 77.208 0.084 ;
    END
  END q[29]
  PIN q[2]
    DIRECTION OUTPUT ;
    USE SIGNAL ;
    PORT
      LAYER M5 ;
        RECT  80.688 0 80.712 0.084 ;
    END
  END q[2]
  PIN q[300]
    DIRECTION OUTPUT ;
    USE SIGNAL ;
    PORT
      LAYER M5 ;
        RECT  76.896 0 76.92 0.084 ;
    END
  END q[300]
  PIN q[301]
    DIRECTION OUTPUT ;
    USE SIGNAL ;
    PORT
      LAYER M5 ;
        RECT  79.68 0 79.704 0.084 ;
    END
  END q[301]
  PIN q[302]
    DIRECTION OUTPUT ;
    USE SIGNAL ;
    PORT
      LAYER M5 ;
        RECT  77.088 0 77.112 0.084 ;
    END
  END q[302]
  PIN q[303]
    DIRECTION OUTPUT ;
    USE SIGNAL ;
    PORT
      LAYER M5 ;
        RECT  81.216 0 81.24 0.084 ;
    END
  END q[303]
  PIN q[304]
    DIRECTION OUTPUT ;
    USE SIGNAL ;
    PORT
      LAYER M5 ;
        RECT  73.488 0 73.512 0.084 ;
    END
  END q[304]
  PIN q[305]
    DIRECTION OUTPUT ;
    USE SIGNAL ;
    PORT
      LAYER M5 ;
        RECT  82.368 0 82.392 0.084 ;
    END
  END q[305]
  PIN q[306]
    DIRECTION OUTPUT ;
    USE SIGNAL ;
    PORT
      LAYER M7 ;
        RECT  84.672 0 84.704 0.069 ;
    END
  END q[306]
  PIN q[307]
    DIRECTION OUTPUT ;
    USE SIGNAL ;
    PORT
      LAYER M5 ;
        RECT  63.6 0 63.624 0.084 ;
    END
  END q[307]
  PIN q[308]
    DIRECTION OUTPUT ;
    USE SIGNAL ;
    PORT
      LAYER M5 ;
        RECT  72.144 0 72.168 0.084 ;
    END
  END q[308]
  PIN q[309]
    DIRECTION OUTPUT ;
    USE SIGNAL ;
    PORT
      LAYER M5 ;
        RECT  87.744 0 87.768 0.084 ;
    END
  END q[309]
  PIN q[30]
    DIRECTION OUTPUT ;
    USE SIGNAL ;
    PORT
      LAYER M5 ;
        RECT  78.336 0 78.36 0.084 ;
    END
  END q[30]
  PIN q[310]
    DIRECTION OUTPUT ;
    USE SIGNAL ;
    PORT
      LAYER M5 ;
        RECT  87.312 0 87.336 0.084 ;
    END
  END q[310]
  PIN q[311]
    DIRECTION OUTPUT ;
    USE SIGNAL ;
    PORT
      LAYER M5 ;
        RECT  88.32 0 88.344 0.084 ;
    END
  END q[311]
  PIN q[312]
    DIRECTION OUTPUT ;
    USE SIGNAL ;
    PORT
      LAYER M5 ;
        RECT  88.992 0 89.016 0.084 ;
    END
  END q[312]
  PIN q[313]
    DIRECTION OUTPUT ;
    USE SIGNAL ;
    PORT
      LAYER M5 ;
        RECT  87.84 0 87.864 0.084 ;
    END
  END q[313]
  PIN q[314]
    DIRECTION OUTPUT ;
    USE SIGNAL ;
    PORT
      LAYER M7 ;
        RECT  46.976 0 47.008 0.069 ;
    END
  END q[314]
  PIN q[315]
    DIRECTION OUTPUT ;
    USE SIGNAL ;
    PORT
      LAYER M5 ;
        RECT  88.8 0 88.824 0.084 ;
    END
  END q[315]
  PIN q[316]
    DIRECTION OUTPUT ;
    USE SIGNAL ;
    PORT
      LAYER M7 ;
        RECT  85.184 0 85.216 0.069 ;
    END
  END q[316]
  PIN q[317]
    DIRECTION OUTPUT ;
    USE SIGNAL ;
    PORT
      LAYER M5 ;
        RECT  49.776 0 49.8 0.084 ;
    END
  END q[317]
  PIN q[318]
    DIRECTION OUTPUT ;
    USE SIGNAL ;
    PORT
      LAYER M5 ;
        RECT  88.512 0 88.536 0.084 ;
    END
  END q[318]
  PIN q[319]
    DIRECTION OUTPUT ;
    USE SIGNAL ;
    PORT
      LAYER M5 ;
        RECT  88.464 0 88.488 0.084 ;
    END
  END q[319]
  PIN q[31]
    DIRECTION OUTPUT ;
    USE SIGNAL ;
    PORT
      LAYER M5 ;
        RECT  76.272 0 76.296 0.084 ;
    END
  END q[31]
  PIN q[32]
    DIRECTION OUTPUT ;
    USE SIGNAL ;
    PORT
      LAYER M5 ;
        RECT  72.816 0 72.84 0.084 ;
    END
  END q[32]
  PIN q[33]
    DIRECTION OUTPUT ;
    USE SIGNAL ;
    PORT
      LAYER M5 ;
        RECT  82.704 0 82.728 0.084 ;
    END
  END q[33]
  PIN q[34]
    DIRECTION OUTPUT ;
    USE SIGNAL ;
    PORT
      LAYER M5 ;
        RECT  78.192 0 78.216 0.084 ;
    END
  END q[34]
  PIN q[35]
    DIRECTION OUTPUT ;
    USE SIGNAL ;
    PORT
      LAYER M5 ;
        RECT  27.648 0 27.672 0.084 ;
    END
  END q[35]
  PIN q[36]
    DIRECTION OUTPUT ;
    USE SIGNAL ;
    PORT
      LAYER M7 ;
        RECT  69.184 0 69.216 0.069 ;
    END
  END q[36]
  PIN q[37]
    DIRECTION OUTPUT ;
    USE SIGNAL ;
    PORT
      LAYER M7 ;
        RECT  71.104 0 71.136 0.069 ;
    END
  END q[37]
  PIN q[38]
    DIRECTION OUTPUT ;
    USE SIGNAL ;
    PORT
      LAYER M5 ;
        RECT  81.12 0 81.144 0.084 ;
    END
  END q[38]
  PIN q[39]
    DIRECTION OUTPUT ;
    USE SIGNAL ;
    PORT
      LAYER M5 ;
        RECT  75.36 0 75.384 0.084 ;
    END
  END q[39]
  PIN q[3]
    DIRECTION OUTPUT ;
    USE SIGNAL ;
    PORT
      LAYER M5 ;
        RECT  87.36 0 87.384 0.084 ;
    END
  END q[3]
  PIN q[40]
    DIRECTION OUTPUT ;
    USE SIGNAL ;
    PORT
      LAYER M5 ;
        RECT  74.928 0 74.952 0.084 ;
    END
  END q[40]
  PIN q[41]
    DIRECTION OUTPUT ;
    USE SIGNAL ;
    PORT
      LAYER M5 ;
        RECT  27.792 0 27.816 0.084 ;
    END
  END q[41]
  PIN q[42]
    DIRECTION OUTPUT ;
    USE SIGNAL ;
    PORT
      LAYER M7 ;
        RECT  30.144 0 30.176 0.069 ;
    END
  END q[42]
  PIN q[43]
    DIRECTION OUTPUT ;
    USE SIGNAL ;
    PORT
      LAYER M5 ;
        RECT  72.72 0 72.744 0.084 ;
    END
  END q[43]
  PIN q[44]
    DIRECTION OUTPUT ;
    USE SIGNAL ;
    PORT
      LAYER M7 ;
        RECT  70.912 0 70.944 0.069 ;
    END
  END q[44]
  PIN q[45]
    DIRECTION OUTPUT ;
    USE SIGNAL ;
    PORT
      LAYER M7 ;
        RECT  30.08 0 30.112 0.069 ;
    END
  END q[45]
  PIN q[46]
    DIRECTION OUTPUT ;
    USE SIGNAL ;
    PORT
      LAYER M5 ;
        RECT  73.536 0 73.56 0.084 ;
    END
  END q[46]
  PIN q[47]
    DIRECTION OUTPUT ;
    USE SIGNAL ;
    PORT
      LAYER M5 ;
        RECT  27.12 0 27.144 0.084 ;
    END
  END q[47]
  PIN q[48]
    DIRECTION OUTPUT ;
    USE SIGNAL ;
    PORT
      LAYER M7 ;
        RECT  71.36 0 71.392 0.069 ;
    END
  END q[48]
  PIN q[49]
    DIRECTION OUTPUT ;
    USE SIGNAL ;
    PORT
      LAYER M7 ;
        RECT  85.248 0 85.28 0.069 ;
    END
  END q[49]
  PIN q[4]
    DIRECTION OUTPUT ;
    USE SIGNAL ;
    PORT
      LAYER M5 ;
        RECT  79.152 0 79.176 0.084 ;
    END
  END q[4]
  PIN q[50]
    DIRECTION OUTPUT ;
    USE SIGNAL ;
    PORT
      LAYER M5 ;
        RECT  80.16 0 80.184 0.084 ;
    END
  END q[50]
  PIN q[51]
    DIRECTION OUTPUT ;
    USE SIGNAL ;
    PORT
      LAYER M7 ;
        RECT  30.592 0 30.624 0.069 ;
    END
  END q[51]
  PIN q[52]
    DIRECTION OUTPUT ;
    USE SIGNAL ;
    PORT
      LAYER M7 ;
        RECT  83.84 0 83.872 0.069 ;
    END
  END q[52]
  PIN q[53]
    DIRECTION OUTPUT ;
    USE SIGNAL ;
    PORT
      LAYER M5 ;
        RECT  81.024 0 81.048 0.084 ;
    END
  END q[53]
  PIN q[54]
    DIRECTION OUTPUT ;
    USE SIGNAL ;
    PORT
      LAYER M5 ;
        RECT  24.288 0 24.312 0.084 ;
    END
  END q[54]
  PIN q[55]
    DIRECTION OUTPUT ;
    USE SIGNAL ;
    PORT
      LAYER M5 ;
        RECT  77.856 0 77.88 0.084 ;
    END
  END q[55]
  PIN q[56]
    DIRECTION OUTPUT ;
    USE SIGNAL ;
    PORT
      LAYER M5 ;
        RECT  78.96 0 78.984 0.084 ;
    END
  END q[56]
  PIN q[57]
    DIRECTION OUTPUT ;
    USE SIGNAL ;
    PORT
      LAYER M7 ;
        RECT  31.104 0 31.136 0.069 ;
    END
  END q[57]
  PIN q[58]
    DIRECTION OUTPUT ;
    USE SIGNAL ;
    PORT
      LAYER M5 ;
        RECT  80.64 0 80.664 0.084 ;
    END
  END q[58]
  PIN q[59]
    DIRECTION OUTPUT ;
    USE SIGNAL ;
    PORT
      LAYER M5 ;
        RECT  73.584 0 73.608 0.084 ;
    END
  END q[59]
  PIN q[5]
    DIRECTION OUTPUT ;
    USE SIGNAL ;
    PORT
      LAYER M7 ;
        RECT  85.504 0 85.536 0.069 ;
    END
  END q[5]
  PIN q[60]
    DIRECTION OUTPUT ;
    USE SIGNAL ;
    PORT
      LAYER M5 ;
        RECT  78.144 0 78.168 0.084 ;
    END
  END q[60]
  PIN q[61]
    DIRECTION OUTPUT ;
    USE SIGNAL ;
    PORT
      LAYER M5 ;
        RECT  77.616 0 77.64 0.084 ;
    END
  END q[61]
  PIN q[62]
    DIRECTION OUTPUT ;
    USE SIGNAL ;
    PORT
      LAYER M5 ;
        RECT  75.456 0 75.48 0.084 ;
    END
  END q[62]
  PIN q[63]
    DIRECTION OUTPUT ;
    USE SIGNAL ;
    PORT
      LAYER M5 ;
        RECT  75.408 0 75.432 0.084 ;
    END
  END q[63]
  PIN q[64]
    DIRECTION OUTPUT ;
    USE SIGNAL ;
    PORT
      LAYER M5 ;
        RECT  14.688 0 14.712 0.084 ;
    END
  END q[64]
  PIN q[65]
    DIRECTION OUTPUT ;
    USE SIGNAL ;
    PORT
      LAYER M5 ;
        RECT  14.304 0 14.328 0.084 ;
    END
  END q[65]
  PIN q[66]
    DIRECTION OUTPUT ;
    USE SIGNAL ;
    PORT
      LAYER M5 ;
        RECT  33.12 0 33.144 0.084 ;
    END
  END q[66]
  PIN q[67]
    DIRECTION OUTPUT ;
    USE SIGNAL ;
    PORT
      LAYER M5 ;
        RECT  34.32 0 34.344 0.084 ;
    END
  END q[67]
  PIN q[68]
    DIRECTION OUTPUT ;
    USE SIGNAL ;
    PORT
      LAYER M5 ;
        RECT  12.144 0 12.168 0.084 ;
    END
  END q[68]
  PIN q[69]
    DIRECTION OUTPUT ;
    USE SIGNAL ;
    PORT
      LAYER M7 ;
        RECT  10.56 0 10.592 0.069 ;
    END
  END q[69]
  PIN q[6]
    DIRECTION OUTPUT ;
    USE SIGNAL ;
    PORT
      LAYER M7 ;
        RECT  83.2 0 83.232 0.069 ;
    END
  END q[6]
  PIN q[70]
    DIRECTION OUTPUT ;
    USE SIGNAL ;
    PORT
      LAYER M5 ;
        RECT  15.072 0 15.096 0.084 ;
    END
  END q[70]
  PIN q[71]
    DIRECTION OUTPUT ;
    USE SIGNAL ;
    PORT
      LAYER M7 ;
        RECT  8.896 0 8.928 0.069 ;
    END
  END q[71]
  PIN q[72]
    DIRECTION OUTPUT ;
    USE SIGNAL ;
    PORT
      LAYER M7 ;
        RECT  6.912 0 6.944 0.069 ;
    END
  END q[72]
  PIN q[73]
    DIRECTION OUTPUT ;
    USE SIGNAL ;
    PORT
      LAYER M5 ;
        RECT  5.568 0 5.592 0.084 ;
    END
  END q[73]
  PIN q[74]
    DIRECTION OUTPUT ;
    USE SIGNAL ;
    PORT
      LAYER M5 ;
        RECT  11.664 0 11.688 0.084 ;
    END
  END q[74]
  PIN q[75]
    DIRECTION OUTPUT ;
    USE SIGNAL ;
    PORT
      LAYER M5 ;
        RECT  3.216 0 3.24 0.084 ;
    END
  END q[75]
  PIN q[76]
    DIRECTION OUTPUT ;
    USE SIGNAL ;
    PORT
      LAYER M5 ;
        RECT  4.992 0 5.016 0.084 ;
    END
  END q[76]
  PIN q[77]
    DIRECTION OUTPUT ;
    USE SIGNAL ;
    PORT
      LAYER M7 ;
        RECT  8.832 0 8.864 0.069 ;
    END
  END q[77]
  PIN q[78]
    DIRECTION OUTPUT ;
    USE SIGNAL ;
    PORT
      LAYER M5 ;
        RECT  1.632 0 1.656 0.084 ;
    END
  END q[78]
  PIN q[79]
    DIRECTION OUTPUT ;
    USE SIGNAL ;
    PORT
      LAYER M5 ;
        RECT  2.16 0 2.184 0.084 ;
    END
  END q[79]
  PIN q[7]
    DIRECTION OUTPUT ;
    USE SIGNAL ;
    PORT
      LAYER M5 ;
        RECT  78.528 0 78.552 0.084 ;
    END
  END q[7]
  PIN q[80]
    DIRECTION OUTPUT ;
    USE SIGNAL ;
    PORT
      LAYER M5 ;
        RECT  3.696 0 3.72 0.084 ;
    END
  END q[80]
  PIN q[81]
    DIRECTION OUTPUT ;
    USE SIGNAL ;
    PORT
      LAYER M5 ;
        RECT  2.208 0 2.232 0.084 ;
    END
  END q[81]
  PIN q[82]
    DIRECTION OUTPUT ;
    USE SIGNAL ;
    PORT
      LAYER M5 ;
        RECT  5.136 0 5.16 0.084 ;
    END
  END q[82]
  PIN q[83]
    DIRECTION OUTPUT ;
    USE SIGNAL ;
    PORT
      LAYER M5 ;
        RECT  3.6 0 3.624 0.084 ;
    END
  END q[83]
  PIN q[84]
    DIRECTION OUTPUT ;
    USE SIGNAL ;
    PORT
      LAYER M7 ;
        RECT  7.68 0 7.712 0.069 ;
    END
  END q[84]
  PIN q[85]
    DIRECTION OUTPUT ;
    USE SIGNAL ;
    PORT
      LAYER M7 ;
        RECT  9.152 0 9.184 0.069 ;
    END
  END q[85]
  PIN q[86]
    DIRECTION OUTPUT ;
    USE SIGNAL ;
    PORT
      LAYER M7 ;
        RECT  7.104 0 7.136 0.069 ;
    END
  END q[86]
  PIN q[87]
    DIRECTION OUTPUT ;
    USE SIGNAL ;
    PORT
      LAYER M5 ;
        RECT  1.92 0 1.944 0.084 ;
    END
  END q[87]
  PIN q[88]
    DIRECTION OUTPUT ;
    USE SIGNAL ;
    PORT
      LAYER M7 ;
        RECT  8 0 8.032 0.069 ;
    END
  END q[88]
  PIN q[89]
    DIRECTION OUTPUT ;
    USE SIGNAL ;
    PORT
      LAYER M7 ;
        RECT  9.728 0 9.76 0.069 ;
    END
  END q[89]
  PIN q[8]
    DIRECTION OUTPUT ;
    USE SIGNAL ;
    PORT
      LAYER M5 ;
        RECT  81.168 0 81.192 0.084 ;
    END
  END q[8]
  PIN q[90]
    DIRECTION OUTPUT ;
    USE SIGNAL ;
    PORT
      LAYER M5 ;
        RECT  14.4 0 14.424 0.084 ;
    END
  END q[90]
  PIN q[91]
    DIRECTION OUTPUT ;
    USE SIGNAL ;
    PORT
      LAYER M7 ;
        RECT  28.8 0 28.832 0.069 ;
    END
  END q[91]
  PIN q[92]
    DIRECTION OUTPUT ;
    USE SIGNAL ;
    PORT
      LAYER M5 ;
        RECT  13.392 0 13.416 0.084 ;
    END
  END q[92]
  PIN q[93]
    DIRECTION OUTPUT ;
    USE SIGNAL ;
    PORT
      LAYER M5 ;
        RECT  14.544 0 14.568 0.084 ;
    END
  END q[93]
  PIN q[94]
    DIRECTION OUTPUT ;
    USE SIGNAL ;
    PORT
      LAYER M5 ;
        RECT  16.56 0 16.584 0.084 ;
    END
  END q[94]
  PIN q[95]
    DIRECTION OUTPUT ;
    USE SIGNAL ;
    PORT
      LAYER M7 ;
        RECT  21.824 0 21.856 0.069 ;
    END
  END q[95]
  PIN q[96]
    DIRECTION OUTPUT ;
    USE SIGNAL ;
    PORT
      LAYER M5 ;
        RECT  39.168 0 39.192 0.084 ;
    END
  END q[96]
  PIN q[97]
    DIRECTION OUTPUT ;
    USE SIGNAL ;
    PORT
      LAYER M5 ;
        RECT  22.992 0 23.016 0.084 ;
    END
  END q[97]
  PIN q[98]
    DIRECTION OUTPUT ;
    USE SIGNAL ;
    PORT
      LAYER M7 ;
        RECT  19.2 0 19.232 0.069 ;
    END
  END q[98]
  PIN q[99]
    DIRECTION OUTPUT ;
    USE SIGNAL ;
    PORT
      LAYER M7 ;
        RECT  28.672 0 28.704 0.069 ;
    END
  END q[99]
  PIN q[9]
    DIRECTION OUTPUT ;
    USE SIGNAL ;
    PORT
      LAYER M5 ;
        RECT  78.384 0 78.408 0.084 ;
    END
  END q[9]
  PIN rst_e
    DIRECTION INPUT ;
    USE SIGNAL ;
    PORT
      LAYER M7 ;
        RECT  46.336 0 46.368 0.069 ;
    END
  END rst_e
  PIN rst_p
    DIRECTION INPUT ;
    USE SIGNAL ;
    PORT
      LAYER M5 ;
        RECT  39.792 0 39.816 0.084 ;
    END
  END rst_p
  PIN v_bad
    DIRECTION OUTPUT ;
    USE SIGNAL ;
    PORT
      LAYER M5 ;
        RECT  49.632 0 49.656 0.084 ;
    END
  END v_bad
  PIN v_cbad
    DIRECTION OUTPUT ;
    USE SIGNAL ;
    PORT
      LAYER M5 ;
        RECT  44.592 0 44.616 0.084 ;
    END
  END v_cbad
  PIN v_ce
    DIRECTION OUTPUT ;
    USE SIGNAL ;
    PORT
      LAYER M7 ;
        RECT  46.656 0 46.688 0.069 ;
    END
  END v_ce
  PIN v_clean
    DIRECTION OUTPUT ;
    USE SIGNAL ;
    PORT
      LAYER M5 ;
        RECT  40.368 0 40.392 0.084 ;
    END
  END v_clean
  PIN v_same
    DIRECTION OUTPUT ;
    USE SIGNAL ;
    PORT
      LAYER M5 ;
        RECT  41.136 0 41.16 0.084 ;
    END
  END v_same
  PIN v_ue
    DIRECTION OUTPUT ;
    USE SIGNAL ;
    PORT
      LAYER M5 ;
        RECT  43.2 0 43.224 0.084 ;
    END
  END v_ue
  PIN VDD
    DIRECTION INOUT ;
    USE POWER ;
    PORT
      LAYER M6 ;
        RECT  1.08 55.833 88.884 56.121 ;
        RECT  1.08 50.433 88.884 50.721 ;
        RECT  1.08 45.033 88.884 45.321 ;
        RECT  1.08 39.633 88.884 39.921 ;
        RECT  1.08 34.233 88.884 34.521 ;
        RECT  1.08 28.833 88.884 29.121 ;
        RECT  1.08 23.433 88.884 23.721 ;
        RECT  1.08 18.033 88.884 18.321 ;
        RECT  1.08 12.633 88.884 12.921 ;
        RECT  1.08 7.233 88.884 7.521 ;
        RECT  1.08 1.833 88.884 2.121 ;
    END
  END VDD
  PIN VSS
    DIRECTION INOUT ;
    USE GROUND ;
    PORT
      LAYER M6 ;
        RECT  1.08 55.449 88.884 55.737 ;
        RECT  1.08 50.049 88.884 50.337 ;
        RECT  1.08 44.649 88.884 44.937 ;
        RECT  1.08 39.249 88.884 39.537 ;
        RECT  1.08 33.849 88.884 34.137 ;
        RECT  1.08 28.449 88.884 28.737 ;
        RECT  1.08 23.049 88.884 23.337 ;
        RECT  1.08 17.649 88.884 17.937 ;
        RECT  1.08 12.249 88.884 12.537 ;
        RECT  1.08 6.849 88.884 7.137 ;
        RECT  1.08 1.449 88.884 1.737 ;
    END
  END VSS
  OBS
    LAYER RVTN ;
     RECT  1.08 0 89.309 58 ;
    LAYER RVTP ;
     RECT  1.08 0 89.309 58 ;
    LAYER M1 ;
     RECT  1.08 0 89.309 58 ;
    LAYER M2 ;
     RECT  1.08 0 89.309 58 ;
    LAYER M3 ;
     RECT  1.08 0 89.309 58 ;
    LAYER M4 ;
     RECT  1.08 0 89.309 58 ;
    LAYER M5 ;
     RECT  1.08 0 89.309 58 ;
    LAYER M6 ;
     RECT  1.08 0 89.309 58 ;
    LAYER M7 ;
     RECT  1.08 0 89.309 58 ;
  END
END ot_hbm_w2_stn_slice5
END LIBRARY
